VERSION 5.8 ;
BUSBITCHARS "[]" ;
DIVIDERCHAR "/" ;
UNITS
    DATABASE MICRONS 1000 ;
END UNITS

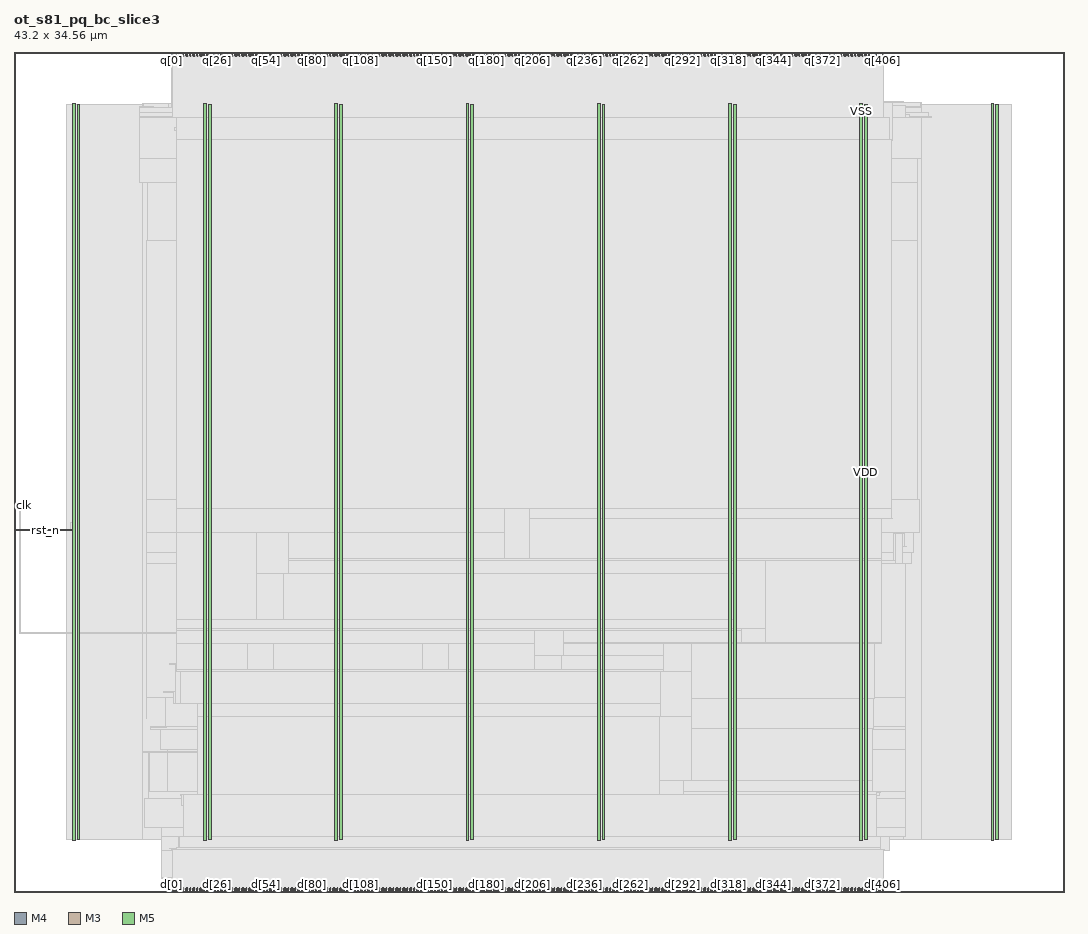
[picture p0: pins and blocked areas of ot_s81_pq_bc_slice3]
MACRO ot_s81_pq_bc_slice3
  FOREIGN ot_s81_pq_bc_slice3 0 0 ;
  CLASS BLOCK ;
  SIZE 43.2 BY 34.56 ;
  PIN clk
    DIRECTION INPUT ;
    USE SIGNAL ;
    PORT
      LAYER M4 ;
        RECT  0 15.888 0.192 15.912 ;
    END
    PORT
      LAYER M4 ;
        RECT  0.156 15.888 0.275 15.912 ;
    END
  END clk
  PIN d[0]
    DIRECTION INPUT ;
    USE SIGNAL ;
    PORT
      LAYER M3 ;
        RECT  6.48 0 6.498 0.144 ;
    END
  END d[0]
  PIN d[100]
    DIRECTION INPUT ;
    USE SIGNAL ;
    PORT
      LAYER M3 ;
        RECT  13.68 0 13.698 0.144 ;
    END
  END d[100]
  PIN d[101]
    DIRECTION INPUT ;
    USE SIGNAL ;
    PORT
      LAYER M5 ;
        RECT  13.728 0 13.752 0.192 ;
    END
  END d[101]
  PIN d[102]
    DIRECTION INPUT ;
    USE SIGNAL ;
    PORT
      LAYER M3 ;
        RECT  13.824 0 13.842 0.144 ;
    END
  END d[102]
  PIN d[103]
    DIRECTION INPUT ;
    USE SIGNAL ;
    PORT
      LAYER M5 ;
        RECT  13.872 0 13.896 0.192 ;
    END
  END d[103]
  PIN d[104]
    DIRECTION INPUT ;
    USE SIGNAL ;
    PORT
      LAYER M3 ;
        RECT  13.968 0 13.986 0.144 ;
    END
  END d[104]
  PIN d[105]
    DIRECTION INPUT ;
    USE SIGNAL ;
    PORT
      LAYER M5 ;
        RECT  14.016 0 14.04 0.192 ;
    END
  END d[105]
  PIN d[106]
    DIRECTION INPUT ;
    USE SIGNAL ;
    PORT
      LAYER M3 ;
        RECT  14.112 0 14.13 0.144 ;
    END
  END d[106]
  PIN d[107]
    DIRECTION INPUT ;
    USE SIGNAL ;
    PORT
      LAYER M5 ;
        RECT  14.16 0 14.184 0.192 ;
    END
  END d[107]
  PIN d[108]
    DIRECTION INPUT ;
    USE SIGNAL ;
    PORT
      LAYER M3 ;
        RECT  14.256 0 14.274 0.144 ;
    END
  END d[108]
  PIN d[109]
    DIRECTION INPUT ;
    USE SIGNAL ;
    PORT
      LAYER M5 ;
        RECT  14.304 0 14.328 0.192 ;
    END
  END d[109]
  PIN d[10]
    DIRECTION INPUT ;
    USE SIGNAL ;
    PORT
      LAYER M3 ;
        RECT  7.2 0 7.218 0.144 ;
    END
  END d[10]
  PIN d[110]
    DIRECTION INPUT ;
    USE SIGNAL ;
    PORT
      LAYER M3 ;
        RECT  14.4 0 14.418 0.144 ;
    END
  END d[110]
  PIN d[111]
    DIRECTION INPUT ;
    USE SIGNAL ;
    PORT
      LAYER M5 ;
        RECT  14.448 0 14.472 0.192 ;
    END
  END d[111]
  PIN d[112]
    DIRECTION INPUT ;
    USE SIGNAL ;
    PORT
      LAYER M3 ;
        RECT  14.544 0 14.562 0.144 ;
    END
  END d[112]
  PIN d[113]
    DIRECTION INPUT ;
    USE SIGNAL ;
    PORT
      LAYER M5 ;
        RECT  14.592 0 14.616 0.192 ;
    END
  END d[113]
  PIN d[114]
    DIRECTION INPUT ;
    USE SIGNAL ;
    PORT
      LAYER M3 ;
        RECT  14.688 0 14.706 0.144 ;
    END
  END d[114]
  PIN d[115]
    DIRECTION INPUT ;
    USE SIGNAL ;
    PORT
      LAYER M5 ;
        RECT  14.736 0 14.76 0.192 ;
    END
  END d[115]
  PIN d[116]
    DIRECTION INPUT ;
    USE SIGNAL ;
    PORT
      LAYER M3 ;
        RECT  14.832 0 14.85 0.144 ;
    END
  END d[116]
  PIN d[117]
    DIRECTION INPUT ;
    USE SIGNAL ;
    PORT
      LAYER M5 ;
        RECT  14.88 0 14.904 0.192 ;
    END
  END d[117]
  PIN d[118]
    DIRECTION INPUT ;
    USE SIGNAL ;
    PORT
      LAYER M3 ;
        RECT  14.976 0 14.994 0.144 ;
    END
  END d[118]
  PIN d[119]
    DIRECTION INPUT ;
    USE SIGNAL ;
    PORT
      LAYER M5 ;
        RECT  15.024 0 15.048 0.192 ;
    END
  END d[119]
  PIN d[11]
    DIRECTION INPUT ;
    USE SIGNAL ;
    PORT
      LAYER M5 ;
        RECT  7.248 0 7.272 0.192 ;
    END
  END d[11]
  PIN d[120]
    DIRECTION INPUT ;
    USE SIGNAL ;
    PORT
      LAYER M3 ;
        RECT  15.12 0 15.138 0.144 ;
    END
  END d[120]
  PIN d[121]
    DIRECTION INPUT ;
    USE SIGNAL ;
    PORT
      LAYER M5 ;
        RECT  15.168 0 15.192 0.192 ;
    END
  END d[121]
  PIN d[122]
    DIRECTION INPUT ;
    USE SIGNAL ;
    PORT
      LAYER M3 ;
        RECT  15.264 0 15.282 0.144 ;
    END
  END d[122]
  PIN d[123]
    DIRECTION INPUT ;
    USE SIGNAL ;
    PORT
      LAYER M5 ;
        RECT  15.312 0 15.336 0.192 ;
    END
  END d[123]
  PIN d[124]
    DIRECTION INPUT ;
    USE SIGNAL ;
    PORT
      LAYER M3 ;
        RECT  15.408 0 15.426 0.144 ;
    END
  END d[124]
  PIN d[125]
    DIRECTION INPUT ;
    USE SIGNAL ;
    PORT
      LAYER M5 ;
        RECT  15.456 0 15.48 0.192 ;
    END
  END d[125]
  PIN d[126]
    DIRECTION INPUT ;
    USE SIGNAL ;
    PORT
      LAYER M3 ;
        RECT  15.552 0 15.57 0.144 ;
    END
  END d[126]
  PIN d[127]
    DIRECTION INPUT ;
    USE SIGNAL ;
    PORT
      LAYER M5 ;
        RECT  15.6 0 15.624 0.192 ;
    END
  END d[127]
  PIN d[128]
    DIRECTION INPUT ;
    USE SIGNAL ;
    PORT
      LAYER M3 ;
        RECT  15.696 0 15.714 0.144 ;
    END
  END d[128]
  PIN d[129]
    DIRECTION INPUT ;
    USE SIGNAL ;
    PORT
      LAYER M5 ;
        RECT  15.744 0 15.768 0.192 ;
    END
  END d[129]
  PIN d[12]
    DIRECTION INPUT ;
    USE SIGNAL ;
    PORT
      LAYER M3 ;
        RECT  7.344 0 7.362 0.144 ;
    END
  END d[12]
  PIN d[130]
    DIRECTION INPUT ;
    USE SIGNAL ;
    PORT
      LAYER M3 ;
        RECT  15.84 0 15.858 0.144 ;
    END
  END d[130]
  PIN d[131]
    DIRECTION INPUT ;
    USE SIGNAL ;
    PORT
      LAYER M5 ;
        RECT  15.888 0 15.912 0.192 ;
    END
  END d[131]
  PIN d[132]
    DIRECTION INPUT ;
    USE SIGNAL ;
    PORT
      LAYER M3 ;
        RECT  15.984 0 16.002 0.144 ;
    END
  END d[132]
  PIN d[133]
    DIRECTION INPUT ;
    USE SIGNAL ;
    PORT
      LAYER M5 ;
        RECT  16.032 0 16.056 0.192 ;
    END
  END d[133]
  PIN d[134]
    DIRECTION INPUT ;
    USE SIGNAL ;
    PORT
      LAYER M3 ;
        RECT  16.128 0 16.146 0.144 ;
    END
  END d[134]
  PIN d[135]
    DIRECTION INPUT ;
    USE SIGNAL ;
    PORT
      LAYER M5 ;
        RECT  16.176 0 16.2 0.192 ;
    END
  END d[135]
  PIN d[136]
    DIRECTION INPUT ;
    USE SIGNAL ;
    PORT
      LAYER M3 ;
        RECT  16.272 0 16.29 0.144 ;
    END
  END d[136]
  PIN d[137]
    DIRECTION INPUT ;
    USE SIGNAL ;
    PORT
      LAYER M5 ;
        RECT  16.32 0 16.344 0.192 ;
    END
  END d[137]
  PIN d[138]
    DIRECTION INPUT ;
    USE SIGNAL ;
    PORT
      LAYER M3 ;
        RECT  16.416 0 16.434 0.144 ;
    END
  END d[138]
  PIN d[139]
    DIRECTION INPUT ;
    USE SIGNAL ;
    PORT
      LAYER M5 ;
        RECT  16.464 0 16.488 0.192 ;
    END
  END d[139]
  PIN d[13]
    DIRECTION INPUT ;
    USE SIGNAL ;
    PORT
      LAYER M5 ;
        RECT  7.392 0 7.416 0.192 ;
    END
  END d[13]
  PIN d[140]
    DIRECTION INPUT ;
    USE SIGNAL ;
    PORT
      LAYER M3 ;
        RECT  16.56 0 16.578 0.144 ;
    END
  END d[140]
  PIN d[141]
    DIRECTION INPUT ;
    USE SIGNAL ;
    PORT
      LAYER M5 ;
        RECT  16.608 0 16.632 0.192 ;
    END
  END d[141]
  PIN d[142]
    DIRECTION INPUT ;
    USE SIGNAL ;
    PORT
      LAYER M3 ;
        RECT  16.704 0 16.722 0.144 ;
    END
  END d[142]
  PIN d[143]
    DIRECTION INPUT ;
    USE SIGNAL ;
    PORT
      LAYER M5 ;
        RECT  16.752 0 16.776 0.192 ;
    END
  END d[143]
  PIN d[144]
    DIRECTION INPUT ;
    USE SIGNAL ;
    PORT
      LAYER M3 ;
        RECT  16.848 0 16.866 0.144 ;
    END
  END d[144]
  PIN d[145]
    DIRECTION INPUT ;
    USE SIGNAL ;
    PORT
      LAYER M5 ;
        RECT  16.896 0 16.92 0.192 ;
    END
  END d[145]
  PIN d[146]
    DIRECTION INPUT ;
    USE SIGNAL ;
    PORT
      LAYER M3 ;
        RECT  16.992 0 17.01 0.144 ;
    END
  END d[146]
  PIN d[147]
    DIRECTION INPUT ;
    USE SIGNAL ;
    PORT
      LAYER M5 ;
        RECT  17.04 0 17.064 0.192 ;
    END
  END d[147]
  PIN d[148]
    DIRECTION INPUT ;
    USE SIGNAL ;
    PORT
      LAYER M3 ;
        RECT  17.136 0 17.154 0.144 ;
    END
  END d[148]
  PIN d[149]
    DIRECTION INPUT ;
    USE SIGNAL ;
    PORT
      LAYER M5 ;
        RECT  17.184 0 17.208 0.192 ;
    END
  END d[149]
  PIN d[14]
    DIRECTION INPUT ;
    USE SIGNAL ;
    PORT
      LAYER M3 ;
        RECT  7.488 0 7.506 0.144 ;
    END
  END d[14]
  PIN d[150]
    DIRECTION INPUT ;
    USE SIGNAL ;
    PORT
      LAYER M3 ;
        RECT  17.28 0 17.298 0.144 ;
    END
  END d[150]
  PIN d[151]
    DIRECTION INPUT ;
    USE SIGNAL ;
    PORT
      LAYER M5 ;
        RECT  17.328 0 17.352 0.192 ;
    END
  END d[151]
  PIN d[152]
    DIRECTION INPUT ;
    USE SIGNAL ;
    PORT
      LAYER M3 ;
        RECT  17.424 0 17.442 0.144 ;
    END
  END d[152]
  PIN d[153]
    DIRECTION INPUT ;
    USE SIGNAL ;
    PORT
      LAYER M5 ;
        RECT  17.472 0 17.496 0.192 ;
    END
  END d[153]
  PIN d[154]
    DIRECTION INPUT ;
    USE SIGNAL ;
    PORT
      LAYER M3 ;
        RECT  17.568 0 17.586 0.144 ;
    END
  END d[154]
  PIN d[155]
    DIRECTION INPUT ;
    USE SIGNAL ;
    PORT
      LAYER M5 ;
        RECT  17.616 0 17.64 0.192 ;
    END
  END d[155]
  PIN d[156]
    DIRECTION INPUT ;
    USE SIGNAL ;
    PORT
      LAYER M3 ;
        RECT  17.712 0 17.73 0.144 ;
    END
  END d[156]
  PIN d[157]
    DIRECTION INPUT ;
    USE SIGNAL ;
    PORT
      LAYER M5 ;
        RECT  17.76 0 17.784 0.192 ;
    END
  END d[157]
  PIN d[158]
    DIRECTION INPUT ;
    USE SIGNAL ;
    PORT
      LAYER M3 ;
        RECT  17.856 0 17.874 0.144 ;
    END
  END d[158]
  PIN d[159]
    DIRECTION INPUT ;
    USE SIGNAL ;
    PORT
      LAYER M5 ;
        RECT  17.904 0 17.928 0.192 ;
    END
  END d[159]
  PIN d[15]
    DIRECTION INPUT ;
    USE SIGNAL ;
    PORT
      LAYER M5 ;
        RECT  7.536 0 7.56 0.192 ;
    END
  END d[15]
  PIN d[160]
    DIRECTION INPUT ;
    USE SIGNAL ;
    PORT
      LAYER M3 ;
        RECT  18 0 18.018 0.144 ;
    END
  END d[160]
  PIN d[161]
    DIRECTION INPUT ;
    USE SIGNAL ;
    PORT
      LAYER M5 ;
        RECT  18.048 0 18.072 0.192 ;
    END
  END d[161]
  PIN d[162]
    DIRECTION INPUT ;
    USE SIGNAL ;
    PORT
      LAYER M3 ;
        RECT  18.144 0 18.162 0.144 ;
    END
  END d[162]
  PIN d[163]
    DIRECTION INPUT ;
    USE SIGNAL ;
    PORT
      LAYER M5 ;
        RECT  18.192 0 18.216 0.192 ;
    END
  END d[163]
  PIN d[164]
    DIRECTION INPUT ;
    USE SIGNAL ;
    PORT
      LAYER M3 ;
        RECT  18.288 0 18.306 0.144 ;
    END
  END d[164]
  PIN d[165]
    DIRECTION INPUT ;
    USE SIGNAL ;
    PORT
      LAYER M5 ;
        RECT  18.336 0 18.36 0.192 ;
    END
  END d[165]
  PIN d[166]
    DIRECTION INPUT ;
    USE SIGNAL ;
    PORT
      LAYER M3 ;
        RECT  18.432 0 18.45 0.144 ;
    END
  END d[166]
  PIN d[167]
    DIRECTION INPUT ;
    USE SIGNAL ;
    PORT
      LAYER M5 ;
        RECT  18.48 0 18.504 0.192 ;
    END
  END d[167]
  PIN d[168]
    DIRECTION INPUT ;
    USE SIGNAL ;
    PORT
      LAYER M3 ;
        RECT  18.576 0 18.594 0.144 ;
    END
  END d[168]
  PIN d[169]
    DIRECTION INPUT ;
    USE SIGNAL ;
    PORT
      LAYER M5 ;
        RECT  18.624 0 18.648 0.192 ;
    END
  END d[169]
  PIN d[16]
    DIRECTION INPUT ;
    USE SIGNAL ;
    PORT
      LAYER M3 ;
        RECT  7.632 0 7.65 0.144 ;
    END
  END d[16]
  PIN d[170]
    DIRECTION INPUT ;
    USE SIGNAL ;
    PORT
      LAYER M3 ;
        RECT  18.72 0 18.738 0.144 ;
    END
  END d[170]
  PIN d[171]
    DIRECTION INPUT ;
    USE SIGNAL ;
    PORT
      LAYER M5 ;
        RECT  18.768 0 18.792 0.192 ;
    END
  END d[171]
  PIN d[172]
    DIRECTION INPUT ;
    USE SIGNAL ;
    PORT
      LAYER M3 ;
        RECT  18.864 0 18.882 0.144 ;
    END
  END d[172]
  PIN d[173]
    DIRECTION INPUT ;
    USE SIGNAL ;
    PORT
      LAYER M5 ;
        RECT  18.912 0 18.936 0.192 ;
    END
  END d[173]
  PIN d[174]
    DIRECTION INPUT ;
    USE SIGNAL ;
    PORT
      LAYER M3 ;
        RECT  19.008 0 19.026 0.144 ;
    END
  END d[174]
  PIN d[175]
    DIRECTION INPUT ;
    USE SIGNAL ;
    PORT
      LAYER M5 ;
        RECT  19.056 0 19.08 0.192 ;
    END
  END d[175]
  PIN d[176]
    DIRECTION INPUT ;
    USE SIGNAL ;
    PORT
      LAYER M3 ;
        RECT  19.152 0 19.17 0.144 ;
    END
  END d[176]
  PIN d[177]
    DIRECTION INPUT ;
    USE SIGNAL ;
    PORT
      LAYER M5 ;
        RECT  19.2 0 19.224 0.192 ;
    END
  END d[177]
  PIN d[178]
    DIRECTION INPUT ;
    USE SIGNAL ;
    PORT
      LAYER M3 ;
        RECT  19.296 0 19.314 0.144 ;
    END
  END d[178]
  PIN d[179]
    DIRECTION INPUT ;
    USE SIGNAL ;
    PORT
      LAYER M5 ;
        RECT  19.344 0 19.368 0.192 ;
    END
  END d[179]
  PIN d[17]
    DIRECTION INPUT ;
    USE SIGNAL ;
    PORT
      LAYER M5 ;
        RECT  7.68 0 7.704 0.192 ;
    END
  END d[17]
  PIN d[180]
    DIRECTION INPUT ;
    USE SIGNAL ;
    PORT
      LAYER M3 ;
        RECT  19.44 0 19.458 0.144 ;
    END
  END d[180]
  PIN d[181]
    DIRECTION INPUT ;
    USE SIGNAL ;
    PORT
      LAYER M5 ;
        RECT  19.488 0 19.512 0.192 ;
    END
  END d[181]
  PIN d[182]
    DIRECTION INPUT ;
    USE SIGNAL ;
    PORT
      LAYER M3 ;
        RECT  19.584 0 19.602 0.144 ;
    END
  END d[182]
  PIN d[183]
    DIRECTION INPUT ;
    USE SIGNAL ;
    PORT
      LAYER M5 ;
        RECT  19.632 0 19.656 0.192 ;
    END
  END d[183]
  PIN d[184]
    DIRECTION INPUT ;
    USE SIGNAL ;
    PORT
      LAYER M3 ;
        RECT  19.728 0 19.746 0.144 ;
    END
  END d[184]
  PIN d[185]
    DIRECTION INPUT ;
    USE SIGNAL ;
    PORT
      LAYER M5 ;
        RECT  19.776 0 19.8 0.192 ;
    END
  END d[185]
  PIN d[186]
    DIRECTION INPUT ;
    USE SIGNAL ;
    PORT
      LAYER M3 ;
        RECT  19.872 0 19.89 0.144 ;
    END
  END d[186]
  PIN d[187]
    DIRECTION INPUT ;
    USE SIGNAL ;
    PORT
      LAYER M5 ;
        RECT  19.92 0 19.944 0.192 ;
    END
  END d[187]
  PIN d[188]
    DIRECTION INPUT ;
    USE SIGNAL ;
    PORT
      LAYER M3 ;
        RECT  20.016 0 20.034 0.144 ;
    END
  END d[188]
  PIN d[189]
    DIRECTION INPUT ;
    USE SIGNAL ;
    PORT
      LAYER M5 ;
        RECT  20.064 0 20.088 0.192 ;
    END
  END d[189]
  PIN d[18]
    DIRECTION INPUT ;
    USE SIGNAL ;
    PORT
      LAYER M3 ;
        RECT  7.776 0 7.794 0.144 ;
    END
  END d[18]
  PIN d[190]
    DIRECTION INPUT ;
    USE SIGNAL ;
    PORT
      LAYER M3 ;
        RECT  20.16 0 20.178 0.144 ;
    END
  END d[190]
  PIN d[191]
    DIRECTION INPUT ;
    USE SIGNAL ;
    PORT
      LAYER M5 ;
        RECT  20.208 0 20.232 0.192 ;
    END
  END d[191]
  PIN d[192]
    DIRECTION INPUT ;
    USE SIGNAL ;
    PORT
      LAYER M3 ;
        RECT  20.304 0 20.322 0.144 ;
    END
  END d[192]
  PIN d[193]
    DIRECTION INPUT ;
    USE SIGNAL ;
    PORT
      LAYER M5 ;
        RECT  20.352 0 20.376 0.192 ;
    END
  END d[193]
  PIN d[194]
    DIRECTION INPUT ;
    USE SIGNAL ;
    PORT
      LAYER M3 ;
        RECT  20.448 0 20.466 0.144 ;
    END
  END d[194]
  PIN d[195]
    DIRECTION INPUT ;
    USE SIGNAL ;
    PORT
      LAYER M5 ;
        RECT  20.496 0 20.52 0.192 ;
    END
  END d[195]
  PIN d[196]
    DIRECTION INPUT ;
    USE SIGNAL ;
    PORT
      LAYER M3 ;
        RECT  20.592 0 20.61 0.144 ;
    END
  END d[196]
  PIN d[197]
    DIRECTION INPUT ;
    USE SIGNAL ;
    PORT
      LAYER M5 ;
        RECT  20.64 0 20.664 0.192 ;
    END
  END d[197]
  PIN d[198]
    DIRECTION INPUT ;
    USE SIGNAL ;
    PORT
      LAYER M3 ;
        RECT  20.736 0 20.754 0.144 ;
    END
  END d[198]
  PIN d[199]
    DIRECTION INPUT ;
    USE SIGNAL ;
    PORT
      LAYER M5 ;
        RECT  20.784 0 20.808 0.192 ;
    END
  END d[199]
  PIN d[19]
    DIRECTION INPUT ;
    USE SIGNAL ;
    PORT
      LAYER M5 ;
        RECT  7.824 0 7.848 0.192 ;
    END
  END d[19]
  PIN d[1]
    DIRECTION INPUT ;
    USE SIGNAL ;
    PORT
      LAYER M5 ;
        RECT  6.528 0 6.552 0.192 ;
    END
  END d[1]
  PIN d[200]
    DIRECTION INPUT ;
    USE SIGNAL ;
    PORT
      LAYER M3 ;
        RECT  20.88 0 20.898 0.144 ;
    END
  END d[200]
  PIN d[201]
    DIRECTION INPUT ;
    USE SIGNAL ;
    PORT
      LAYER M5 ;
        RECT  20.928 0 20.952 0.192 ;
    END
  END d[201]
  PIN d[202]
    DIRECTION INPUT ;
    USE SIGNAL ;
    PORT
      LAYER M3 ;
        RECT  21.024 0 21.042 0.144 ;
    END
  END d[202]
  PIN d[203]
    DIRECTION INPUT ;
    USE SIGNAL ;
    PORT
      LAYER M5 ;
        RECT  21.072 0 21.096 0.192 ;
    END
  END d[203]
  PIN d[204]
    DIRECTION INPUT ;
    USE SIGNAL ;
    PORT
      LAYER M3 ;
        RECT  21.168 0 21.186 0.144 ;
    END
  END d[204]
  PIN d[205]
    DIRECTION INPUT ;
    USE SIGNAL ;
    PORT
      LAYER M5 ;
        RECT  21.216 0 21.24 0.192 ;
    END
  END d[205]
  PIN d[206]
    DIRECTION INPUT ;
    USE SIGNAL ;
    PORT
      LAYER M3 ;
        RECT  21.312 0 21.33 0.144 ;
    END
  END d[206]
  PIN d[207]
    DIRECTION INPUT ;
    USE SIGNAL ;
    PORT
      LAYER M5 ;
        RECT  21.36 0 21.384 0.192 ;
    END
  END d[207]
  PIN d[208]
    DIRECTION INPUT ;
    USE SIGNAL ;
    PORT
      LAYER M3 ;
        RECT  21.456 0 21.474 0.144 ;
    END
  END d[208]
  PIN d[209]
    DIRECTION INPUT ;
    USE SIGNAL ;
    PORT
      LAYER M5 ;
        RECT  21.504 0 21.528 0.192 ;
    END
  END d[209]
  PIN d[20]
    DIRECTION INPUT ;
    USE SIGNAL ;
    PORT
      LAYER M3 ;
        RECT  7.92 0 7.938 0.144 ;
    END
  END d[20]
  PIN d[210]
    DIRECTION INPUT ;
    USE SIGNAL ;
    PORT
      LAYER M3 ;
        RECT  21.6 0 21.618 0.144 ;
    END
  END d[210]
  PIN d[211]
    DIRECTION INPUT ;
    USE SIGNAL ;
    PORT
      LAYER M5 ;
        RECT  21.648 0 21.672 0.192 ;
    END
  END d[211]
  PIN d[212]
    DIRECTION INPUT ;
    USE SIGNAL ;
    PORT
      LAYER M3 ;
        RECT  21.744 0 21.762 0.144 ;
    END
  END d[212]
  PIN d[213]
    DIRECTION INPUT ;
    USE SIGNAL ;
    PORT
      LAYER M5 ;
        RECT  21.792 0 21.816 0.192 ;
    END
  END d[213]
  PIN d[214]
    DIRECTION INPUT ;
    USE SIGNAL ;
    PORT
      LAYER M3 ;
        RECT  21.888 0 21.906 0.144 ;
    END
  END d[214]
  PIN d[215]
    DIRECTION INPUT ;
    USE SIGNAL ;
    PORT
      LAYER M5 ;
        RECT  21.936 0 21.96 0.192 ;
    END
  END d[215]
  PIN d[216]
    DIRECTION INPUT ;
    USE SIGNAL ;
    PORT
      LAYER M3 ;
        RECT  22.032 0 22.05 0.144 ;
    END
  END d[216]
  PIN d[217]
    DIRECTION INPUT ;
    USE SIGNAL ;
    PORT
      LAYER M5 ;
        RECT  22.08 0 22.104 0.192 ;
    END
  END d[217]
  PIN d[218]
    DIRECTION INPUT ;
    USE SIGNAL ;
    PORT
      LAYER M3 ;
        RECT  22.176 0 22.194 0.144 ;
    END
  END d[218]
  PIN d[219]
    DIRECTION INPUT ;
    USE SIGNAL ;
    PORT
      LAYER M5 ;
        RECT  22.224 0 22.248 0.192 ;
    END
  END d[219]
  PIN d[21]
    DIRECTION INPUT ;
    USE SIGNAL ;
    PORT
      LAYER M5 ;
        RECT  7.968 0 7.992 0.192 ;
    END
  END d[21]
  PIN d[220]
    DIRECTION INPUT ;
    USE SIGNAL ;
    PORT
      LAYER M3 ;
        RECT  22.32 0 22.338 0.144 ;
    END
  END d[220]
  PIN d[221]
    DIRECTION INPUT ;
    USE SIGNAL ;
    PORT
      LAYER M5 ;
        RECT  22.368 0 22.392 0.192 ;
    END
  END d[221]
  PIN d[222]
    DIRECTION INPUT ;
    USE SIGNAL ;
    PORT
      LAYER M3 ;
        RECT  22.464 0 22.482 0.144 ;
    END
  END d[222]
  PIN d[223]
    DIRECTION INPUT ;
    USE SIGNAL ;
    PORT
      LAYER M5 ;
        RECT  22.512 0 22.536 0.192 ;
    END
  END d[223]
  PIN d[224]
    DIRECTION INPUT ;
    USE SIGNAL ;
    PORT
      LAYER M3 ;
        RECT  22.608 0 22.626 0.144 ;
    END
  END d[224]
  PIN d[225]
    DIRECTION INPUT ;
    USE SIGNAL ;
    PORT
      LAYER M5 ;
        RECT  22.656 0 22.68 0.192 ;
    END
  END d[225]
  PIN d[226]
    DIRECTION INPUT ;
    USE SIGNAL ;
    PORT
      LAYER M3 ;
        RECT  22.752 0 22.77 0.144 ;
    END
  END d[226]
  PIN d[227]
    DIRECTION INPUT ;
    USE SIGNAL ;
    PORT
      LAYER M5 ;
        RECT  22.8 0 22.824 0.192 ;
    END
  END d[227]
  PIN d[228]
    DIRECTION INPUT ;
    USE SIGNAL ;
    PORT
      LAYER M3 ;
        RECT  22.896 0 22.914 0.144 ;
    END
  END d[228]
  PIN d[229]
    DIRECTION INPUT ;
    USE SIGNAL ;
    PORT
      LAYER M5 ;
        RECT  22.944 0 22.968 0.192 ;
    END
  END d[229]
  PIN d[22]
    DIRECTION INPUT ;
    USE SIGNAL ;
    PORT
      LAYER M3 ;
        RECT  8.064 0 8.082 0.144 ;
    END
  END d[22]
  PIN d[230]
    DIRECTION INPUT ;
    USE SIGNAL ;
    PORT
      LAYER M3 ;
        RECT  23.04 0 23.058 0.144 ;
    END
  END d[230]
  PIN d[231]
    DIRECTION INPUT ;
    USE SIGNAL ;
    PORT
      LAYER M5 ;
        RECT  23.088 0 23.112 0.192 ;
    END
  END d[231]
  PIN d[232]
    DIRECTION INPUT ;
    USE SIGNAL ;
    PORT
      LAYER M3 ;
        RECT  23.184 0 23.202 0.144 ;
    END
  END d[232]
  PIN d[233]
    DIRECTION INPUT ;
    USE SIGNAL ;
    PORT
      LAYER M5 ;
        RECT  23.232 0 23.256 0.192 ;
    END
  END d[233]
  PIN d[234]
    DIRECTION INPUT ;
    USE SIGNAL ;
    PORT
      LAYER M3 ;
        RECT  23.328 0 23.346 0.144 ;
    END
  END d[234]
  PIN d[235]
    DIRECTION INPUT ;
    USE SIGNAL ;
    PORT
      LAYER M5 ;
        RECT  23.376 0 23.4 0.192 ;
    END
  END d[235]
  PIN d[236]
    DIRECTION INPUT ;
    USE SIGNAL ;
    PORT
      LAYER M3 ;
        RECT  23.472 0 23.49 0.144 ;
    END
  END d[236]
  PIN d[237]
    DIRECTION INPUT ;
    USE SIGNAL ;
    PORT
      LAYER M5 ;
        RECT  23.52 0 23.544 0.192 ;
    END
  END d[237]
  PIN d[238]
    DIRECTION INPUT ;
    USE SIGNAL ;
    PORT
      LAYER M3 ;
        RECT  23.616 0 23.634 0.144 ;
    END
  END d[238]
  PIN d[239]
    DIRECTION INPUT ;
    USE SIGNAL ;
    PORT
      LAYER M5 ;
        RECT  23.664 0 23.688 0.192 ;
    END
  END d[239]
  PIN d[23]
    DIRECTION INPUT ;
    USE SIGNAL ;
    PORT
      LAYER M5 ;
        RECT  8.112 0 8.136 0.192 ;
    END
  END d[23]
  PIN d[240]
    DIRECTION INPUT ;
    USE SIGNAL ;
    PORT
      LAYER M3 ;
        RECT  23.76 0 23.778 0.144 ;
    END
  END d[240]
  PIN d[241]
    DIRECTION INPUT ;
    USE SIGNAL ;
    PORT
      LAYER M5 ;
        RECT  23.808 0 23.832 0.192 ;
    END
  END d[241]
  PIN d[242]
    DIRECTION INPUT ;
    USE SIGNAL ;
    PORT
      LAYER M3 ;
        RECT  23.904 0 23.922 0.144 ;
    END
  END d[242]
  PIN d[243]
    DIRECTION INPUT ;
    USE SIGNAL ;
    PORT
      LAYER M5 ;
        RECT  23.952 0 23.976 0.192 ;
    END
  END d[243]
  PIN d[244]
    DIRECTION INPUT ;
    USE SIGNAL ;
    PORT
      LAYER M3 ;
        RECT  24.048 0 24.066 0.144 ;
    END
  END d[244]
  PIN d[245]
    DIRECTION INPUT ;
    USE SIGNAL ;
    PORT
      LAYER M5 ;
        RECT  24.096 0 24.12 0.192 ;
    END
  END d[245]
  PIN d[246]
    DIRECTION INPUT ;
    USE SIGNAL ;
    PORT
      LAYER M3 ;
        RECT  24.192 0 24.21 0.144 ;
    END
  END d[246]
  PIN d[247]
    DIRECTION INPUT ;
    USE SIGNAL ;
    PORT
      LAYER M5 ;
        RECT  24.24 0 24.264 0.192 ;
    END
  END d[247]
  PIN d[248]
    DIRECTION INPUT ;
    USE SIGNAL ;
    PORT
      LAYER M3 ;
        RECT  24.336 0 24.354 0.144 ;
    END
  END d[248]
  PIN d[249]
    DIRECTION INPUT ;
    USE SIGNAL ;
    PORT
      LAYER M5 ;
        RECT  24.384 0 24.408 0.192 ;
    END
  END d[249]
  PIN d[24]
    DIRECTION INPUT ;
    USE SIGNAL ;
    PORT
      LAYER M3 ;
        RECT  8.208 0 8.226 0.144 ;
    END
  END d[24]
  PIN d[250]
    DIRECTION INPUT ;
    USE SIGNAL ;
    PORT
      LAYER M3 ;
        RECT  24.48 0 24.498 0.144 ;
    END
  END d[250]
  PIN d[251]
    DIRECTION INPUT ;
    USE SIGNAL ;
    PORT
      LAYER M5 ;
        RECT  24.528 0 24.552 0.192 ;
    END
  END d[251]
  PIN d[252]
    DIRECTION INPUT ;
    USE SIGNAL ;
    PORT
      LAYER M3 ;
        RECT  24.624 0 24.642 0.144 ;
    END
  END d[252]
  PIN d[253]
    DIRECTION INPUT ;
    USE SIGNAL ;
    PORT
      LAYER M5 ;
        RECT  24.672 0 24.696 0.192 ;
    END
  END d[253]
  PIN d[254]
    DIRECTION INPUT ;
    USE SIGNAL ;
    PORT
      LAYER M3 ;
        RECT  24.768 0 24.786 0.144 ;
    END
  END d[254]
  PIN d[255]
    DIRECTION INPUT ;
    USE SIGNAL ;
    PORT
      LAYER M5 ;
        RECT  24.816 0 24.84 0.192 ;
    END
  END d[255]
  PIN d[256]
    DIRECTION INPUT ;
    USE SIGNAL ;
    PORT
      LAYER M3 ;
        RECT  24.912 0 24.93 0.144 ;
    END
  END d[256]
  PIN d[257]
    DIRECTION INPUT ;
    USE SIGNAL ;
    PORT
      LAYER M5 ;
        RECT  24.96 0 24.984 0.192 ;
    END
  END d[257]
  PIN d[258]
    DIRECTION INPUT ;
    USE SIGNAL ;
    PORT
      LAYER M3 ;
        RECT  25.056 0 25.074 0.144 ;
    END
  END d[258]
  PIN d[259]
    DIRECTION INPUT ;
    USE SIGNAL ;
    PORT
      LAYER M5 ;
        RECT  25.104 0 25.128 0.192 ;
    END
  END d[259]
  PIN d[25]
    DIRECTION INPUT ;
    USE SIGNAL ;
    PORT
      LAYER M5 ;
        RECT  8.256 0 8.28 0.192 ;
    END
  END d[25]
  PIN d[260]
    DIRECTION INPUT ;
    USE SIGNAL ;
    PORT
      LAYER M3 ;
        RECT  25.2 0 25.218 0.144 ;
    END
  END d[260]
  PIN d[261]
    DIRECTION INPUT ;
    USE SIGNAL ;
    PORT
      LAYER M5 ;
        RECT  25.248 0 25.272 0.192 ;
    END
  END d[261]
  PIN d[262]
    DIRECTION INPUT ;
    USE SIGNAL ;
    PORT
      LAYER M3 ;
        RECT  25.344 0 25.362 0.144 ;
    END
  END d[262]
  PIN d[263]
    DIRECTION INPUT ;
    USE SIGNAL ;
    PORT
      LAYER M5 ;
        RECT  25.392 0 25.416 0.192 ;
    END
  END d[263]
  PIN d[264]
    DIRECTION INPUT ;
    USE SIGNAL ;
    PORT
      LAYER M3 ;
        RECT  25.488 0 25.506 0.144 ;
    END
  END d[264]
  PIN d[265]
    DIRECTION INPUT ;
    USE SIGNAL ;
    PORT
      LAYER M5 ;
        RECT  25.536 0 25.56 0.192 ;
    END
  END d[265]
  PIN d[266]
    DIRECTION INPUT ;
    USE SIGNAL ;
    PORT
      LAYER M3 ;
        RECT  25.632 0 25.65 0.144 ;
    END
  END d[266]
  PIN d[267]
    DIRECTION INPUT ;
    USE SIGNAL ;
    PORT
      LAYER M5 ;
        RECT  25.68 0 25.704 0.192 ;
    END
  END d[267]
  PIN d[268]
    DIRECTION INPUT ;
    USE SIGNAL ;
    PORT
      LAYER M3 ;
        RECT  25.776 0 25.794 0.144 ;
    END
  END d[268]
  PIN d[269]
    DIRECTION INPUT ;
    USE SIGNAL ;
    PORT
      LAYER M5 ;
        RECT  25.824 0 25.848 0.192 ;
    END
  END d[269]
  PIN d[26]
    DIRECTION INPUT ;
    USE SIGNAL ;
    PORT
      LAYER M3 ;
        RECT  8.352 0 8.37 0.144 ;
    END
  END d[26]
  PIN d[270]
    DIRECTION INPUT ;
    USE SIGNAL ;
    PORT
      LAYER M3 ;
        RECT  25.92 0 25.938 0.144 ;
    END
  END d[270]
  PIN d[271]
    DIRECTION INPUT ;
    USE SIGNAL ;
    PORT
      LAYER M5 ;
        RECT  25.968 0 25.992 0.192 ;
    END
  END d[271]
  PIN d[272]
    DIRECTION INPUT ;
    USE SIGNAL ;
    PORT
      LAYER M3 ;
        RECT  26.064 0 26.082 0.144 ;
    END
  END d[272]
  PIN d[273]
    DIRECTION INPUT ;
    USE SIGNAL ;
    PORT
      LAYER M5 ;
        RECT  26.112 0 26.136 0.192 ;
    END
  END d[273]
  PIN d[274]
    DIRECTION INPUT ;
    USE SIGNAL ;
    PORT
      LAYER M3 ;
        RECT  26.208 0 26.226 0.144 ;
    END
  END d[274]
  PIN d[275]
    DIRECTION INPUT ;
    USE SIGNAL ;
    PORT
      LAYER M5 ;
        RECT  26.256 0 26.28 0.192 ;
    END
  END d[275]
  PIN d[276]
    DIRECTION INPUT ;
    USE SIGNAL ;
    PORT
      LAYER M3 ;
        RECT  26.352 0 26.37 0.144 ;
    END
  END d[276]
  PIN d[277]
    DIRECTION INPUT ;
    USE SIGNAL ;
    PORT
      LAYER M5 ;
        RECT  26.4 0 26.424 0.192 ;
    END
  END d[277]
  PIN d[278]
    DIRECTION INPUT ;
    USE SIGNAL ;
    PORT
      LAYER M3 ;
        RECT  26.496 0 26.514 0.144 ;
    END
  END d[278]
  PIN d[279]
    DIRECTION INPUT ;
    USE SIGNAL ;
    PORT
      LAYER M5 ;
        RECT  26.544 0 26.568 0.192 ;
    END
  END d[279]
  PIN d[27]
    DIRECTION INPUT ;
    USE SIGNAL ;
    PORT
      LAYER M5 ;
        RECT  8.4 0 8.424 0.192 ;
    END
  END d[27]
  PIN d[280]
    DIRECTION INPUT ;
    USE SIGNAL ;
    PORT
      LAYER M3 ;
        RECT  26.64 0 26.658 0.144 ;
    END
  END d[280]
  PIN d[281]
    DIRECTION INPUT ;
    USE SIGNAL ;
    PORT
      LAYER M5 ;
        RECT  26.688 0 26.712 0.192 ;
    END
  END d[281]
  PIN d[282]
    DIRECTION INPUT ;
    USE SIGNAL ;
    PORT
      LAYER M3 ;
        RECT  26.784 0 26.802 0.144 ;
    END
  END d[282]
  PIN d[283]
    DIRECTION INPUT ;
    USE SIGNAL ;
    PORT
      LAYER M5 ;
        RECT  26.832 0 26.856 0.192 ;
    END
  END d[283]
  PIN d[284]
    DIRECTION INPUT ;
    USE SIGNAL ;
    PORT
      LAYER M3 ;
        RECT  26.928 0 26.946 0.144 ;
    END
  END d[284]
  PIN d[285]
    DIRECTION INPUT ;
    USE SIGNAL ;
    PORT
      LAYER M5 ;
        RECT  26.976 0 27 0.192 ;
    END
  END d[285]
  PIN d[286]
    DIRECTION INPUT ;
    USE SIGNAL ;
    PORT
      LAYER M3 ;
        RECT  27.072 0 27.09 0.144 ;
    END
  END d[286]
  PIN d[287]
    DIRECTION INPUT ;
    USE SIGNAL ;
    PORT
      LAYER M5 ;
        RECT  27.12 0 27.144 0.192 ;
    END
  END d[287]
  PIN d[288]
    DIRECTION INPUT ;
    USE SIGNAL ;
    PORT
      LAYER M3 ;
        RECT  27.216 0 27.234 0.144 ;
    END
  END d[288]
  PIN d[289]
    DIRECTION INPUT ;
    USE SIGNAL ;
    PORT
      LAYER M5 ;
        RECT  27.264 0 27.288 0.192 ;
    END
  END d[289]
  PIN d[28]
    DIRECTION INPUT ;
    USE SIGNAL ;
    PORT
      LAYER M3 ;
        RECT  8.496 0 8.514 0.144 ;
    END
  END d[28]
  PIN d[290]
    DIRECTION INPUT ;
    USE SIGNAL ;
    PORT
      LAYER M3 ;
        RECT  27.36 0 27.378 0.144 ;
    END
  END d[290]
  PIN d[291]
    DIRECTION INPUT ;
    USE SIGNAL ;
    PORT
      LAYER M5 ;
        RECT  27.408 0 27.432 0.192 ;
    END
  END d[291]
  PIN d[292]
    DIRECTION INPUT ;
    USE SIGNAL ;
    PORT
      LAYER M3 ;
        RECT  27.504 0 27.522 0.144 ;
    END
  END d[292]
  PIN d[293]
    DIRECTION INPUT ;
    USE SIGNAL ;
    PORT
      LAYER M5 ;
        RECT  27.552 0 27.576 0.192 ;
    END
  END d[293]
  PIN d[294]
    DIRECTION INPUT ;
    USE SIGNAL ;
    PORT
      LAYER M3 ;
        RECT  27.648 0 27.666 0.144 ;
    END
  END d[294]
  PIN d[295]
    DIRECTION INPUT ;
    USE SIGNAL ;
    PORT
      LAYER M5 ;
        RECT  27.696 0 27.72 0.192 ;
    END
  END d[295]
  PIN d[296]
    DIRECTION INPUT ;
    USE SIGNAL ;
    PORT
      LAYER M3 ;
        RECT  27.792 0 27.81 0.144 ;
    END
  END d[296]
  PIN d[297]
    DIRECTION INPUT ;
    USE SIGNAL ;
    PORT
      LAYER M5 ;
        RECT  27.84 0 27.864 0.192 ;
    END
  END d[297]
  PIN d[298]
    DIRECTION INPUT ;
    USE SIGNAL ;
    PORT
      LAYER M3 ;
        RECT  27.936 0 27.954 0.144 ;
    END
  END d[298]
  PIN d[299]
    DIRECTION INPUT ;
    USE SIGNAL ;
    PORT
      LAYER M5 ;
        RECT  27.984 0 28.008 0.192 ;
    END
  END d[299]
  PIN d[29]
    DIRECTION INPUT ;
    USE SIGNAL ;
    PORT
      LAYER M5 ;
        RECT  8.544 0 8.568 0.192 ;
    END
  END d[29]
  PIN d[2]
    DIRECTION INPUT ;
    USE SIGNAL ;
    PORT
      LAYER M3 ;
        RECT  6.624 0 6.642 0.144 ;
    END
  END d[2]
  PIN d[300]
    DIRECTION INPUT ;
    USE SIGNAL ;
    PORT
      LAYER M3 ;
        RECT  28.08 0 28.098 0.144 ;
    END
  END d[300]
  PIN d[301]
    DIRECTION INPUT ;
    USE SIGNAL ;
    PORT
      LAYER M5 ;
        RECT  28.128 0 28.152 0.192 ;
    END
  END d[301]
  PIN d[302]
    DIRECTION INPUT ;
    USE SIGNAL ;
    PORT
      LAYER M3 ;
        RECT  28.224 0 28.242 0.144 ;
    END
  END d[302]
  PIN d[303]
    DIRECTION INPUT ;
    USE SIGNAL ;
    PORT
      LAYER M5 ;
        RECT  28.272 0 28.296 0.192 ;
    END
  END d[303]
  PIN d[304]
    DIRECTION INPUT ;
    USE SIGNAL ;
    PORT
      LAYER M3 ;
        RECT  28.368 0 28.386 0.144 ;
    END
  END d[304]
  PIN d[305]
    DIRECTION INPUT ;
    USE SIGNAL ;
    PORT
      LAYER M5 ;
        RECT  28.416 0 28.44 0.192 ;
    END
  END d[305]
  PIN d[306]
    DIRECTION INPUT ;
    USE SIGNAL ;
    PORT
      LAYER M3 ;
        RECT  28.512 0 28.53 0.144 ;
    END
  END d[306]
  PIN d[307]
    DIRECTION INPUT ;
    USE SIGNAL ;
    PORT
      LAYER M5 ;
        RECT  28.56 0 28.584 0.192 ;
    END
  END d[307]
  PIN d[308]
    DIRECTION INPUT ;
    USE SIGNAL ;
    PORT
      LAYER M3 ;
        RECT  28.656 0 28.674 0.144 ;
    END
  END d[308]
  PIN d[309]
    DIRECTION INPUT ;
    USE SIGNAL ;
    PORT
      LAYER M5 ;
        RECT  28.704 0 28.728 0.192 ;
    END
  END d[309]
  PIN d[30]
    DIRECTION INPUT ;
    USE SIGNAL ;
    PORT
      LAYER M3 ;
        RECT  8.64 0 8.658 0.144 ;
    END
  END d[30]
  PIN d[310]
    DIRECTION INPUT ;
    USE SIGNAL ;
    PORT
      LAYER M3 ;
        RECT  28.8 0 28.818 0.144 ;
    END
  END d[310]
  PIN d[311]
    DIRECTION INPUT ;
    USE SIGNAL ;
    PORT
      LAYER M5 ;
        RECT  28.848 0 28.872 0.192 ;
    END
  END d[311]
  PIN d[312]
    DIRECTION INPUT ;
    USE SIGNAL ;
    PORT
      LAYER M3 ;
        RECT  28.944 0 28.962 0.144 ;
    END
  END d[312]
  PIN d[313]
    DIRECTION INPUT ;
    USE SIGNAL ;
    PORT
      LAYER M5 ;
        RECT  28.992 0 29.016 0.192 ;
    END
  END d[313]
  PIN d[314]
    DIRECTION INPUT ;
    USE SIGNAL ;
    PORT
      LAYER M3 ;
        RECT  29.088 0 29.106 0.144 ;
    END
  END d[314]
  PIN d[315]
    DIRECTION INPUT ;
    USE SIGNAL ;
    PORT
      LAYER M5 ;
        RECT  29.136 0 29.16 0.192 ;
    END
  END d[315]
  PIN d[316]
    DIRECTION INPUT ;
    USE SIGNAL ;
    PORT
      LAYER M3 ;
        RECT  29.232 0 29.25 0.144 ;
    END
  END d[316]
  PIN d[317]
    DIRECTION INPUT ;
    USE SIGNAL ;
    PORT
      LAYER M5 ;
        RECT  29.28 0 29.304 0.192 ;
    END
  END d[317]
  PIN d[318]
    DIRECTION INPUT ;
    USE SIGNAL ;
    PORT
      LAYER M3 ;
        RECT  29.376 0 29.394 0.144 ;
    END
  END d[318]
  PIN d[319]
    DIRECTION INPUT ;
    USE SIGNAL ;
    PORT
      LAYER M5 ;
        RECT  29.424 0 29.448 0.192 ;
    END
  END d[319]
  PIN d[31]
    DIRECTION INPUT ;
    USE SIGNAL ;
    PORT
      LAYER M5 ;
        RECT  8.688 0 8.712 0.192 ;
    END
  END d[31]
  PIN d[320]
    DIRECTION INPUT ;
    USE SIGNAL ;
    PORT
      LAYER M3 ;
        RECT  29.52 0 29.538 0.144 ;
    END
  END d[320]
  PIN d[321]
    DIRECTION INPUT ;
    USE SIGNAL ;
    PORT
      LAYER M5 ;
        RECT  29.568 0 29.592 0.192 ;
    END
  END d[321]
  PIN d[322]
    DIRECTION INPUT ;
    USE SIGNAL ;
    PORT
      LAYER M3 ;
        RECT  29.664 0 29.682 0.144 ;
    END
  END d[322]
  PIN d[323]
    DIRECTION INPUT ;
    USE SIGNAL ;
    PORT
      LAYER M5 ;
        RECT  29.712 0 29.736 0.192 ;
    END
  END d[323]
  PIN d[324]
    DIRECTION INPUT ;
    USE SIGNAL ;
    PORT
      LAYER M3 ;
        RECT  29.808 0 29.826 0.144 ;
    END
  END d[324]
  PIN d[325]
    DIRECTION INPUT ;
    USE SIGNAL ;
    PORT
      LAYER M5 ;
        RECT  29.856 0 29.88 0.192 ;
    END
  END d[325]
  PIN d[326]
    DIRECTION INPUT ;
    USE SIGNAL ;
    PORT
      LAYER M3 ;
        RECT  29.952 0 29.97 0.144 ;
    END
  END d[326]
  PIN d[327]
    DIRECTION INPUT ;
    USE SIGNAL ;
    PORT
      LAYER M5 ;
        RECT  30 0 30.024 0.192 ;
    END
  END d[327]
  PIN d[328]
    DIRECTION INPUT ;
    USE SIGNAL ;
    PORT
      LAYER M3 ;
        RECT  30.096 0 30.114 0.144 ;
    END
  END d[328]
  PIN d[329]
    DIRECTION INPUT ;
    USE SIGNAL ;
    PORT
      LAYER M5 ;
        RECT  30.144 0 30.168 0.192 ;
    END
  END d[329]
  PIN d[32]
    DIRECTION INPUT ;
    USE SIGNAL ;
    PORT
      LAYER M3 ;
        RECT  8.784 0 8.802 0.144 ;
    END
  END d[32]
  PIN d[330]
    DIRECTION INPUT ;
    USE SIGNAL ;
    PORT
      LAYER M3 ;
        RECT  30.24 0 30.258 0.144 ;
    END
  END d[330]
  PIN d[331]
    DIRECTION INPUT ;
    USE SIGNAL ;
    PORT
      LAYER M5 ;
        RECT  30.288 0 30.312 0.192 ;
    END
  END d[331]
  PIN d[332]
    DIRECTION INPUT ;
    USE SIGNAL ;
    PORT
      LAYER M3 ;
        RECT  30.384 0 30.402 0.144 ;
    END
  END d[332]
  PIN d[333]
    DIRECTION INPUT ;
    USE SIGNAL ;
    PORT
      LAYER M5 ;
        RECT  30.432 0 30.456 0.192 ;
    END
  END d[333]
  PIN d[334]
    DIRECTION INPUT ;
    USE SIGNAL ;
    PORT
      LAYER M3 ;
        RECT  30.528 0 30.546 0.144 ;
    END
  END d[334]
  PIN d[335]
    DIRECTION INPUT ;
    USE SIGNAL ;
    PORT
      LAYER M5 ;
        RECT  30.576 0 30.6 0.192 ;
    END
  END d[335]
  PIN d[336]
    DIRECTION INPUT ;
    USE SIGNAL ;
    PORT
      LAYER M3 ;
        RECT  30.672 0 30.69 0.144 ;
    END
  END d[336]
  PIN d[337]
    DIRECTION INPUT ;
    USE SIGNAL ;
    PORT
      LAYER M5 ;
        RECT  30.72 0 30.744 0.192 ;
    END
  END d[337]
  PIN d[338]
    DIRECTION INPUT ;
    USE SIGNAL ;
    PORT
      LAYER M3 ;
        RECT  30.816 0 30.834 0.144 ;
    END
  END d[338]
  PIN d[339]
    DIRECTION INPUT ;
    USE SIGNAL ;
    PORT
      LAYER M5 ;
        RECT  30.864 0 30.888 0.192 ;
    END
  END d[339]
  PIN d[33]
    DIRECTION INPUT ;
    USE SIGNAL ;
    PORT
      LAYER M5 ;
        RECT  8.832 0 8.856 0.192 ;
    END
  END d[33]
  PIN d[340]
    DIRECTION INPUT ;
    USE SIGNAL ;
    PORT
      LAYER M3 ;
        RECT  30.96 0 30.978 0.144 ;
    END
  END d[340]
  PIN d[341]
    DIRECTION INPUT ;
    USE SIGNAL ;
    PORT
      LAYER M5 ;
        RECT  31.008 0 31.032 0.192 ;
    END
  END d[341]
  PIN d[342]
    DIRECTION INPUT ;
    USE SIGNAL ;
    PORT
      LAYER M3 ;
        RECT  31.104 0 31.122 0.144 ;
    END
  END d[342]
  PIN d[343]
    DIRECTION INPUT ;
    USE SIGNAL ;
    PORT
      LAYER M5 ;
        RECT  31.152 0 31.176 0.192 ;
    END
  END d[343]
  PIN d[344]
    DIRECTION INPUT ;
    USE SIGNAL ;
    PORT
      LAYER M3 ;
        RECT  31.248 0 31.266 0.144 ;
    END
  END d[344]
  PIN d[345]
    DIRECTION INPUT ;
    USE SIGNAL ;
    PORT
      LAYER M5 ;
        RECT  31.296 0 31.32 0.192 ;
    END
  END d[345]
  PIN d[346]
    DIRECTION INPUT ;
    USE SIGNAL ;
    PORT
      LAYER M3 ;
        RECT  31.392 0 31.41 0.144 ;
    END
  END d[346]
  PIN d[347]
    DIRECTION INPUT ;
    USE SIGNAL ;
    PORT
      LAYER M5 ;
        RECT  31.44 0 31.464 0.192 ;
    END
  END d[347]
  PIN d[348]
    DIRECTION INPUT ;
    USE SIGNAL ;
    PORT
      LAYER M3 ;
        RECT  31.536 0 31.554 0.144 ;
    END
  END d[348]
  PIN d[349]
    DIRECTION INPUT ;
    USE SIGNAL ;
    PORT
      LAYER M5 ;
        RECT  31.584 0 31.608 0.192 ;
    END
  END d[349]
  PIN d[34]
    DIRECTION INPUT ;
    USE SIGNAL ;
    PORT
      LAYER M3 ;
        RECT  8.928 0 8.946 0.144 ;
    END
  END d[34]
  PIN d[350]
    DIRECTION INPUT ;
    USE SIGNAL ;
    PORT
      LAYER M3 ;
        RECT  31.68 0 31.698 0.144 ;
    END
  END d[350]
  PIN d[351]
    DIRECTION INPUT ;
    USE SIGNAL ;
    PORT
      LAYER M5 ;
        RECT  31.728 0 31.752 0.192 ;
    END
  END d[351]
  PIN d[352]
    DIRECTION INPUT ;
    USE SIGNAL ;
    PORT
      LAYER M3 ;
        RECT  31.824 0 31.842 0.144 ;
    END
  END d[352]
  PIN d[353]
    DIRECTION INPUT ;
    USE SIGNAL ;
    PORT
      LAYER M5 ;
        RECT  31.872 0 31.896 0.192 ;
    END
  END d[353]
  PIN d[354]
    DIRECTION INPUT ;
    USE SIGNAL ;
    PORT
      LAYER M3 ;
        RECT  31.968 0 31.986 0.144 ;
    END
  END d[354]
  PIN d[355]
    DIRECTION INPUT ;
    USE SIGNAL ;
    PORT
      LAYER M5 ;
        RECT  32.016 0 32.04 0.192 ;
    END
  END d[355]
  PIN d[356]
    DIRECTION INPUT ;
    USE SIGNAL ;
    PORT
      LAYER M3 ;
        RECT  32.112 0 32.13 0.144 ;
    END
  END d[356]
  PIN d[357]
    DIRECTION INPUT ;
    USE SIGNAL ;
    PORT
      LAYER M5 ;
        RECT  32.16 0 32.184 0.192 ;
    END
  END d[357]
  PIN d[358]
    DIRECTION INPUT ;
    USE SIGNAL ;
    PORT
      LAYER M3 ;
        RECT  32.256 0 32.274 0.144 ;
    END
  END d[358]
  PIN d[359]
    DIRECTION INPUT ;
    USE SIGNAL ;
    PORT
      LAYER M5 ;
        RECT  32.304 0 32.328 0.192 ;
    END
  END d[359]
  PIN d[35]
    DIRECTION INPUT ;
    USE SIGNAL ;
    PORT
      LAYER M5 ;
        RECT  8.976 0 9 0.192 ;
    END
  END d[35]
  PIN d[360]
    DIRECTION INPUT ;
    USE SIGNAL ;
    PORT
      LAYER M3 ;
        RECT  32.4 0 32.418 0.144 ;
    END
  END d[360]
  PIN d[361]
    DIRECTION INPUT ;
    USE SIGNAL ;
    PORT
      LAYER M5 ;
        RECT  32.448 0 32.472 0.192 ;
    END
  END d[361]
  PIN d[362]
    DIRECTION INPUT ;
    USE SIGNAL ;
    PORT
      LAYER M3 ;
        RECT  32.544 0 32.562 0.144 ;
    END
  END d[362]
  PIN d[363]
    DIRECTION INPUT ;
    USE SIGNAL ;
    PORT
      LAYER M5 ;
        RECT  32.592 0 32.616 0.192 ;
    END
  END d[363]
  PIN d[364]
    DIRECTION INPUT ;
    USE SIGNAL ;
    PORT
      LAYER M3 ;
        RECT  32.688 0 32.706 0.144 ;
    END
  END d[364]
  PIN d[365]
    DIRECTION INPUT ;
    USE SIGNAL ;
    PORT
      LAYER M5 ;
        RECT  32.736 0 32.76 0.192 ;
    END
  END d[365]
  PIN d[366]
    DIRECTION INPUT ;
    USE SIGNAL ;
    PORT
      LAYER M3 ;
        RECT  32.832 0 32.85 0.144 ;
    END
  END d[366]
  PIN d[367]
    DIRECTION INPUT ;
    USE SIGNAL ;
    PORT
      LAYER M5 ;
        RECT  32.88 0 32.904 0.192 ;
    END
  END d[367]
  PIN d[368]
    DIRECTION INPUT ;
    USE SIGNAL ;
    PORT
      LAYER M3 ;
        RECT  32.976 0 32.994 0.144 ;
    END
  END d[368]
  PIN d[369]
    DIRECTION INPUT ;
    USE SIGNAL ;
    PORT
      LAYER M5 ;
        RECT  33.024 0 33.048 0.192 ;
    END
  END d[369]
  PIN d[36]
    DIRECTION INPUT ;
    USE SIGNAL ;
    PORT
      LAYER M3 ;
        RECT  9.072 0 9.09 0.144 ;
    END
  END d[36]
  PIN d[370]
    DIRECTION INPUT ;
    USE SIGNAL ;
    PORT
      LAYER M3 ;
        RECT  33.12 0 33.138 0.144 ;
    END
  END d[370]
  PIN d[371]
    DIRECTION INPUT ;
    USE SIGNAL ;
    PORT
      LAYER M5 ;
        RECT  33.168 0 33.192 0.192 ;
    END
  END d[371]
  PIN d[372]
    DIRECTION INPUT ;
    USE SIGNAL ;
    PORT
      LAYER M3 ;
        RECT  33.264 0 33.282 0.144 ;
    END
  END d[372]
  PIN d[373]
    DIRECTION INPUT ;
    USE SIGNAL ;
    PORT
      LAYER M5 ;
        RECT  33.312 0 33.336 0.192 ;
    END
  END d[373]
  PIN d[374]
    DIRECTION INPUT ;
    USE SIGNAL ;
    PORT
      LAYER M3 ;
        RECT  33.408 0 33.426 0.144 ;
    END
  END d[374]
  PIN d[375]
    DIRECTION INPUT ;
    USE SIGNAL ;
    PORT
      LAYER M5 ;
        RECT  33.456 0 33.48 0.192 ;
    END
  END d[375]
  PIN d[376]
    DIRECTION INPUT ;
    USE SIGNAL ;
    PORT
      LAYER M3 ;
        RECT  33.552 0 33.57 0.144 ;
    END
  END d[376]
  PIN d[377]
    DIRECTION INPUT ;
    USE SIGNAL ;
    PORT
      LAYER M5 ;
        RECT  33.6 0 33.624 0.192 ;
    END
  END d[377]
  PIN d[378]
    DIRECTION INPUT ;
    USE SIGNAL ;
    PORT
      LAYER M3 ;
        RECT  33.696 0 33.714 0.144 ;
    END
  END d[378]
  PIN d[379]
    DIRECTION INPUT ;
    USE SIGNAL ;
    PORT
      LAYER M5 ;
        RECT  33.744 0 33.768 0.192 ;
    END
  END d[379]
  PIN d[37]
    DIRECTION INPUT ;
    USE SIGNAL ;
    PORT
      LAYER M5 ;
        RECT  9.12 0 9.144 0.192 ;
    END
  END d[37]
  PIN d[380]
    DIRECTION INPUT ;
    USE SIGNAL ;
    PORT
      LAYER M3 ;
        RECT  33.84 0 33.858 0.144 ;
    END
  END d[380]
  PIN d[381]
    DIRECTION INPUT ;
    USE SIGNAL ;
    PORT
      LAYER M5 ;
        RECT  33.888 0 33.912 0.192 ;
    END
  END d[381]
  PIN d[382]
    DIRECTION INPUT ;
    USE SIGNAL ;
    PORT
      LAYER M3 ;
        RECT  33.984 0 34.002 0.144 ;
    END
  END d[382]
  PIN d[383]
    DIRECTION INPUT ;
    USE SIGNAL ;
    PORT
      LAYER M5 ;
        RECT  34.032 0 34.056 0.192 ;
    END
  END d[383]
  PIN d[384]
    DIRECTION INPUT ;
    USE SIGNAL ;
    PORT
      LAYER M3 ;
        RECT  34.128 0 34.146 0.144 ;
    END
  END d[384]
  PIN d[385]
    DIRECTION INPUT ;
    USE SIGNAL ;
    PORT
      LAYER M5 ;
        RECT  34.176 0 34.2 0.192 ;
    END
  END d[385]
  PIN d[386]
    DIRECTION INPUT ;
    USE SIGNAL ;
    PORT
      LAYER M3 ;
        RECT  34.272 0 34.29 0.144 ;
    END
  END d[386]
  PIN d[387]
    DIRECTION INPUT ;
    USE SIGNAL ;
    PORT
      LAYER M5 ;
        RECT  34.32 0 34.344 0.192 ;
    END
  END d[387]
  PIN d[388]
    DIRECTION INPUT ;
    USE SIGNAL ;
    PORT
      LAYER M3 ;
        RECT  34.416 0 34.434 0.144 ;
    END
  END d[388]
  PIN d[389]
    DIRECTION INPUT ;
    USE SIGNAL ;
    PORT
      LAYER M5 ;
        RECT  34.464 0 34.488 0.192 ;
    END
  END d[389]
  PIN d[38]
    DIRECTION INPUT ;
    USE SIGNAL ;
    PORT
      LAYER M3 ;
        RECT  9.216 0 9.234 0.144 ;
    END
  END d[38]
  PIN d[390]
    DIRECTION INPUT ;
    USE SIGNAL ;
    PORT
      LAYER M3 ;
        RECT  34.56 0 34.578 0.144 ;
    END
  END d[390]
  PIN d[391]
    DIRECTION INPUT ;
    USE SIGNAL ;
    PORT
      LAYER M5 ;
        RECT  34.608 0 34.632 0.192 ;
    END
  END d[391]
  PIN d[392]
    DIRECTION INPUT ;
    USE SIGNAL ;
    PORT
      LAYER M3 ;
        RECT  34.704 0 34.722 0.144 ;
    END
  END d[392]
  PIN d[393]
    DIRECTION INPUT ;
    USE SIGNAL ;
    PORT
      LAYER M5 ;
        RECT  34.752 0 34.776 0.192 ;
    END
  END d[393]
  PIN d[394]
    DIRECTION INPUT ;
    USE SIGNAL ;
    PORT
      LAYER M3 ;
        RECT  34.848 0 34.866 0.144 ;
    END
  END d[394]
  PIN d[395]
    DIRECTION INPUT ;
    USE SIGNAL ;
    PORT
      LAYER M5 ;
        RECT  34.896 0 34.92 0.192 ;
    END
  END d[395]
  PIN d[396]
    DIRECTION INPUT ;
    USE SIGNAL ;
    PORT
      LAYER M3 ;
        RECT  34.992 0 35.01 0.144 ;
    END
  END d[396]
  PIN d[397]
    DIRECTION INPUT ;
    USE SIGNAL ;
    PORT
      LAYER M5 ;
        RECT  35.04 0 35.064 0.192 ;
    END
  END d[397]
  PIN d[398]
    DIRECTION INPUT ;
    USE SIGNAL ;
    PORT
      LAYER M3 ;
        RECT  35.136 0 35.154 0.144 ;
    END
  END d[398]
  PIN d[399]
    DIRECTION INPUT ;
    USE SIGNAL ;
    PORT
      LAYER M5 ;
        RECT  35.184 0 35.208 0.192 ;
    END
  END d[399]
  PIN d[39]
    DIRECTION INPUT ;
    USE SIGNAL ;
    PORT
      LAYER M5 ;
        RECT  9.264 0 9.288 0.192 ;
    END
  END d[39]
  PIN d[3]
    DIRECTION INPUT ;
    USE SIGNAL ;
    PORT
      LAYER M5 ;
        RECT  6.672 0 6.696 0.192 ;
    END
  END d[3]
  PIN d[400]
    DIRECTION INPUT ;
    USE SIGNAL ;
    PORT
      LAYER M3 ;
        RECT  35.28 0 35.298 0.144 ;
    END
  END d[400]
  PIN d[401]
    DIRECTION INPUT ;
    USE SIGNAL ;
    PORT
      LAYER M5 ;
        RECT  35.328 0 35.352 0.192 ;
    END
  END d[401]
  PIN d[402]
    DIRECTION INPUT ;
    USE SIGNAL ;
    PORT
      LAYER M3 ;
        RECT  35.424 0 35.442 0.144 ;
    END
  END d[402]
  PIN d[403]
    DIRECTION INPUT ;
    USE SIGNAL ;
    PORT
      LAYER M5 ;
        RECT  35.472 0 35.496 0.192 ;
    END
  END d[403]
  PIN d[404]
    DIRECTION INPUT ;
    USE SIGNAL ;
    PORT
      LAYER M3 ;
        RECT  35.568 0 35.586 0.144 ;
    END
  END d[404]
  PIN d[405]
    DIRECTION INPUT ;
    USE SIGNAL ;
    PORT
      LAYER M5 ;
        RECT  35.616 0 35.64 0.192 ;
    END
  END d[405]
  PIN d[406]
    DIRECTION INPUT ;
    USE SIGNAL ;
    PORT
      LAYER M3 ;
        RECT  35.712 0 35.73 0.144 ;
    END
  END d[406]
  PIN d[407]
    DIRECTION INPUT ;
    USE SIGNAL ;
    PORT
      LAYER M5 ;
        RECT  35.76 0 35.784 0.192 ;
    END
  END d[407]
  PIN d[40]
    DIRECTION INPUT ;
    USE SIGNAL ;
    PORT
      LAYER M3 ;
        RECT  9.36 0 9.378 0.144 ;
    END
  END d[40]
  PIN d[41]
    DIRECTION INPUT ;
    USE SIGNAL ;
    PORT
      LAYER M5 ;
        RECT  9.408 0 9.432 0.192 ;
    END
  END d[41]
  PIN d[42]
    DIRECTION INPUT ;
    USE SIGNAL ;
    PORT
      LAYER M3 ;
        RECT  9.504 0 9.522 0.144 ;
    END
  END d[42]
  PIN d[43]
    DIRECTION INPUT ;
    USE SIGNAL ;
    PORT
      LAYER M5 ;
        RECT  9.552 0 9.576 0.192 ;
    END
  END d[43]
  PIN d[44]
    DIRECTION INPUT ;
    USE SIGNAL ;
    PORT
      LAYER M3 ;
        RECT  9.648 0 9.666 0.144 ;
    END
  END d[44]
  PIN d[45]
    DIRECTION INPUT ;
    USE SIGNAL ;
    PORT
      LAYER M5 ;
        RECT  9.696 0 9.72 0.192 ;
    END
  END d[45]
  PIN d[46]
    DIRECTION INPUT ;
    USE SIGNAL ;
    PORT
      LAYER M3 ;
        RECT  9.792 0 9.81 0.144 ;
    END
  END d[46]
  PIN d[47]
    DIRECTION INPUT ;
    USE SIGNAL ;
    PORT
      LAYER M5 ;
        RECT  9.84 0 9.864 0.192 ;
    END
  END d[47]
  PIN d[48]
    DIRECTION INPUT ;
    USE SIGNAL ;
    PORT
      LAYER M3 ;
        RECT  9.936 0 9.954 0.144 ;
    END
  END d[48]
  PIN d[49]
    DIRECTION INPUT ;
    USE SIGNAL ;
    PORT
      LAYER M5 ;
        RECT  9.984 0 10.008 0.192 ;
    END
  END d[49]
  PIN d[4]
    DIRECTION INPUT ;
    USE SIGNAL ;
    PORT
      LAYER M3 ;
        RECT  6.768 0 6.786 0.144 ;
    END
  END d[4]
  PIN d[50]
    DIRECTION INPUT ;
    USE SIGNAL ;
    PORT
      LAYER M3 ;
        RECT  10.08 0 10.098 0.144 ;
    END
  END d[50]
  PIN d[51]
    DIRECTION INPUT ;
    USE SIGNAL ;
    PORT
      LAYER M5 ;
        RECT  10.128 0 10.152 0.192 ;
    END
  END d[51]
  PIN d[52]
    DIRECTION INPUT ;
    USE SIGNAL ;
    PORT
      LAYER M3 ;
        RECT  10.224 0 10.242 0.144 ;
    END
  END d[52]
  PIN d[53]
    DIRECTION INPUT ;
    USE SIGNAL ;
    PORT
      LAYER M5 ;
        RECT  10.272 0 10.296 0.192 ;
    END
  END d[53]
  PIN d[54]
    DIRECTION INPUT ;
    USE SIGNAL ;
    PORT
      LAYER M3 ;
        RECT  10.368 0 10.386 0.144 ;
    END
  END d[54]
  PIN d[55]
    DIRECTION INPUT ;
    USE SIGNAL ;
    PORT
      LAYER M5 ;
        RECT  10.416 0 10.44 0.192 ;
    END
  END d[55]
  PIN d[56]
    DIRECTION INPUT ;
    USE SIGNAL ;
    PORT
      LAYER M3 ;
        RECT  10.512 0 10.53 0.144 ;
    END
  END d[56]
  PIN d[57]
    DIRECTION INPUT ;
    USE SIGNAL ;
    PORT
      LAYER M5 ;
        RECT  10.56 0 10.584 0.192 ;
    END
  END d[57]
  PIN d[58]
    DIRECTION INPUT ;
    USE SIGNAL ;
    PORT
      LAYER M3 ;
        RECT  10.656 0 10.674 0.144 ;
    END
  END d[58]
  PIN d[59]
    DIRECTION INPUT ;
    USE SIGNAL ;
    PORT
      LAYER M5 ;
        RECT  10.704 0 10.728 0.192 ;
    END
  END d[59]
  PIN d[5]
    DIRECTION INPUT ;
    USE SIGNAL ;
    PORT
      LAYER M5 ;
        RECT  6.816 0 6.84 0.192 ;
    END
  END d[5]
  PIN d[60]
    DIRECTION INPUT ;
    USE SIGNAL ;
    PORT
      LAYER M3 ;
        RECT  10.8 0 10.818 0.144 ;
    END
  END d[60]
  PIN d[61]
    DIRECTION INPUT ;
    USE SIGNAL ;
    PORT
      LAYER M5 ;
        RECT  10.848 0 10.872 0.192 ;
    END
  END d[61]
  PIN d[62]
    DIRECTION INPUT ;
    USE SIGNAL ;
    PORT
      LAYER M3 ;
        RECT  10.944 0 10.962 0.144 ;
    END
  END d[62]
  PIN d[63]
    DIRECTION INPUT ;
    USE SIGNAL ;
    PORT
      LAYER M5 ;
        RECT  10.992 0 11.016 0.192 ;
    END
  END d[63]
  PIN d[64]
    DIRECTION INPUT ;
    USE SIGNAL ;
    PORT
      LAYER M3 ;
        RECT  11.088 0 11.106 0.144 ;
    END
  END d[64]
  PIN d[65]
    DIRECTION INPUT ;
    USE SIGNAL ;
    PORT
      LAYER M5 ;
        RECT  11.136 0 11.16 0.192 ;
    END
  END d[65]
  PIN d[66]
    DIRECTION INPUT ;
    USE SIGNAL ;
    PORT
      LAYER M3 ;
        RECT  11.232 0 11.25 0.144 ;
    END
  END d[66]
  PIN d[67]
    DIRECTION INPUT ;
    USE SIGNAL ;
    PORT
      LAYER M5 ;
        RECT  11.28 0 11.304 0.192 ;
    END
  END d[67]
  PIN d[68]
    DIRECTION INPUT ;
    USE SIGNAL ;
    PORT
      LAYER M3 ;
        RECT  11.376 0 11.394 0.144 ;
    END
  END d[68]
  PIN d[69]
    DIRECTION INPUT ;
    USE SIGNAL ;
    PORT
      LAYER M5 ;
        RECT  11.424 0 11.448 0.192 ;
    END
  END d[69]
  PIN d[6]
    DIRECTION INPUT ;
    USE SIGNAL ;
    PORT
      LAYER M3 ;
        RECT  6.912 0 6.93 0.144 ;
    END
  END d[6]
  PIN d[70]
    DIRECTION INPUT ;
    USE SIGNAL ;
    PORT
      LAYER M3 ;
        RECT  11.52 0 11.538 0.144 ;
    END
  END d[70]
  PIN d[71]
    DIRECTION INPUT ;
    USE SIGNAL ;
    PORT
      LAYER M5 ;
        RECT  11.568 0 11.592 0.192 ;
    END
  END d[71]
  PIN d[72]
    DIRECTION INPUT ;
    USE SIGNAL ;
    PORT
      LAYER M3 ;
        RECT  11.664 0 11.682 0.144 ;
    END
  END d[72]
  PIN d[73]
    DIRECTION INPUT ;
    USE SIGNAL ;
    PORT
      LAYER M5 ;
        RECT  11.712 0 11.736 0.192 ;
    END
  END d[73]
  PIN d[74]
    DIRECTION INPUT ;
    USE SIGNAL ;
    PORT
      LAYER M3 ;
        RECT  11.808 0 11.826 0.144 ;
    END
  END d[74]
  PIN d[75]
    DIRECTION INPUT ;
    USE SIGNAL ;
    PORT
      LAYER M5 ;
        RECT  11.856 0 11.88 0.192 ;
    END
  END d[75]
  PIN d[76]
    DIRECTION INPUT ;
    USE SIGNAL ;
    PORT
      LAYER M3 ;
        RECT  11.952 0 11.97 0.144 ;
    END
  END d[76]
  PIN d[77]
    DIRECTION INPUT ;
    USE SIGNAL ;
    PORT
      LAYER M5 ;
        RECT  12 0 12.024 0.192 ;
    END
  END d[77]
  PIN d[78]
    DIRECTION INPUT ;
    USE SIGNAL ;
    PORT
      LAYER M3 ;
        RECT  12.096 0 12.114 0.144 ;
    END
  END d[78]
  PIN d[79]
    DIRECTION INPUT ;
    USE SIGNAL ;
    PORT
      LAYER M5 ;
        RECT  12.144 0 12.168 0.192 ;
    END
  END d[79]
  PIN d[7]
    DIRECTION INPUT ;
    USE SIGNAL ;
    PORT
      LAYER M5 ;
        RECT  6.96 0 6.984 0.192 ;
    END
  END d[7]
  PIN d[80]
    DIRECTION INPUT ;
    USE SIGNAL ;
    PORT
      LAYER M3 ;
        RECT  12.24 0 12.258 0.144 ;
    END
  END d[80]
  PIN d[81]
    DIRECTION INPUT ;
    USE SIGNAL ;
    PORT
      LAYER M5 ;
        RECT  12.288 0 12.312 0.192 ;
    END
  END d[81]
  PIN d[82]
    DIRECTION INPUT ;
    USE SIGNAL ;
    PORT
      LAYER M3 ;
        RECT  12.384 0 12.402 0.144 ;
    END
  END d[82]
  PIN d[83]
    DIRECTION INPUT ;
    USE SIGNAL ;
    PORT
      LAYER M5 ;
        RECT  12.432 0 12.456 0.192 ;
    END
  END d[83]
  PIN d[84]
    DIRECTION INPUT ;
    USE SIGNAL ;
    PORT
      LAYER M3 ;
        RECT  12.528 0 12.546 0.144 ;
    END
  END d[84]
  PIN d[85]
    DIRECTION INPUT ;
    USE SIGNAL ;
    PORT
      LAYER M5 ;
        RECT  12.576 0 12.6 0.192 ;
    END
  END d[85]
  PIN d[86]
    DIRECTION INPUT ;
    USE SIGNAL ;
    PORT
      LAYER M3 ;
        RECT  12.672 0 12.69 0.144 ;
    END
  END d[86]
  PIN d[87]
    DIRECTION INPUT ;
    USE SIGNAL ;
    PORT
      LAYER M5 ;
        RECT  12.72 0 12.744 0.192 ;
    END
  END d[87]
  PIN d[88]
    DIRECTION INPUT ;
    USE SIGNAL ;
    PORT
      LAYER M3 ;
        RECT  12.816 0 12.834 0.144 ;
    END
  END d[88]
  PIN d[89]
    DIRECTION INPUT ;
    USE SIGNAL ;
    PORT
      LAYER M5 ;
        RECT  12.864 0 12.888 0.192 ;
    END
  END d[89]
  PIN d[8]
    DIRECTION INPUT ;
    USE SIGNAL ;
    PORT
      LAYER M3 ;
        RECT  7.056 0 7.074 0.144 ;
    END
  END d[8]
  PIN d[90]
    DIRECTION INPUT ;
    USE SIGNAL ;
    PORT
      LAYER M3 ;
        RECT  12.96 0 12.978 0.144 ;
    END
  END d[90]
  PIN d[91]
    DIRECTION INPUT ;
    USE SIGNAL ;
    PORT
      LAYER M5 ;
        RECT  13.008 0 13.032 0.192 ;
    END
  END d[91]
  PIN d[92]
    DIRECTION INPUT ;
    USE SIGNAL ;
    PORT
      LAYER M3 ;
        RECT  13.104 0 13.122 0.144 ;
    END
  END d[92]
  PIN d[93]
    DIRECTION INPUT ;
    USE SIGNAL ;
    PORT
      LAYER M5 ;
        RECT  13.152 0 13.176 0.192 ;
    END
  END d[93]
  PIN d[94]
    DIRECTION INPUT ;
    USE SIGNAL ;
    PORT
      LAYER M3 ;
        RECT  13.248 0 13.266 0.144 ;
    END
  END d[94]
  PIN d[95]
    DIRECTION INPUT ;
    USE SIGNAL ;
    PORT
      LAYER M5 ;
        RECT  13.296 0 13.32 0.192 ;
    END
  END d[95]
  PIN d[96]
    DIRECTION INPUT ;
    USE SIGNAL ;
    PORT
      LAYER M3 ;
        RECT  13.392 0 13.41 0.144 ;
    END
  END d[96]
  PIN d[97]
    DIRECTION INPUT ;
    USE SIGNAL ;
    PORT
      LAYER M5 ;
        RECT  13.44 0 13.464 0.192 ;
    END
  END d[97]
  PIN d[98]
    DIRECTION INPUT ;
    USE SIGNAL ;
    PORT
      LAYER M3 ;
        RECT  13.536 0 13.554 0.144 ;
    END
  END d[98]
  PIN d[99]
    DIRECTION INPUT ;
    USE SIGNAL ;
    PORT
      LAYER M5 ;
        RECT  13.584 0 13.608 0.192 ;
    END
  END d[99]
  PIN d[9]
    DIRECTION INPUT ;
    USE SIGNAL ;
    PORT
      LAYER M5 ;
        RECT  7.104 0 7.128 0.192 ;
    END
  END d[9]
  PIN q[0]
    DIRECTION OUTPUT ;
    USE SIGNAL ;
    PORT
      LAYER M3 ;
        RECT  6.48 34.416 6.498 34.56 ;
    END
  END q[0]
  PIN q[100]
    DIRECTION OUTPUT ;
    USE SIGNAL ;
    PORT
      LAYER M3 ;
        RECT  13.68 34.416 13.698 34.56 ;
    END
  END q[100]
  PIN q[101]
    DIRECTION OUTPUT ;
    USE SIGNAL ;
    PORT
      LAYER M5 ;
        RECT  13.728 34.368 13.752 34.56 ;
    END
  END q[101]
  PIN q[102]
    DIRECTION OUTPUT ;
    USE SIGNAL ;
    PORT
      LAYER M3 ;
        RECT  13.824 34.416 13.842 34.56 ;
    END
  END q[102]
  PIN q[103]
    DIRECTION OUTPUT ;
    USE SIGNAL ;
    PORT
      LAYER M5 ;
        RECT  13.872 34.368 13.896 34.56 ;
    END
  END q[103]
  PIN q[104]
    DIRECTION OUTPUT ;
    USE SIGNAL ;
    PORT
      LAYER M3 ;
        RECT  13.968 34.416 13.986 34.56 ;
    END
  END q[104]
  PIN q[105]
    DIRECTION OUTPUT ;
    USE SIGNAL ;
    PORT
      LAYER M5 ;
        RECT  14.016 34.368 14.04 34.56 ;
    END
  END q[105]
  PIN q[106]
    DIRECTION OUTPUT ;
    USE SIGNAL ;
    PORT
      LAYER M3 ;
        RECT  14.112 34.416 14.13 34.56 ;
    END
  END q[106]
  PIN q[107]
    DIRECTION OUTPUT ;
    USE SIGNAL ;
    PORT
      LAYER M5 ;
        RECT  14.16 34.368 14.184 34.56 ;
    END
  END q[107]
  PIN q[108]
    DIRECTION OUTPUT ;
    USE SIGNAL ;
    PORT
      LAYER M3 ;
        RECT  14.256 34.416 14.274 34.56 ;
    END
  END q[108]
  PIN q[109]
    DIRECTION OUTPUT ;
    USE SIGNAL ;
    PORT
      LAYER M5 ;
        RECT  14.304 34.368 14.328 34.56 ;
    END
  END q[109]
  PIN q[10]
    DIRECTION OUTPUT ;
    USE SIGNAL ;
    PORT
      LAYER M3 ;
        RECT  7.2 34.416 7.218 34.56 ;
    END
  END q[10]
  PIN q[110]
    DIRECTION OUTPUT ;
    USE SIGNAL ;
    PORT
      LAYER M3 ;
        RECT  14.4 34.416 14.418 34.56 ;
    END
  END q[110]
  PIN q[111]
    DIRECTION OUTPUT ;
    USE SIGNAL ;
    PORT
      LAYER M5 ;
        RECT  14.448 34.368 14.472 34.56 ;
    END
  END q[111]
  PIN q[112]
    DIRECTION OUTPUT ;
    USE SIGNAL ;
    PORT
      LAYER M3 ;
        RECT  14.544 34.416 14.562 34.56 ;
    END
  END q[112]
  PIN q[113]
    DIRECTION OUTPUT ;
    USE SIGNAL ;
    PORT
      LAYER M5 ;
        RECT  14.592 34.368 14.616 34.56 ;
    END
  END q[113]
  PIN q[114]
    DIRECTION OUTPUT ;
    USE SIGNAL ;
    PORT
      LAYER M3 ;
        RECT  14.688 34.416 14.706 34.56 ;
    END
  END q[114]
  PIN q[115]
    DIRECTION OUTPUT ;
    USE SIGNAL ;
    PORT
      LAYER M5 ;
        RECT  14.736 34.368 14.76 34.56 ;
    END
  END q[115]
  PIN q[116]
    DIRECTION OUTPUT ;
    USE SIGNAL ;
    PORT
      LAYER M3 ;
        RECT  14.832 34.416 14.85 34.56 ;
    END
  END q[116]
  PIN q[117]
    DIRECTION OUTPUT ;
    USE SIGNAL ;
    PORT
      LAYER M5 ;
        RECT  14.88 34.368 14.904 34.56 ;
    END
  END q[117]
  PIN q[118]
    DIRECTION OUTPUT ;
    USE SIGNAL ;
    PORT
      LAYER M3 ;
        RECT  14.976 34.416 14.994 34.56 ;
    END
  END q[118]
  PIN q[119]
    DIRECTION OUTPUT ;
    USE SIGNAL ;
    PORT
      LAYER M5 ;
        RECT  15.024 34.368 15.048 34.56 ;
    END
  END q[119]
  PIN q[11]
    DIRECTION OUTPUT ;
    USE SIGNAL ;
    PORT
      LAYER M5 ;
        RECT  7.248 34.368 7.272 34.56 ;
    END
  END q[11]
  PIN q[120]
    DIRECTION OUTPUT ;
    USE SIGNAL ;
    PORT
      LAYER M3 ;
        RECT  15.12 34.416 15.138 34.56 ;
    END
  END q[120]
  PIN q[121]
    DIRECTION OUTPUT ;
    USE SIGNAL ;
    PORT
      LAYER M5 ;
        RECT  15.168 34.368 15.192 34.56 ;
    END
  END q[121]
  PIN q[122]
    DIRECTION OUTPUT ;
    USE SIGNAL ;
    PORT
      LAYER M3 ;
        RECT  15.264 34.416 15.282 34.56 ;
    END
  END q[122]
  PIN q[123]
    DIRECTION OUTPUT ;
    USE SIGNAL ;
    PORT
      LAYER M5 ;
        RECT  15.312 34.368 15.336 34.56 ;
    END
  END q[123]
  PIN q[124]
    DIRECTION OUTPUT ;
    USE SIGNAL ;
    PORT
      LAYER M3 ;
        RECT  15.408 34.416 15.426 34.56 ;
    END
  END q[124]
  PIN q[125]
    DIRECTION OUTPUT ;
    USE SIGNAL ;
    PORT
      LAYER M5 ;
        RECT  15.456 34.368 15.48 34.56 ;
    END
  END q[125]
  PIN q[126]
    DIRECTION OUTPUT ;
    USE SIGNAL ;
    PORT
      LAYER M3 ;
        RECT  15.552 34.416 15.57 34.56 ;
    END
  END q[126]
  PIN q[127]
    DIRECTION OUTPUT ;
    USE SIGNAL ;
    PORT
      LAYER M5 ;
        RECT  15.6 34.368 15.624 34.56 ;
    END
  END q[127]
  PIN q[128]
    DIRECTION OUTPUT ;
    USE SIGNAL ;
    PORT
      LAYER M3 ;
        RECT  15.696 34.416 15.714 34.56 ;
    END
  END q[128]
  PIN q[129]
    DIRECTION OUTPUT ;
    USE SIGNAL ;
    PORT
      LAYER M5 ;
        RECT  15.744 34.368 15.768 34.56 ;
    END
  END q[129]
  PIN q[12]
    DIRECTION OUTPUT ;
    USE SIGNAL ;
    PORT
      LAYER M3 ;
        RECT  7.344 34.416 7.362 34.56 ;
    END
  END q[12]
  PIN q[130]
    DIRECTION OUTPUT ;
    USE SIGNAL ;
    PORT
      LAYER M3 ;
        RECT  15.84 34.416 15.858 34.56 ;
    END
  END q[130]
  PIN q[131]
    DIRECTION OUTPUT ;
    USE SIGNAL ;
    PORT
      LAYER M5 ;
        RECT  15.888 34.368 15.912 34.56 ;
    END
  END q[131]
  PIN q[132]
    DIRECTION OUTPUT ;
    USE SIGNAL ;
    PORT
      LAYER M3 ;
        RECT  15.984 34.416 16.002 34.56 ;
    END
  END q[132]
  PIN q[133]
    DIRECTION OUTPUT ;
    USE SIGNAL ;
    PORT
      LAYER M5 ;
        RECT  16.032 34.368 16.056 34.56 ;
    END
  END q[133]
  PIN q[134]
    DIRECTION OUTPUT ;
    USE SIGNAL ;
    PORT
      LAYER M3 ;
        RECT  16.128 34.416 16.146 34.56 ;
    END
  END q[134]
  PIN q[135]
    DIRECTION OUTPUT ;
    USE SIGNAL ;
    PORT
      LAYER M5 ;
        RECT  16.176 34.368 16.2 34.56 ;
    END
  END q[135]
  PIN q[136]
    DIRECTION OUTPUT ;
    USE SIGNAL ;
    PORT
      LAYER M3 ;
        RECT  16.272 34.416 16.29 34.56 ;
    END
  END q[136]
  PIN q[137]
    DIRECTION OUTPUT ;
    USE SIGNAL ;
    PORT
      LAYER M5 ;
        RECT  16.32 34.368 16.344 34.56 ;
    END
  END q[137]
  PIN q[138]
    DIRECTION OUTPUT ;
    USE SIGNAL ;
    PORT
      LAYER M3 ;
        RECT  16.416 34.416 16.434 34.56 ;
    END
  END q[138]
  PIN q[139]
    DIRECTION OUTPUT ;
    USE SIGNAL ;
    PORT
      LAYER M5 ;
        RECT  16.464 34.368 16.488 34.56 ;
    END
  END q[139]
  PIN q[13]
    DIRECTION OUTPUT ;
    USE SIGNAL ;
    PORT
      LAYER M5 ;
        RECT  7.392 34.368 7.416 34.56 ;
    END
  END q[13]
  PIN q[140]
    DIRECTION OUTPUT ;
    USE SIGNAL ;
    PORT
      LAYER M3 ;
        RECT  16.56 34.416 16.578 34.56 ;
    END
  END q[140]
  PIN q[141]
    DIRECTION OUTPUT ;
    USE SIGNAL ;
    PORT
      LAYER M5 ;
        RECT  16.608 34.368 16.632 34.56 ;
    END
  END q[141]
  PIN q[142]
    DIRECTION OUTPUT ;
    USE SIGNAL ;
    PORT
      LAYER M3 ;
        RECT  16.704 34.416 16.722 34.56 ;
    END
  END q[142]
  PIN q[143]
    DIRECTION OUTPUT ;
    USE SIGNAL ;
    PORT
      LAYER M5 ;
        RECT  16.752 34.368 16.776 34.56 ;
    END
  END q[143]
  PIN q[144]
    DIRECTION OUTPUT ;
    USE SIGNAL ;
    PORT
      LAYER M3 ;
        RECT  16.848 34.416 16.866 34.56 ;
    END
  END q[144]
  PIN q[145]
    DIRECTION OUTPUT ;
    USE SIGNAL ;
    PORT
      LAYER M5 ;
        RECT  16.896 34.368 16.92 34.56 ;
    END
  END q[145]
  PIN q[146]
    DIRECTION OUTPUT ;
    USE SIGNAL ;
    PORT
      LAYER M3 ;
        RECT  16.992 34.416 17.01 34.56 ;
    END
  END q[146]
  PIN q[147]
    DIRECTION OUTPUT ;
    USE SIGNAL ;
    PORT
      LAYER M5 ;
        RECT  17.04 34.368 17.064 34.56 ;
    END
  END q[147]
  PIN q[148]
    DIRECTION OUTPUT ;
    USE SIGNAL ;
    PORT
      LAYER M3 ;
        RECT  17.136 34.416 17.154 34.56 ;
    END
  END q[148]
  PIN q[149]
    DIRECTION OUTPUT ;
    USE SIGNAL ;
    PORT
      LAYER M5 ;
        RECT  17.184 34.368 17.208 34.56 ;
    END
  END q[149]
  PIN q[14]
    DIRECTION OUTPUT ;
    USE SIGNAL ;
    PORT
      LAYER M3 ;
        RECT  7.488 34.416 7.506 34.56 ;
    END
  END q[14]
  PIN q[150]
    DIRECTION OUTPUT ;
    USE SIGNAL ;
    PORT
      LAYER M3 ;
        RECT  17.28 34.416 17.298 34.56 ;
    END
  END q[150]
  PIN q[151]
    DIRECTION OUTPUT ;
    USE SIGNAL ;
    PORT
      LAYER M5 ;
        RECT  17.328 34.368 17.352 34.56 ;
    END
  END q[151]
  PIN q[152]
    DIRECTION OUTPUT ;
    USE SIGNAL ;
    PORT
      LAYER M3 ;
        RECT  17.424 34.416 17.442 34.56 ;
    END
  END q[152]
  PIN q[153]
    DIRECTION OUTPUT ;
    USE SIGNAL ;
    PORT
      LAYER M5 ;
        RECT  17.472 34.368 17.496 34.56 ;
    END
  END q[153]
  PIN q[154]
    DIRECTION OUTPUT ;
    USE SIGNAL ;
    PORT
      LAYER M3 ;
        RECT  17.568 34.416 17.586 34.56 ;
    END
  END q[154]
  PIN q[155]
    DIRECTION OUTPUT ;
    USE SIGNAL ;
    PORT
      LAYER M5 ;
        RECT  17.616 34.368 17.64 34.56 ;
    END
  END q[155]
  PIN q[156]
    DIRECTION OUTPUT ;
    USE SIGNAL ;
    PORT
      LAYER M3 ;
        RECT  17.712 34.416 17.73 34.56 ;
    END
  END q[156]
  PIN q[157]
    DIRECTION OUTPUT ;
    USE SIGNAL ;
    PORT
      LAYER M5 ;
        RECT  17.76 34.368 17.784 34.56 ;
    END
  END q[157]
  PIN q[158]
    DIRECTION OUTPUT ;
    USE SIGNAL ;
    PORT
      LAYER M3 ;
        RECT  17.856 34.416 17.874 34.56 ;
    END
  END q[158]
  PIN q[159]
    DIRECTION OUTPUT ;
    USE SIGNAL ;
    PORT
      LAYER M5 ;
        RECT  17.904 34.368 17.928 34.56 ;
    END
  END q[159]
  PIN q[15]
    DIRECTION OUTPUT ;
    USE SIGNAL ;
    PORT
      LAYER M5 ;
        RECT  7.536 34.368 7.56 34.56 ;
    END
  END q[15]
  PIN q[160]
    DIRECTION OUTPUT ;
    USE SIGNAL ;
    PORT
      LAYER M3 ;
        RECT  18 34.416 18.018 34.56 ;
    END
  END q[160]
  PIN q[161]
    DIRECTION OUTPUT ;
    USE SIGNAL ;
    PORT
      LAYER M5 ;
        RECT  18.048 34.368 18.072 34.56 ;
    END
  END q[161]
  PIN q[162]
    DIRECTION OUTPUT ;
    USE SIGNAL ;
    PORT
      LAYER M3 ;
        RECT  18.144 34.416 18.162 34.56 ;
    END
  END q[162]
  PIN q[163]
    DIRECTION OUTPUT ;
    USE SIGNAL ;
    PORT
      LAYER M5 ;
        RECT  18.192 34.368 18.216 34.56 ;
    END
  END q[163]
  PIN q[164]
    DIRECTION OUTPUT ;
    USE SIGNAL ;
    PORT
      LAYER M3 ;
        RECT  18.288 34.416 18.306 34.56 ;
    END
  END q[164]
  PIN q[165]
    DIRECTION OUTPUT ;
    USE SIGNAL ;
    PORT
      LAYER M5 ;
        RECT  18.336 34.368 18.36 34.56 ;
    END
  END q[165]
  PIN q[166]
    DIRECTION OUTPUT ;
    USE SIGNAL ;
    PORT
      LAYER M3 ;
        RECT  18.432 34.416 18.45 34.56 ;
    END
  END q[166]
  PIN q[167]
    DIRECTION OUTPUT ;
    USE SIGNAL ;
    PORT
      LAYER M5 ;
        RECT  18.48 34.368 18.504 34.56 ;
    END
  END q[167]
  PIN q[168]
    DIRECTION OUTPUT ;
    USE SIGNAL ;
    PORT
      LAYER M3 ;
        RECT  18.576 34.416 18.594 34.56 ;
    END
  END q[168]
  PIN q[169]
    DIRECTION OUTPUT ;
    USE SIGNAL ;
    PORT
      LAYER M5 ;
        RECT  18.624 34.368 18.648 34.56 ;
    END
  END q[169]
  PIN q[16]
    DIRECTION OUTPUT ;
    USE SIGNAL ;
    PORT
      LAYER M3 ;
        RECT  7.632 34.416 7.65 34.56 ;
    END
  END q[16]
  PIN q[170]
    DIRECTION OUTPUT ;
    USE SIGNAL ;
    PORT
      LAYER M3 ;
        RECT  18.72 34.416 18.738 34.56 ;
    END
  END q[170]
  PIN q[171]
    DIRECTION OUTPUT ;
    USE SIGNAL ;
    PORT
      LAYER M5 ;
        RECT  18.768 34.368 18.792 34.56 ;
    END
  END q[171]
  PIN q[172]
    DIRECTION OUTPUT ;
    USE SIGNAL ;
    PORT
      LAYER M3 ;
        RECT  18.864 34.416 18.882 34.56 ;
    END
  END q[172]
  PIN q[173]
    DIRECTION OUTPUT ;
    USE SIGNAL ;
    PORT
      LAYER M5 ;
        RECT  18.912 34.368 18.936 34.56 ;
    END
  END q[173]
  PIN q[174]
    DIRECTION OUTPUT ;
    USE SIGNAL ;
    PORT
      LAYER M3 ;
        RECT  19.008 34.416 19.026 34.56 ;
    END
  END q[174]
  PIN q[175]
    DIRECTION OUTPUT ;
    USE SIGNAL ;
    PORT
      LAYER M5 ;
        RECT  19.056 34.368 19.08 34.56 ;
    END
  END q[175]
  PIN q[176]
    DIRECTION OUTPUT ;
    USE SIGNAL ;
    PORT
      LAYER M3 ;
        RECT  19.152 34.416 19.17 34.56 ;
    END
  END q[176]
  PIN q[177]
    DIRECTION OUTPUT ;
    USE SIGNAL ;
    PORT
      LAYER M5 ;
        RECT  19.2 34.368 19.224 34.56 ;
    END
  END q[177]
  PIN q[178]
    DIRECTION OUTPUT ;
    USE SIGNAL ;
    PORT
      LAYER M3 ;
        RECT  19.296 34.416 19.314 34.56 ;
    END
  END q[178]
  PIN q[179]
    DIRECTION OUTPUT ;
    USE SIGNAL ;
    PORT
      LAYER M5 ;
        RECT  19.344 34.368 19.368 34.56 ;
    END
  END q[179]
  PIN q[17]
    DIRECTION OUTPUT ;
    USE SIGNAL ;
    PORT
      LAYER M5 ;
        RECT  7.68 34.368 7.704 34.56 ;
    END
  END q[17]
  PIN q[180]
    DIRECTION OUTPUT ;
    USE SIGNAL ;
    PORT
      LAYER M3 ;
        RECT  19.44 34.416 19.458 34.56 ;
    END
  END q[180]
  PIN q[181]
    DIRECTION OUTPUT ;
    USE SIGNAL ;
    PORT
      LAYER M5 ;
        RECT  19.488 34.368 19.512 34.56 ;
    END
  END q[181]
  PIN q[182]
    DIRECTION OUTPUT ;
    USE SIGNAL ;
    PORT
      LAYER M3 ;
        RECT  19.584 34.416 19.602 34.56 ;
    END
  END q[182]
  PIN q[183]
    DIRECTION OUTPUT ;
    USE SIGNAL ;
    PORT
      LAYER M5 ;
        RECT  19.632 34.368 19.656 34.56 ;
    END
  END q[183]
  PIN q[184]
    DIRECTION OUTPUT ;
    USE SIGNAL ;
    PORT
      LAYER M3 ;
        RECT  19.728 34.416 19.746 34.56 ;
    END
  END q[184]
  PIN q[185]
    DIRECTION OUTPUT ;
    USE SIGNAL ;
    PORT
      LAYER M5 ;
        RECT  19.776 34.368 19.8 34.56 ;
    END
  END q[185]
  PIN q[186]
    DIRECTION OUTPUT ;
    USE SIGNAL ;
    PORT
      LAYER M3 ;
        RECT  19.872 34.416 19.89 34.56 ;
    END
  END q[186]
  PIN q[187]
    DIRECTION OUTPUT ;
    USE SIGNAL ;
    PORT
      LAYER M5 ;
        RECT  19.92 34.368 19.944 34.56 ;
    END
  END q[187]
  PIN q[188]
    DIRECTION OUTPUT ;
    USE SIGNAL ;
    PORT
      LAYER M3 ;
        RECT  20.016 34.416 20.034 34.56 ;
    END
  END q[188]
  PIN q[189]
    DIRECTION OUTPUT ;
    USE SIGNAL ;
    PORT
      LAYER M5 ;
        RECT  20.064 34.368 20.088 34.56 ;
    END
  END q[189]
  PIN q[18]
    DIRECTION OUTPUT ;
    USE SIGNAL ;
    PORT
      LAYER M3 ;
        RECT  7.776 34.416 7.794 34.56 ;
    END
  END q[18]
  PIN q[190]
    DIRECTION OUTPUT ;
    USE SIGNAL ;
    PORT
      LAYER M3 ;
        RECT  20.16 34.416 20.178 34.56 ;
    END
  END q[190]
  PIN q[191]
    DIRECTION OUTPUT ;
    USE SIGNAL ;
    PORT
      LAYER M5 ;
        RECT  20.208 34.368 20.232 34.56 ;
    END
  END q[191]
  PIN q[192]
    DIRECTION OUTPUT ;
    USE SIGNAL ;
    PORT
      LAYER M3 ;
        RECT  20.304 34.416 20.322 34.56 ;
    END
  END q[192]
  PIN q[193]
    DIRECTION OUTPUT ;
    USE SIGNAL ;
    PORT
      LAYER M5 ;
        RECT  20.352 34.368 20.376 34.56 ;
    END
  END q[193]
  PIN q[194]
    DIRECTION OUTPUT ;
    USE SIGNAL ;
    PORT
      LAYER M3 ;
        RECT  20.448 34.416 20.466 34.56 ;
    END
  END q[194]
  PIN q[195]
    DIRECTION OUTPUT ;
    USE SIGNAL ;
    PORT
      LAYER M5 ;
        RECT  20.496 34.368 20.52 34.56 ;
    END
  END q[195]
  PIN q[196]
    DIRECTION OUTPUT ;
    USE SIGNAL ;
    PORT
      LAYER M3 ;
        RECT  20.592 34.416 20.61 34.56 ;
    END
  END q[196]
  PIN q[197]
    DIRECTION OUTPUT ;
    USE SIGNAL ;
    PORT
      LAYER M5 ;
        RECT  20.64 34.368 20.664 34.56 ;
    END
  END q[197]
  PIN q[198]
    DIRECTION OUTPUT ;
    USE SIGNAL ;
    PORT
      LAYER M3 ;
        RECT  20.736 34.416 20.754 34.56 ;
    END
  END q[198]
  PIN q[199]
    DIRECTION OUTPUT ;
    USE SIGNAL ;
    PORT
      LAYER M5 ;
        RECT  20.784 34.368 20.808 34.56 ;
    END
  END q[199]
  PIN q[19]
    DIRECTION OUTPUT ;
    USE SIGNAL ;
    PORT
      LAYER M5 ;
        RECT  7.824 34.368 7.848 34.56 ;
    END
  END q[19]
  PIN q[1]
    DIRECTION OUTPUT ;
    USE SIGNAL ;
    PORT
      LAYER M5 ;
        RECT  6.528 34.368 6.552 34.56 ;
    END
  END q[1]
  PIN q[200]
    DIRECTION OUTPUT ;
    USE SIGNAL ;
    PORT
      LAYER M3 ;
        RECT  20.88 34.416 20.898 34.56 ;
    END
  END q[200]
  PIN q[201]
    DIRECTION OUTPUT ;
    USE SIGNAL ;
    PORT
      LAYER M5 ;
        RECT  20.928 34.368 20.952 34.56 ;
    END
  END q[201]
  PIN q[202]
    DIRECTION OUTPUT ;
    USE SIGNAL ;
    PORT
      LAYER M3 ;
        RECT  21.024 34.416 21.042 34.56 ;
    END
  END q[202]
  PIN q[203]
    DIRECTION OUTPUT ;
    USE SIGNAL ;
    PORT
      LAYER M5 ;
        RECT  21.072 34.368 21.096 34.56 ;
    END
  END q[203]
  PIN q[204]
    DIRECTION OUTPUT ;
    USE SIGNAL ;
    PORT
      LAYER M3 ;
        RECT  21.168 34.416 21.186 34.56 ;
    END
  END q[204]
  PIN q[205]
    DIRECTION OUTPUT ;
    USE SIGNAL ;
    PORT
      LAYER M5 ;
        RECT  21.216 34.368 21.24 34.56 ;
    END
  END q[205]
  PIN q[206]
    DIRECTION OUTPUT ;
    USE SIGNAL ;
    PORT
      LAYER M3 ;
        RECT  21.312 34.416 21.33 34.56 ;
    END
  END q[206]
  PIN q[207]
    DIRECTION OUTPUT ;
    USE SIGNAL ;
    PORT
      LAYER M5 ;
        RECT  21.36 34.368 21.384 34.56 ;
    END
  END q[207]
  PIN q[208]
    DIRECTION OUTPUT ;
    USE SIGNAL ;
    PORT
      LAYER M3 ;
        RECT  21.456 34.416 21.474 34.56 ;
    END
  END q[208]
  PIN q[209]
    DIRECTION OUTPUT ;
    USE SIGNAL ;
    PORT
      LAYER M5 ;
        RECT  21.504 34.368 21.528 34.56 ;
    END
  END q[209]
  PIN q[20]
    DIRECTION OUTPUT ;
    USE SIGNAL ;
    PORT
      LAYER M3 ;
        RECT  7.92 34.416 7.938 34.56 ;
    END
  END q[20]
  PIN q[210]
    DIRECTION OUTPUT ;
    USE SIGNAL ;
    PORT
      LAYER M3 ;
        RECT  21.6 34.416 21.618 34.56 ;
    END
  END q[210]
  PIN q[211]
    DIRECTION OUTPUT ;
    USE SIGNAL ;
    PORT
      LAYER M5 ;
        RECT  21.648 34.368 21.672 34.56 ;
    END
  END q[211]
  PIN q[212]
    DIRECTION OUTPUT ;
    USE SIGNAL ;
    PORT
      LAYER M3 ;
        RECT  21.744 34.416 21.762 34.56 ;
    END
  END q[212]
  PIN q[213]
    DIRECTION OUTPUT ;
    USE SIGNAL ;
    PORT
      LAYER M5 ;
        RECT  21.792 34.368 21.816 34.56 ;
    END
  END q[213]
  PIN q[214]
    DIRECTION OUTPUT ;
    USE SIGNAL ;
    PORT
      LAYER M3 ;
        RECT  21.888 34.416 21.906 34.56 ;
    END
  END q[214]
  PIN q[215]
    DIRECTION OUTPUT ;
    USE SIGNAL ;
    PORT
      LAYER M5 ;
        RECT  21.936 34.368 21.96 34.56 ;
    END
  END q[215]
  PIN q[216]
    DIRECTION OUTPUT ;
    USE SIGNAL ;
    PORT
      LAYER M3 ;
        RECT  22.032 34.416 22.05 34.56 ;
    END
  END q[216]
  PIN q[217]
    DIRECTION OUTPUT ;
    USE SIGNAL ;
    PORT
      LAYER M5 ;
        RECT  22.08 34.368 22.104 34.56 ;
    END
  END q[217]
  PIN q[218]
    DIRECTION OUTPUT ;
    USE SIGNAL ;
    PORT
      LAYER M3 ;
        RECT  22.176 34.416 22.194 34.56 ;
    END
  END q[218]
  PIN q[219]
    DIRECTION OUTPUT ;
    USE SIGNAL ;
    PORT
      LAYER M5 ;
        RECT  22.224 34.368 22.248 34.56 ;
    END
  END q[219]
  PIN q[21]
    DIRECTION OUTPUT ;
    USE SIGNAL ;
    PORT
      LAYER M5 ;
        RECT  7.968 34.368 7.992 34.56 ;
    END
  END q[21]
  PIN q[220]
    DIRECTION OUTPUT ;
    USE SIGNAL ;
    PORT
      LAYER M3 ;
        RECT  22.32 34.416 22.338 34.56 ;
    END
  END q[220]
  PIN q[221]
    DIRECTION OUTPUT ;
    USE SIGNAL ;
    PORT
      LAYER M5 ;
        RECT  22.368 34.368 22.392 34.56 ;
    END
  END q[221]
  PIN q[222]
    DIRECTION OUTPUT ;
    USE SIGNAL ;
    PORT
      LAYER M3 ;
        RECT  22.464 34.416 22.482 34.56 ;
    END
  END q[222]
  PIN q[223]
    DIRECTION OUTPUT ;
    USE SIGNAL ;
    PORT
      LAYER M5 ;
        RECT  22.512 34.368 22.536 34.56 ;
    END
  END q[223]
  PIN q[224]
    DIRECTION OUTPUT ;
    USE SIGNAL ;
    PORT
      LAYER M3 ;
        RECT  22.608 34.416 22.626 34.56 ;
    END
  END q[224]
  PIN q[225]
    DIRECTION OUTPUT ;
    USE SIGNAL ;
    PORT
      LAYER M5 ;
        RECT  22.656 34.368 22.68 34.56 ;
    END
  END q[225]
  PIN q[226]
    DIRECTION OUTPUT ;
    USE SIGNAL ;
    PORT
      LAYER M3 ;
        RECT  22.752 34.416 22.77 34.56 ;
    END
  END q[226]
  PIN q[227]
    DIRECTION OUTPUT ;
    USE SIGNAL ;
    PORT
      LAYER M5 ;
        RECT  22.8 34.368 22.824 34.56 ;
    END
  END q[227]
  PIN q[228]
    DIRECTION OUTPUT ;
    USE SIGNAL ;
    PORT
      LAYER M3 ;
        RECT  22.896 34.416 22.914 34.56 ;
    END
  END q[228]
  PIN q[229]
    DIRECTION OUTPUT ;
    USE SIGNAL ;
    PORT
      LAYER M5 ;
        RECT  22.944 34.368 22.968 34.56 ;
    END
  END q[229]
  PIN q[22]
    DIRECTION OUTPUT ;
    USE SIGNAL ;
    PORT
      LAYER M3 ;
        RECT  8.064 34.416 8.082 34.56 ;
    END
  END q[22]
  PIN q[230]
    DIRECTION OUTPUT ;
    USE SIGNAL ;
    PORT
      LAYER M3 ;
        RECT  23.04 34.416 23.058 34.56 ;
    END
  END q[230]
  PIN q[231]
    DIRECTION OUTPUT ;
    USE SIGNAL ;
    PORT
      LAYER M5 ;
        RECT  23.088 34.368 23.112 34.56 ;
    END
  END q[231]
  PIN q[232]
    DIRECTION OUTPUT ;
    USE SIGNAL ;
    PORT
      LAYER M3 ;
        RECT  23.184 34.416 23.202 34.56 ;
    END
  END q[232]
  PIN q[233]
    DIRECTION OUTPUT ;
    USE SIGNAL ;
    PORT
      LAYER M5 ;
        RECT  23.232 34.368 23.256 34.56 ;
    END
  END q[233]
  PIN q[234]
    DIRECTION OUTPUT ;
    USE SIGNAL ;
    PORT
      LAYER M3 ;
        RECT  23.328 34.416 23.346 34.56 ;
    END
  END q[234]
  PIN q[235]
    DIRECTION OUTPUT ;
    USE SIGNAL ;
    PORT
      LAYER M5 ;
        RECT  23.376 34.368 23.4 34.56 ;
    END
  END q[235]
  PIN q[236]
    DIRECTION OUTPUT ;
    USE SIGNAL ;
    PORT
      LAYER M3 ;
        RECT  23.472 34.416 23.49 34.56 ;
    END
  END q[236]
  PIN q[237]
    DIRECTION OUTPUT ;
    USE SIGNAL ;
    PORT
      LAYER M5 ;
        RECT  23.52 34.368 23.544 34.56 ;
    END
  END q[237]
  PIN q[238]
    DIRECTION OUTPUT ;
    USE SIGNAL ;
    PORT
      LAYER M3 ;
        RECT  23.616 34.416 23.634 34.56 ;
    END
  END q[238]
  PIN q[239]
    DIRECTION OUTPUT ;
    USE SIGNAL ;
    PORT
      LAYER M5 ;
        RECT  23.664 34.368 23.688 34.56 ;
    END
  END q[239]
  PIN q[23]
    DIRECTION OUTPUT ;
    USE SIGNAL ;
    PORT
      LAYER M5 ;
        RECT  8.112 34.368 8.136 34.56 ;
    END
  END q[23]
  PIN q[240]
    DIRECTION OUTPUT ;
    USE SIGNAL ;
    PORT
      LAYER M3 ;
        RECT  23.76 34.416 23.778 34.56 ;
    END
  END q[240]
  PIN q[241]
    DIRECTION OUTPUT ;
    USE SIGNAL ;
    PORT
      LAYER M5 ;
        RECT  23.808 34.368 23.832 34.56 ;
    END
  END q[241]
  PIN q[242]
    DIRECTION OUTPUT ;
    USE SIGNAL ;
    PORT
      LAYER M3 ;
        RECT  23.904 34.416 23.922 34.56 ;
    END
  END q[242]
  PIN q[243]
    DIRECTION OUTPUT ;
    USE SIGNAL ;
    PORT
      LAYER M5 ;
        RECT  23.952 34.368 23.976 34.56 ;
    END
  END q[243]
  PIN q[244]
    DIRECTION OUTPUT ;
    USE SIGNAL ;
    PORT
      LAYER M3 ;
        RECT  24.048 34.416 24.066 34.56 ;
    END
  END q[244]
  PIN q[245]
    DIRECTION OUTPUT ;
    USE SIGNAL ;
    PORT
      LAYER M5 ;
        RECT  24.096 34.368 24.12 34.56 ;
    END
  END q[245]
  PIN q[246]
    DIRECTION OUTPUT ;
    USE SIGNAL ;
    PORT
      LAYER M3 ;
        RECT  24.192 34.416 24.21 34.56 ;
    END
  END q[246]
  PIN q[247]
    DIRECTION OUTPUT ;
    USE SIGNAL ;
    PORT
      LAYER M5 ;
        RECT  24.24 34.368 24.264 34.56 ;
    END
  END q[247]
  PIN q[248]
    DIRECTION OUTPUT ;
    USE SIGNAL ;
    PORT
      LAYER M3 ;
        RECT  24.336 34.416 24.354 34.56 ;
    END
  END q[248]
  PIN q[249]
    DIRECTION OUTPUT ;
    USE SIGNAL ;
    PORT
      LAYER M5 ;
        RECT  24.384 34.368 24.408 34.56 ;
    END
  END q[249]
  PIN q[24]
    DIRECTION OUTPUT ;
    USE SIGNAL ;
    PORT
      LAYER M3 ;
        RECT  8.208 34.416 8.226 34.56 ;
    END
  END q[24]
  PIN q[250]
    DIRECTION OUTPUT ;
    USE SIGNAL ;
    PORT
      LAYER M3 ;
        RECT  24.48 34.416 24.498 34.56 ;
    END
  END q[250]
  PIN q[251]
    DIRECTION OUTPUT ;
    USE SIGNAL ;
    PORT
      LAYER M5 ;
        RECT  24.528 34.368 24.552 34.56 ;
    END
  END q[251]
  PIN q[252]
    DIRECTION OUTPUT ;
    USE SIGNAL ;
    PORT
      LAYER M3 ;
        RECT  24.624 34.416 24.642 34.56 ;
    END
  END q[252]
  PIN q[253]
    DIRECTION OUTPUT ;
    USE SIGNAL ;
    PORT
      LAYER M5 ;
        RECT  24.672 34.368 24.696 34.56 ;
    END
  END q[253]
  PIN q[254]
    DIRECTION OUTPUT ;
    USE SIGNAL ;
    PORT
      LAYER M3 ;
        RECT  24.768 34.416 24.786 34.56 ;
    END
  END q[254]
  PIN q[255]
    DIRECTION OUTPUT ;
    USE SIGNAL ;
    PORT
      LAYER M5 ;
        RECT  24.816 34.368 24.84 34.56 ;
    END
  END q[255]
  PIN q[256]
    DIRECTION OUTPUT ;
    USE SIGNAL ;
    PORT
      LAYER M3 ;
        RECT  24.912 34.416 24.93 34.56 ;
    END
  END q[256]
  PIN q[257]
    DIRECTION OUTPUT ;
    USE SIGNAL ;
    PORT
      LAYER M5 ;
        RECT  24.96 34.368 24.984 34.56 ;
    END
  END q[257]
  PIN q[258]
    DIRECTION OUTPUT ;
    USE SIGNAL ;
    PORT
      LAYER M3 ;
        RECT  25.056 34.416 25.074 34.56 ;
    END
  END q[258]
  PIN q[259]
    DIRECTION OUTPUT ;
    USE SIGNAL ;
    PORT
      LAYER M5 ;
        RECT  25.104 34.368 25.128 34.56 ;
    END
  END q[259]
  PIN q[25]
    DIRECTION OUTPUT ;
    USE SIGNAL ;
    PORT
      LAYER M5 ;
        RECT  8.256 34.368 8.28 34.56 ;
    END
  END q[25]
  PIN q[260]
    DIRECTION OUTPUT ;
    USE SIGNAL ;
    PORT
      LAYER M3 ;
        RECT  25.2 34.416 25.218 34.56 ;
    END
  END q[260]
  PIN q[261]
    DIRECTION OUTPUT ;
    USE SIGNAL ;
    PORT
      LAYER M5 ;
        RECT  25.248 34.368 25.272 34.56 ;
    END
  END q[261]
  PIN q[262]
    DIRECTION OUTPUT ;
    USE SIGNAL ;
    PORT
      LAYER M3 ;
        RECT  25.344 34.416 25.362 34.56 ;
    END
  END q[262]
  PIN q[263]
    DIRECTION OUTPUT ;
    USE SIGNAL ;
    PORT
      LAYER M5 ;
        RECT  25.392 34.368 25.416 34.56 ;
    END
  END q[263]
  PIN q[264]
    DIRECTION OUTPUT ;
    USE SIGNAL ;
    PORT
      LAYER M3 ;
        RECT  25.488 34.416 25.506 34.56 ;
    END
  END q[264]
  PIN q[265]
    DIRECTION OUTPUT ;
    USE SIGNAL ;
    PORT
      LAYER M5 ;
        RECT  25.536 34.368 25.56 34.56 ;
    END
  END q[265]
  PIN q[266]
    DIRECTION OUTPUT ;
    USE SIGNAL ;
    PORT
      LAYER M3 ;
        RECT  25.632 34.416 25.65 34.56 ;
    END
  END q[266]
  PIN q[267]
    DIRECTION OUTPUT ;
    USE SIGNAL ;
    PORT
      LAYER M5 ;
        RECT  25.68 34.368 25.704 34.56 ;
    END
  END q[267]
  PIN q[268]
    DIRECTION OUTPUT ;
    USE SIGNAL ;
    PORT
      LAYER M3 ;
        RECT  25.776 34.416 25.794 34.56 ;
    END
  END q[268]
  PIN q[269]
    DIRECTION OUTPUT ;
    USE SIGNAL ;
    PORT
      LAYER M5 ;
        RECT  25.824 34.368 25.848 34.56 ;
    END
  END q[269]
  PIN q[26]
    DIRECTION OUTPUT ;
    USE SIGNAL ;
    PORT
      LAYER M3 ;
        RECT  8.352 34.416 8.37 34.56 ;
    END
  END q[26]
  PIN q[270]
    DIRECTION OUTPUT ;
    USE SIGNAL ;
    PORT
      LAYER M3 ;
        RECT  25.92 34.416 25.938 34.56 ;
    END
  END q[270]
  PIN q[271]
    DIRECTION OUTPUT ;
    USE SIGNAL ;
    PORT
      LAYER M5 ;
        RECT  25.968 34.368 25.992 34.56 ;
    END
  END q[271]
  PIN q[272]
    DIRECTION OUTPUT ;
    USE SIGNAL ;
    PORT
      LAYER M3 ;
        RECT  26.064 34.416 26.082 34.56 ;
    END
  END q[272]
  PIN q[273]
    DIRECTION OUTPUT ;
    USE SIGNAL ;
    PORT
      LAYER M5 ;
        RECT  26.112 34.368 26.136 34.56 ;
    END
  END q[273]
  PIN q[274]
    DIRECTION OUTPUT ;
    USE SIGNAL ;
    PORT
      LAYER M3 ;
        RECT  26.208 34.416 26.226 34.56 ;
    END
  END q[274]
  PIN q[275]
    DIRECTION OUTPUT ;
    USE SIGNAL ;
    PORT
      LAYER M5 ;
        RECT  26.256 34.368 26.28 34.56 ;
    END
  END q[275]
  PIN q[276]
    DIRECTION OUTPUT ;
    USE SIGNAL ;
    PORT
      LAYER M3 ;
        RECT  26.352 34.416 26.37 34.56 ;
    END
  END q[276]
  PIN q[277]
    DIRECTION OUTPUT ;
    USE SIGNAL ;
    PORT
      LAYER M5 ;
        RECT  26.4 34.368 26.424 34.56 ;
    END
  END q[277]
  PIN q[278]
    DIRECTION OUTPUT ;
    USE SIGNAL ;
    PORT
      LAYER M3 ;
        RECT  26.496 34.416 26.514 34.56 ;
    END
  END q[278]
  PIN q[279]
    DIRECTION OUTPUT ;
    USE SIGNAL ;
    PORT
      LAYER M5 ;
        RECT  26.544 34.368 26.568 34.56 ;
    END
  END q[279]
  PIN q[27]
    DIRECTION OUTPUT ;
    USE SIGNAL ;
    PORT
      LAYER M5 ;
        RECT  8.4 34.368 8.424 34.56 ;
    END
  END q[27]
  PIN q[280]
    DIRECTION OUTPUT ;
    USE SIGNAL ;
    PORT
      LAYER M3 ;
        RECT  26.64 34.416 26.658 34.56 ;
    END
  END q[280]
  PIN q[281]
    DIRECTION OUTPUT ;
    USE SIGNAL ;
    PORT
      LAYER M5 ;
        RECT  26.688 34.368 26.712 34.56 ;
    END
  END q[281]
  PIN q[282]
    DIRECTION OUTPUT ;
    USE SIGNAL ;
    PORT
      LAYER M3 ;
        RECT  26.784 34.416 26.802 34.56 ;
    END
  END q[282]
  PIN q[283]
    DIRECTION OUTPUT ;
    USE SIGNAL ;
    PORT
      LAYER M5 ;
        RECT  26.832 34.368 26.856 34.56 ;
    END
  END q[283]
  PIN q[284]
    DIRECTION OUTPUT ;
    USE SIGNAL ;
    PORT
      LAYER M3 ;
        RECT  26.928 34.416 26.946 34.56 ;
    END
  END q[284]
  PIN q[285]
    DIRECTION OUTPUT ;
    USE SIGNAL ;
    PORT
      LAYER M5 ;
        RECT  26.976 34.368 27 34.56 ;
    END
  END q[285]
  PIN q[286]
    DIRECTION OUTPUT ;
    USE SIGNAL ;
    PORT
      LAYER M3 ;
        RECT  27.072 34.416 27.09 34.56 ;
    END
  END q[286]
  PIN q[287]
    DIRECTION OUTPUT ;
    USE SIGNAL ;
    PORT
      LAYER M5 ;
        RECT  27.12 34.368 27.144 34.56 ;
    END
  END q[287]
  PIN q[288]
    DIRECTION OUTPUT ;
    USE SIGNAL ;
    PORT
      LAYER M3 ;
        RECT  27.216 34.416 27.234 34.56 ;
    END
  END q[288]
  PIN q[289]
    DIRECTION OUTPUT ;
    USE SIGNAL ;
    PORT
      LAYER M5 ;
        RECT  27.264 34.368 27.288 34.56 ;
    END
  END q[289]
  PIN q[28]
    DIRECTION OUTPUT ;
    USE SIGNAL ;
    PORT
      LAYER M3 ;
        RECT  8.496 34.416 8.514 34.56 ;
    END
  END q[28]
  PIN q[290]
    DIRECTION OUTPUT ;
    USE SIGNAL ;
    PORT
      LAYER M3 ;
        RECT  27.36 34.416 27.378 34.56 ;
    END
  END q[290]
  PIN q[291]
    DIRECTION OUTPUT ;
    USE SIGNAL ;
    PORT
      LAYER M5 ;
        RECT  27.408 34.368 27.432 34.56 ;
    END
  END q[291]
  PIN q[292]
    DIRECTION OUTPUT ;
    USE SIGNAL ;
    PORT
      LAYER M3 ;
        RECT  27.504 34.416 27.522 34.56 ;
    END
  END q[292]
  PIN q[293]
    DIRECTION OUTPUT ;
    USE SIGNAL ;
    PORT
      LAYER M5 ;
        RECT  27.552 34.368 27.576 34.56 ;
    END
  END q[293]
  PIN q[294]
    DIRECTION OUTPUT ;
    USE SIGNAL ;
    PORT
      LAYER M3 ;
        RECT  27.648 34.416 27.666 34.56 ;
    END
  END q[294]
  PIN q[295]
    DIRECTION OUTPUT ;
    USE SIGNAL ;
    PORT
      LAYER M5 ;
        RECT  27.696 34.368 27.72 34.56 ;
    END
  END q[295]
  PIN q[296]
    DIRECTION OUTPUT ;
    USE SIGNAL ;
    PORT
      LAYER M3 ;
        RECT  27.792 34.416 27.81 34.56 ;
    END
  END q[296]
  PIN q[297]
    DIRECTION OUTPUT ;
    USE SIGNAL ;
    PORT
      LAYER M5 ;
        RECT  27.84 34.368 27.864 34.56 ;
    END
  END q[297]
  PIN q[298]
    DIRECTION OUTPUT ;
    USE SIGNAL ;
    PORT
      LAYER M3 ;
        RECT  27.936 34.416 27.954 34.56 ;
    END
  END q[298]
  PIN q[299]
    DIRECTION OUTPUT ;
    USE SIGNAL ;
    PORT
      LAYER M5 ;
        RECT  27.984 34.368 28.008 34.56 ;
    END
  END q[299]
  PIN q[29]
    DIRECTION OUTPUT ;
    USE SIGNAL ;
    PORT
      LAYER M5 ;
        RECT  8.544 34.368 8.568 34.56 ;
    END
  END q[29]
  PIN q[2]
    DIRECTION OUTPUT ;
    USE SIGNAL ;
    PORT
      LAYER M3 ;
        RECT  6.624 34.416 6.642 34.56 ;
    END
  END q[2]
  PIN q[300]
    DIRECTION OUTPUT ;
    USE SIGNAL ;
    PORT
      LAYER M3 ;
        RECT  28.08 34.416 28.098 34.56 ;
    END
  END q[300]
  PIN q[301]
    DIRECTION OUTPUT ;
    USE SIGNAL ;
    PORT
      LAYER M5 ;
        RECT  28.128 34.368 28.152 34.56 ;
    END
  END q[301]
  PIN q[302]
    DIRECTION OUTPUT ;
    USE SIGNAL ;
    PORT
      LAYER M3 ;
        RECT  28.224 34.416 28.242 34.56 ;
    END
  END q[302]
  PIN q[303]
    DIRECTION OUTPUT ;
    USE SIGNAL ;
    PORT
      LAYER M5 ;
        RECT  28.272 34.368 28.296 34.56 ;
    END
  END q[303]
  PIN q[304]
    DIRECTION OUTPUT ;
    USE SIGNAL ;
    PORT
      LAYER M3 ;
        RECT  28.368 34.416 28.386 34.56 ;
    END
  END q[304]
  PIN q[305]
    DIRECTION OUTPUT ;
    USE SIGNAL ;
    PORT
      LAYER M5 ;
        RECT  28.416 34.368 28.44 34.56 ;
    END
  END q[305]
  PIN q[306]
    DIRECTION OUTPUT ;
    USE SIGNAL ;
    PORT
      LAYER M3 ;
        RECT  28.512 34.416 28.53 34.56 ;
    END
  END q[306]
  PIN q[307]
    DIRECTION OUTPUT ;
    USE SIGNAL ;
    PORT
      LAYER M5 ;
        RECT  28.56 34.368 28.584 34.56 ;
    END
  END q[307]
  PIN q[308]
    DIRECTION OUTPUT ;
    USE SIGNAL ;
    PORT
      LAYER M3 ;
        RECT  28.656 34.416 28.674 34.56 ;
    END
  END q[308]
  PIN q[309]
    DIRECTION OUTPUT ;
    USE SIGNAL ;
    PORT
      LAYER M5 ;
        RECT  28.704 34.368 28.728 34.56 ;
    END
  END q[309]
  PIN q[30]
    DIRECTION OUTPUT ;
    USE SIGNAL ;
    PORT
      LAYER M3 ;
        RECT  8.64 34.416 8.658 34.56 ;
    END
  END q[30]
  PIN q[310]
    DIRECTION OUTPUT ;
    USE SIGNAL ;
    PORT
      LAYER M3 ;
        RECT  28.8 34.416 28.818 34.56 ;
    END
  END q[310]
  PIN q[311]
    DIRECTION OUTPUT ;
    USE SIGNAL ;
    PORT
      LAYER M5 ;
        RECT  28.848 34.368 28.872 34.56 ;
    END
  END q[311]
  PIN q[312]
    DIRECTION OUTPUT ;
    USE SIGNAL ;
    PORT
      LAYER M3 ;
        RECT  28.944 34.416 28.962 34.56 ;
    END
  END q[312]
  PIN q[313]
    DIRECTION OUTPUT ;
    USE SIGNAL ;
    PORT
      LAYER M5 ;
        RECT  28.992 34.368 29.016 34.56 ;
    END
  END q[313]
  PIN q[314]
    DIRECTION OUTPUT ;
    USE SIGNAL ;
    PORT
      LAYER M3 ;
        RECT  29.088 34.416 29.106 34.56 ;
    END
  END q[314]
  PIN q[315]
    DIRECTION OUTPUT ;
    USE SIGNAL ;
    PORT
      LAYER M5 ;
        RECT  29.136 34.368 29.16 34.56 ;
    END
  END q[315]
  PIN q[316]
    DIRECTION OUTPUT ;
    USE SIGNAL ;
    PORT
      LAYER M3 ;
        RECT  29.232 34.416 29.25 34.56 ;
    END
  END q[316]
  PIN q[317]
    DIRECTION OUTPUT ;
    USE SIGNAL ;
    PORT
      LAYER M5 ;
        RECT  29.28 34.368 29.304 34.56 ;
    END
  END q[317]
  PIN q[318]
    DIRECTION OUTPUT ;
    USE SIGNAL ;
    PORT
      LAYER M3 ;
        RECT  29.376 34.416 29.394 34.56 ;
    END
  END q[318]
  PIN q[319]
    DIRECTION OUTPUT ;
    USE SIGNAL ;
    PORT
      LAYER M5 ;
        RECT  29.424 34.368 29.448 34.56 ;
    END
  END q[319]
  PIN q[31]
    DIRECTION OUTPUT ;
    USE SIGNAL ;
    PORT
      LAYER M5 ;
        RECT  8.688 34.368 8.712 34.56 ;
    END
  END q[31]
  PIN q[320]
    DIRECTION OUTPUT ;
    USE SIGNAL ;
    PORT
      LAYER M3 ;
        RECT  29.52 34.416 29.538 34.56 ;
    END
  END q[320]
  PIN q[321]
    DIRECTION OUTPUT ;
    USE SIGNAL ;
    PORT
      LAYER M5 ;
        RECT  29.568 34.368 29.592 34.56 ;
    END
  END q[321]
  PIN q[322]
    DIRECTION OUTPUT ;
    USE SIGNAL ;
    PORT
      LAYER M3 ;
        RECT  29.664 34.416 29.682 34.56 ;
    END
  END q[322]
  PIN q[323]
    DIRECTION OUTPUT ;
    USE SIGNAL ;
    PORT
      LAYER M5 ;
        RECT  29.712 34.368 29.736 34.56 ;
    END
  END q[323]
  PIN q[324]
    DIRECTION OUTPUT ;
    USE SIGNAL ;
    PORT
      LAYER M3 ;
        RECT  29.808 34.416 29.826 34.56 ;
    END
  END q[324]
  PIN q[325]
    DIRECTION OUTPUT ;
    USE SIGNAL ;
    PORT
      LAYER M5 ;
        RECT  29.856 34.368 29.88 34.56 ;
    END
  END q[325]
  PIN q[326]
    DIRECTION OUTPUT ;
    USE SIGNAL ;
    PORT
      LAYER M3 ;
        RECT  29.952 34.416 29.97 34.56 ;
    END
  END q[326]
  PIN q[327]
    DIRECTION OUTPUT ;
    USE SIGNAL ;
    PORT
      LAYER M5 ;
        RECT  30 34.368 30.024 34.56 ;
    END
  END q[327]
  PIN q[328]
    DIRECTION OUTPUT ;
    USE SIGNAL ;
    PORT
      LAYER M3 ;
        RECT  30.096 34.416 30.114 34.56 ;
    END
  END q[328]
  PIN q[329]
    DIRECTION OUTPUT ;
    USE SIGNAL ;
    PORT
      LAYER M5 ;
        RECT  30.144 34.368 30.168 34.56 ;
    END
  END q[329]
  PIN q[32]
    DIRECTION OUTPUT ;
    USE SIGNAL ;
    PORT
      LAYER M3 ;
        RECT  8.784 34.416 8.802 34.56 ;
    END
  END q[32]
  PIN q[330]
    DIRECTION OUTPUT ;
    USE SIGNAL ;
    PORT
      LAYER M3 ;
        RECT  30.24 34.416 30.258 34.56 ;
    END
  END q[330]
  PIN q[331]
    DIRECTION OUTPUT ;
    USE SIGNAL ;
    PORT
      LAYER M5 ;
        RECT  30.288 34.368 30.312 34.56 ;
    END
  END q[331]
  PIN q[332]
    DIRECTION OUTPUT ;
    USE SIGNAL ;
    PORT
      LAYER M3 ;
        RECT  30.384 34.416 30.402 34.56 ;
    END
  END q[332]
  PIN q[333]
    DIRECTION OUTPUT ;
    USE SIGNAL ;
    PORT
      LAYER M5 ;
        RECT  30.432 34.368 30.456 34.56 ;
    END
  END q[333]
  PIN q[334]
    DIRECTION OUTPUT ;
    USE SIGNAL ;
    PORT
      LAYER M3 ;
        RECT  30.528 34.416 30.546 34.56 ;
    END
  END q[334]
  PIN q[335]
    DIRECTION OUTPUT ;
    USE SIGNAL ;
    PORT
      LAYER M5 ;
        RECT  30.576 34.368 30.6 34.56 ;
    END
  END q[335]
  PIN q[336]
    DIRECTION OUTPUT ;
    USE SIGNAL ;
    PORT
      LAYER M3 ;
        RECT  30.672 34.416 30.69 34.56 ;
    END
  END q[336]
  PIN q[337]
    DIRECTION OUTPUT ;
    USE SIGNAL ;
    PORT
      LAYER M5 ;
        RECT  30.72 34.368 30.744 34.56 ;
    END
  END q[337]
  PIN q[338]
    DIRECTION OUTPUT ;
    USE SIGNAL ;
    PORT
      LAYER M3 ;
        RECT  30.816 34.416 30.834 34.56 ;
    END
  END q[338]
  PIN q[339]
    DIRECTION OUTPUT ;
    USE SIGNAL ;
    PORT
      LAYER M5 ;
        RECT  30.864 34.368 30.888 34.56 ;
    END
  END q[339]
  PIN q[33]
    DIRECTION OUTPUT ;
    USE SIGNAL ;
    PORT
      LAYER M5 ;
        RECT  8.832 34.368 8.856 34.56 ;
    END
  END q[33]
  PIN q[340]
    DIRECTION OUTPUT ;
    USE SIGNAL ;
    PORT
      LAYER M3 ;
        RECT  30.96 34.416 30.978 34.56 ;
    END
  END q[340]
  PIN q[341]
    DIRECTION OUTPUT ;
    USE SIGNAL ;
    PORT
      LAYER M5 ;
        RECT  31.008 34.368 31.032 34.56 ;
    END
  END q[341]
  PIN q[342]
    DIRECTION OUTPUT ;
    USE SIGNAL ;
    PORT
      LAYER M3 ;
        RECT  31.104 34.416 31.122 34.56 ;
    END
  END q[342]
  PIN q[343]
    DIRECTION OUTPUT ;
    USE SIGNAL ;
    PORT
      LAYER M5 ;
        RECT  31.152 34.368 31.176 34.56 ;
    END
  END q[343]
  PIN q[344]
    DIRECTION OUTPUT ;
    USE SIGNAL ;
    PORT
      LAYER M3 ;
        RECT  31.248 34.416 31.266 34.56 ;
    END
  END q[344]
  PIN q[345]
    DIRECTION OUTPUT ;
    USE SIGNAL ;
    PORT
      LAYER M5 ;
        RECT  31.296 34.368 31.32 34.56 ;
    END
  END q[345]
  PIN q[346]
    DIRECTION OUTPUT ;
    USE SIGNAL ;
    PORT
      LAYER M3 ;
        RECT  31.392 34.416 31.41 34.56 ;
    END
  END q[346]
  PIN q[347]
    DIRECTION OUTPUT ;
    USE SIGNAL ;
    PORT
      LAYER M5 ;
        RECT  31.44 34.368 31.464 34.56 ;
    END
  END q[347]
  PIN q[348]
    DIRECTION OUTPUT ;
    USE SIGNAL ;
    PORT
      LAYER M3 ;
        RECT  31.536 34.416 31.554 34.56 ;
    END
  END q[348]
  PIN q[349]
    DIRECTION OUTPUT ;
    USE SIGNAL ;
    PORT
      LAYER M5 ;
        RECT  31.584 34.368 31.608 34.56 ;
    END
  END q[349]
  PIN q[34]
    DIRECTION OUTPUT ;
    USE SIGNAL ;
    PORT
      LAYER M3 ;
        RECT  8.928 34.416 8.946 34.56 ;
    END
  END q[34]
  PIN q[350]
    DIRECTION OUTPUT ;
    USE SIGNAL ;
    PORT
      LAYER M3 ;
        RECT  31.68 34.416 31.698 34.56 ;
    END
  END q[350]
  PIN q[351]
    DIRECTION OUTPUT ;
    USE SIGNAL ;
    PORT
      LAYER M5 ;
        RECT  31.728 34.368 31.752 34.56 ;
    END
  END q[351]
  PIN q[352]
    DIRECTION OUTPUT ;
    USE SIGNAL ;
    PORT
      LAYER M3 ;
        RECT  31.824 34.416 31.842 34.56 ;
    END
  END q[352]
  PIN q[353]
    DIRECTION OUTPUT ;
    USE SIGNAL ;
    PORT
      LAYER M5 ;
        RECT  31.872 34.368 31.896 34.56 ;
    END
  END q[353]
  PIN q[354]
    DIRECTION OUTPUT ;
    USE SIGNAL ;
    PORT
      LAYER M3 ;
        RECT  31.968 34.416 31.986 34.56 ;
    END
  END q[354]
  PIN q[355]
    DIRECTION OUTPUT ;
    USE SIGNAL ;
    PORT
      LAYER M5 ;
        RECT  32.016 34.368 32.04 34.56 ;
    END
  END q[355]
  PIN q[356]
    DIRECTION OUTPUT ;
    USE SIGNAL ;
    PORT
      LAYER M3 ;
        RECT  32.112 34.416 32.13 34.56 ;
    END
  END q[356]
  PIN q[357]
    DIRECTION OUTPUT ;
    USE SIGNAL ;
    PORT
      LAYER M5 ;
        RECT  32.16 34.368 32.184 34.56 ;
    END
  END q[357]
  PIN q[358]
    DIRECTION OUTPUT ;
    USE SIGNAL ;
    PORT
      LAYER M3 ;
        RECT  32.256 34.416 32.274 34.56 ;
    END
  END q[358]
  PIN q[359]
    DIRECTION OUTPUT ;
    USE SIGNAL ;
    PORT
      LAYER M5 ;
        RECT  32.304 34.368 32.328 34.56 ;
    END
  END q[359]
  PIN q[35]
    DIRECTION OUTPUT ;
    USE SIGNAL ;
    PORT
      LAYER M5 ;
        RECT  8.976 34.368 9 34.56 ;
    END
  END q[35]
  PIN q[360]
    DIRECTION OUTPUT ;
    USE SIGNAL ;
    PORT
      LAYER M3 ;
        RECT  32.4 34.416 32.418 34.56 ;
    END
  END q[360]
  PIN q[361]
    DIRECTION OUTPUT ;
    USE SIGNAL ;
    PORT
      LAYER M5 ;
        RECT  32.448 34.368 32.472 34.56 ;
    END
  END q[361]
  PIN q[362]
    DIRECTION OUTPUT ;
    USE SIGNAL ;
    PORT
      LAYER M3 ;
        RECT  32.544 34.416 32.562 34.56 ;
    END
  END q[362]
  PIN q[363]
    DIRECTION OUTPUT ;
    USE SIGNAL ;
    PORT
      LAYER M5 ;
        RECT  32.592 34.368 32.616 34.56 ;
    END
  END q[363]
  PIN q[364]
    DIRECTION OUTPUT ;
    USE SIGNAL ;
    PORT
      LAYER M3 ;
        RECT  32.688 34.416 32.706 34.56 ;
    END
  END q[364]
  PIN q[365]
    DIRECTION OUTPUT ;
    USE SIGNAL ;
    PORT
      LAYER M5 ;
        RECT  32.736 34.368 32.76 34.56 ;
    END
  END q[365]
  PIN q[366]
    DIRECTION OUTPUT ;
    USE SIGNAL ;
    PORT
      LAYER M3 ;
        RECT  32.832 34.416 32.85 34.56 ;
    END
  END q[366]
  PIN q[367]
    DIRECTION OUTPUT ;
    USE SIGNAL ;
    PORT
      LAYER M5 ;
        RECT  32.88 34.368 32.904 34.56 ;
    END
  END q[367]
  PIN q[368]
    DIRECTION OUTPUT ;
    USE SIGNAL ;
    PORT
      LAYER M3 ;
        RECT  32.976 34.416 32.994 34.56 ;
    END
  END q[368]
  PIN q[369]
    DIRECTION OUTPUT ;
    USE SIGNAL ;
    PORT
      LAYER M5 ;
        RECT  33.024 34.368 33.048 34.56 ;
    END
  END q[369]
  PIN q[36]
    DIRECTION OUTPUT ;
    USE SIGNAL ;
    PORT
      LAYER M3 ;
        RECT  9.072 34.416 9.09 34.56 ;
    END
  END q[36]
  PIN q[370]
    DIRECTION OUTPUT ;
    USE SIGNAL ;
    PORT
      LAYER M3 ;
        RECT  33.12 34.416 33.138 34.56 ;
    END
  END q[370]
  PIN q[371]
    DIRECTION OUTPUT ;
    USE SIGNAL ;
    PORT
      LAYER M5 ;
        RECT  33.168 34.368 33.192 34.56 ;
    END
  END q[371]
  PIN q[372]
    DIRECTION OUTPUT ;
    USE SIGNAL ;
    PORT
      LAYER M3 ;
        RECT  33.264 34.416 33.282 34.56 ;
    END
  END q[372]
  PIN q[373]
    DIRECTION OUTPUT ;
    USE SIGNAL ;
    PORT
      LAYER M5 ;
        RECT  33.312 34.368 33.336 34.56 ;
    END
  END q[373]
  PIN q[374]
    DIRECTION OUTPUT ;
    USE SIGNAL ;
    PORT
      LAYER M3 ;
        RECT  33.408 34.416 33.426 34.56 ;
    END
  END q[374]
  PIN q[375]
    DIRECTION OUTPUT ;
    USE SIGNAL ;
    PORT
      LAYER M5 ;
        RECT  33.456 34.368 33.48 34.56 ;
    END
  END q[375]
  PIN q[376]
    DIRECTION OUTPUT ;
    USE SIGNAL ;
    PORT
      LAYER M3 ;
        RECT  33.552 34.416 33.57 34.56 ;
    END
  END q[376]
  PIN q[377]
    DIRECTION OUTPUT ;
    USE SIGNAL ;
    PORT
      LAYER M5 ;
        RECT  33.6 34.368 33.624 34.56 ;
    END
  END q[377]
  PIN q[378]
    DIRECTION OUTPUT ;
    USE SIGNAL ;
    PORT
      LAYER M3 ;
        RECT  33.696 34.416 33.714 34.56 ;
    END
  END q[378]
  PIN q[379]
    DIRECTION OUTPUT ;
    USE SIGNAL ;
    PORT
      LAYER M5 ;
        RECT  33.744 34.368 33.768 34.56 ;
    END
  END q[379]
  PIN q[37]
    DIRECTION OUTPUT ;
    USE SIGNAL ;
    PORT
      LAYER M5 ;
        RECT  9.12 34.368 9.144 34.56 ;
    END
  END q[37]
  PIN q[380]
    DIRECTION OUTPUT ;
    USE SIGNAL ;
    PORT
      LAYER M3 ;
        RECT  33.84 34.416 33.858 34.56 ;
    END
  END q[380]
  PIN q[381]
    DIRECTION OUTPUT ;
    USE SIGNAL ;
    PORT
      LAYER M5 ;
        RECT  33.888 34.368 33.912 34.56 ;
    END
  END q[381]
  PIN q[382]
    DIRECTION OUTPUT ;
    USE SIGNAL ;
    PORT
      LAYER M3 ;
        RECT  33.984 34.416 34.002 34.56 ;
    END
  END q[382]
  PIN q[383]
    DIRECTION OUTPUT ;
    USE SIGNAL ;
    PORT
      LAYER M5 ;
        RECT  34.032 34.368 34.056 34.56 ;
    END
  END q[383]
  PIN q[384]
    DIRECTION OUTPUT ;
    USE SIGNAL ;
    PORT
      LAYER M3 ;
        RECT  34.128 34.416 34.146 34.56 ;
    END
  END q[384]
  PIN q[385]
    DIRECTION OUTPUT ;
    USE SIGNAL ;
    PORT
      LAYER M5 ;
        RECT  34.176 34.368 34.2 34.56 ;
    END
  END q[385]
  PIN q[386]
    DIRECTION OUTPUT ;
    USE SIGNAL ;
    PORT
      LAYER M3 ;
        RECT  34.272 34.416 34.29 34.56 ;
    END
  END q[386]
  PIN q[387]
    DIRECTION OUTPUT ;
    USE SIGNAL ;
    PORT
      LAYER M5 ;
        RECT  34.32 34.368 34.344 34.56 ;
    END
  END q[387]
  PIN q[388]
    DIRECTION OUTPUT ;
    USE SIGNAL ;
    PORT
      LAYER M3 ;
        RECT  34.416 34.416 34.434 34.56 ;
    END
  END q[388]
  PIN q[389]
    DIRECTION OUTPUT ;
    USE SIGNAL ;
    PORT
      LAYER M5 ;
        RECT  34.464 34.368 34.488 34.56 ;
    END
  END q[389]
  PIN q[38]
    DIRECTION OUTPUT ;
    USE SIGNAL ;
    PORT
      LAYER M3 ;
        RECT  9.216 34.416 9.234 34.56 ;
    END
  END q[38]
  PIN q[390]
    DIRECTION OUTPUT ;
    USE SIGNAL ;
    PORT
      LAYER M3 ;
        RECT  34.56 34.416 34.578 34.56 ;
    END
  END q[390]
  PIN q[391]
    DIRECTION OUTPUT ;
    USE SIGNAL ;
    PORT
      LAYER M5 ;
        RECT  34.608 34.368 34.632 34.56 ;
    END
  END q[391]
  PIN q[392]
    DIRECTION OUTPUT ;
    USE SIGNAL ;
    PORT
      LAYER M3 ;
        RECT  34.704 34.416 34.722 34.56 ;
    END
  END q[392]
  PIN q[393]
    DIRECTION OUTPUT ;
    USE SIGNAL ;
    PORT
      LAYER M5 ;
        RECT  34.752 34.368 34.776 34.56 ;
    END
  END q[393]
  PIN q[394]
    DIRECTION OUTPUT ;
    USE SIGNAL ;
    PORT
      LAYER M3 ;
        RECT  34.848 34.416 34.866 34.56 ;
    END
  END q[394]
  PIN q[395]
    DIRECTION OUTPUT ;
    USE SIGNAL ;
    PORT
      LAYER M5 ;
        RECT  34.896 34.368 34.92 34.56 ;
    END
  END q[395]
  PIN q[396]
    DIRECTION OUTPUT ;
    USE SIGNAL ;
    PORT
      LAYER M3 ;
        RECT  34.992 34.416 35.01 34.56 ;
    END
  END q[396]
  PIN q[397]
    DIRECTION OUTPUT ;
    USE SIGNAL ;
    PORT
      LAYER M5 ;
        RECT  35.04 34.368 35.064 34.56 ;
    END
  END q[397]
  PIN q[398]
    DIRECTION OUTPUT ;
    USE SIGNAL ;
    PORT
      LAYER M3 ;
        RECT  35.136 34.416 35.154 34.56 ;
    END
  END q[398]
  PIN q[399]
    DIRECTION OUTPUT ;
    USE SIGNAL ;
    PORT
      LAYER M5 ;
        RECT  35.184 34.368 35.208 34.56 ;
    END
  END q[399]
  PIN q[39]
    DIRECTION OUTPUT ;
    USE SIGNAL ;
    PORT
      LAYER M5 ;
        RECT  9.264 34.368 9.288 34.56 ;
    END
  END q[39]
  PIN q[3]
    DIRECTION OUTPUT ;
    USE SIGNAL ;
    PORT
      LAYER M5 ;
        RECT  6.672 34.368 6.696 34.56 ;
    END
  END q[3]
  PIN q[400]
    DIRECTION OUTPUT ;
    USE SIGNAL ;
    PORT
      LAYER M3 ;
        RECT  35.28 34.416 35.298 34.56 ;
    END
  END q[400]
  PIN q[401]
    DIRECTION OUTPUT ;
    USE SIGNAL ;
    PORT
      LAYER M5 ;
        RECT  35.328 34.368 35.352 34.56 ;
    END
  END q[401]
  PIN q[402]
    DIRECTION OUTPUT ;
    USE SIGNAL ;
    PORT
      LAYER M3 ;
        RECT  35.424 34.416 35.442 34.56 ;
    END
  END q[402]
  PIN q[403]
    DIRECTION OUTPUT ;
    USE SIGNAL ;
    PORT
      LAYER M5 ;
        RECT  35.472 34.368 35.496 34.56 ;
    END
  END q[403]
  PIN q[404]
    DIRECTION OUTPUT ;
    USE SIGNAL ;
    PORT
      LAYER M3 ;
        RECT  35.568 34.416 35.586 34.56 ;
    END
  END q[404]
  PIN q[405]
    DIRECTION OUTPUT ;
    USE SIGNAL ;
    PORT
      LAYER M5 ;
        RECT  35.616 34.368 35.64 34.56 ;
    END
  END q[405]
  PIN q[406]
    DIRECTION OUTPUT ;
    USE SIGNAL ;
    PORT
      LAYER M3 ;
        RECT  35.712 34.416 35.73 34.56 ;
    END
  END q[406]
  PIN q[407]
    DIRECTION OUTPUT ;
    USE SIGNAL ;
    PORT
      LAYER M5 ;
        RECT  35.76 34.368 35.784 34.56 ;
    END
  END q[407]
  PIN q[40]
    DIRECTION OUTPUT ;
    USE SIGNAL ;
    PORT
      LAYER M3 ;
        RECT  9.36 34.416 9.378 34.56 ;
    END
  END q[40]
  PIN q[41]
    DIRECTION OUTPUT ;
    USE SIGNAL ;
    PORT
      LAYER M5 ;
        RECT  9.408 34.368 9.432 34.56 ;
    END
  END q[41]
  PIN q[42]
    DIRECTION OUTPUT ;
    USE SIGNAL ;
    PORT
      LAYER M3 ;
        RECT  9.504 34.416 9.522 34.56 ;
    END
  END q[42]
  PIN q[43]
    DIRECTION OUTPUT ;
    USE SIGNAL ;
    PORT
      LAYER M5 ;
        RECT  9.552 34.368 9.576 34.56 ;
    END
  END q[43]
  PIN q[44]
    DIRECTION OUTPUT ;
    USE SIGNAL ;
    PORT
      LAYER M3 ;
        RECT  9.648 34.416 9.666 34.56 ;
    END
  END q[44]
  PIN q[45]
    DIRECTION OUTPUT ;
    USE SIGNAL ;
    PORT
      LAYER M5 ;
        RECT  9.696 34.368 9.72 34.56 ;
    END
  END q[45]
  PIN q[46]
    DIRECTION OUTPUT ;
    USE SIGNAL ;
    PORT
      LAYER M3 ;
        RECT  9.792 34.416 9.81 34.56 ;
    END
  END q[46]
  PIN q[47]
    DIRECTION OUTPUT ;
    USE SIGNAL ;
    PORT
      LAYER M5 ;
        RECT  9.84 34.368 9.864 34.56 ;
    END
  END q[47]
  PIN q[48]
    DIRECTION OUTPUT ;
    USE SIGNAL ;
    PORT
      LAYER M3 ;
        RECT  9.936 34.416 9.954 34.56 ;
    END
  END q[48]
  PIN q[49]
    DIRECTION OUTPUT ;
    USE SIGNAL ;
    PORT
      LAYER M5 ;
        RECT  9.984 34.368 10.008 34.56 ;
    END
  END q[49]
  PIN q[4]
    DIRECTION OUTPUT ;
    USE SIGNAL ;
    PORT
      LAYER M3 ;
        RECT  6.768 34.416 6.786 34.56 ;
    END
  END q[4]
  PIN q[50]
    DIRECTION OUTPUT ;
    USE SIGNAL ;
    PORT
      LAYER M3 ;
        RECT  10.08 34.416 10.098 34.56 ;
    END
  END q[50]
  PIN q[51]
    DIRECTION OUTPUT ;
    USE SIGNAL ;
    PORT
      LAYER M5 ;
        RECT  10.128 34.368 10.152 34.56 ;
    END
  END q[51]
  PIN q[52]
    DIRECTION OUTPUT ;
    USE SIGNAL ;
    PORT
      LAYER M3 ;
        RECT  10.224 34.416 10.242 34.56 ;
    END
  END q[52]
  PIN q[53]
    DIRECTION OUTPUT ;
    USE SIGNAL ;
    PORT
      LAYER M5 ;
        RECT  10.272 34.368 10.296 34.56 ;
    END
  END q[53]
  PIN q[54]
    DIRECTION OUTPUT ;
    USE SIGNAL ;
    PORT
      LAYER M3 ;
        RECT  10.368 34.416 10.386 34.56 ;
    END
  END q[54]
  PIN q[55]
    DIRECTION OUTPUT ;
    USE SIGNAL ;
    PORT
      LAYER M5 ;
        RECT  10.416 34.368 10.44 34.56 ;
    END
  END q[55]
  PIN q[56]
    DIRECTION OUTPUT ;
    USE SIGNAL ;
    PORT
      LAYER M3 ;
        RECT  10.512 34.416 10.53 34.56 ;
    END
  END q[56]
  PIN q[57]
    DIRECTION OUTPUT ;
    USE SIGNAL ;
    PORT
      LAYER M5 ;
        RECT  10.56 34.368 10.584 34.56 ;
    END
  END q[57]
  PIN q[58]
    DIRECTION OUTPUT ;
    USE SIGNAL ;
    PORT
      LAYER M3 ;
        RECT  10.656 34.416 10.674 34.56 ;
    END
  END q[58]
  PIN q[59]
    DIRECTION OUTPUT ;
    USE SIGNAL ;
    PORT
      LAYER M5 ;
        RECT  10.704 34.368 10.728 34.56 ;
    END
  END q[59]
  PIN q[5]
    DIRECTION OUTPUT ;
    USE SIGNAL ;
    PORT
      LAYER M5 ;
        RECT  6.816 34.368 6.84 34.56 ;
    END
  END q[5]
  PIN q[60]
    DIRECTION OUTPUT ;
    USE SIGNAL ;
    PORT
      LAYER M3 ;
        RECT  10.8 34.416 10.818 34.56 ;
    END
  END q[60]
  PIN q[61]
    DIRECTION OUTPUT ;
    USE SIGNAL ;
    PORT
      LAYER M5 ;
        RECT  10.848 34.368 10.872 34.56 ;
    END
  END q[61]
  PIN q[62]
    DIRECTION OUTPUT ;
    USE SIGNAL ;
    PORT
      LAYER M3 ;
        RECT  10.944 34.416 10.962 34.56 ;
    END
  END q[62]
  PIN q[63]
    DIRECTION OUTPUT ;
    USE SIGNAL ;
    PORT
      LAYER M5 ;
        RECT  10.992 34.368 11.016 34.56 ;
    END
  END q[63]
  PIN q[64]
    DIRECTION OUTPUT ;
    USE SIGNAL ;
    PORT
      LAYER M3 ;
        RECT  11.088 34.416 11.106 34.56 ;
    END
  END q[64]
  PIN q[65]
    DIRECTION OUTPUT ;
    USE SIGNAL ;
    PORT
      LAYER M5 ;
        RECT  11.136 34.368 11.16 34.56 ;
    END
  END q[65]
  PIN q[66]
    DIRECTION OUTPUT ;
    USE SIGNAL ;
    PORT
      LAYER M3 ;
        RECT  11.232 34.416 11.25 34.56 ;
    END
  END q[66]
  PIN q[67]
    DIRECTION OUTPUT ;
    USE SIGNAL ;
    PORT
      LAYER M5 ;
        RECT  11.28 34.368 11.304 34.56 ;
    END
  END q[67]
  PIN q[68]
    DIRECTION OUTPUT ;
    USE SIGNAL ;
    PORT
      LAYER M3 ;
        RECT  11.376 34.416 11.394 34.56 ;
    END
  END q[68]
  PIN q[69]
    DIRECTION OUTPUT ;
    USE SIGNAL ;
    PORT
      LAYER M5 ;
        RECT  11.424 34.368 11.448 34.56 ;
    END
  END q[69]
  PIN q[6]
    DIRECTION OUTPUT ;
    USE SIGNAL ;
    PORT
      LAYER M3 ;
        RECT  6.912 34.416 6.93 34.56 ;
    END
  END q[6]
  PIN q[70]
    DIRECTION OUTPUT ;
    USE SIGNAL ;
    PORT
      LAYER M3 ;
        RECT  11.52 34.416 11.538 34.56 ;
    END
  END q[70]
  PIN q[71]
    DIRECTION OUTPUT ;
    USE SIGNAL ;
    PORT
      LAYER M5 ;
        RECT  11.568 34.368 11.592 34.56 ;
    END
  END q[71]
  PIN q[72]
    DIRECTION OUTPUT ;
    USE SIGNAL ;
    PORT
      LAYER M3 ;
        RECT  11.664 34.416 11.682 34.56 ;
    END
  END q[72]
  PIN q[73]
    DIRECTION OUTPUT ;
    USE SIGNAL ;
    PORT
      LAYER M5 ;
        RECT  11.712 34.368 11.736 34.56 ;
    END
  END q[73]
  PIN q[74]
    DIRECTION OUTPUT ;
    USE SIGNAL ;
    PORT
      LAYER M3 ;
        RECT  11.808 34.416 11.826 34.56 ;
    END
  END q[74]
  PIN q[75]
    DIRECTION OUTPUT ;
    USE SIGNAL ;
    PORT
      LAYER M5 ;
        RECT  11.856 34.368 11.88 34.56 ;
    END
  END q[75]
  PIN q[76]
    DIRECTION OUTPUT ;
    USE SIGNAL ;
    PORT
      LAYER M3 ;
        RECT  11.952 34.416 11.97 34.56 ;
    END
  END q[76]
  PIN q[77]
    DIRECTION OUTPUT ;
    USE SIGNAL ;
    PORT
      LAYER M5 ;
        RECT  12 34.368 12.024 34.56 ;
    END
  END q[77]
  PIN q[78]
    DIRECTION OUTPUT ;
    USE SIGNAL ;
    PORT
      LAYER M3 ;
        RECT  12.096 34.416 12.114 34.56 ;
    END
  END q[78]
  PIN q[79]
    DIRECTION OUTPUT ;
    USE SIGNAL ;
    PORT
      LAYER M5 ;
        RECT  12.144 34.368 12.168 34.56 ;
    END
  END q[79]
  PIN q[7]
    DIRECTION OUTPUT ;
    USE SIGNAL ;
    PORT
      LAYER M5 ;
        RECT  6.96 34.368 6.984 34.56 ;
    END
  END q[7]
  PIN q[80]
    DIRECTION OUTPUT ;
    USE SIGNAL ;
    PORT
      LAYER M3 ;
        RECT  12.24 34.416 12.258 34.56 ;
    END
  END q[80]
  PIN q[81]
    DIRECTION OUTPUT ;
    USE SIGNAL ;
    PORT
      LAYER M5 ;
        RECT  12.288 34.368 12.312 34.56 ;
    END
  END q[81]
  PIN q[82]
    DIRECTION OUTPUT ;
    USE SIGNAL ;
    PORT
      LAYER M3 ;
        RECT  12.384 34.416 12.402 34.56 ;
    END
  END q[82]
  PIN q[83]
    DIRECTION OUTPUT ;
    USE SIGNAL ;
    PORT
      LAYER M5 ;
        RECT  12.432 34.368 12.456 34.56 ;
    END
  END q[83]
  PIN q[84]
    DIRECTION OUTPUT ;
    USE SIGNAL ;
    PORT
      LAYER M3 ;
        RECT  12.528 34.416 12.546 34.56 ;
    END
  END q[84]
  PIN q[85]
    DIRECTION OUTPUT ;
    USE SIGNAL ;
    PORT
      LAYER M5 ;
        RECT  12.576 34.368 12.6 34.56 ;
    END
  END q[85]
  PIN q[86]
    DIRECTION OUTPUT ;
    USE SIGNAL ;
    PORT
      LAYER M3 ;
        RECT  12.672 34.416 12.69 34.56 ;
    END
  END q[86]
  PIN q[87]
    DIRECTION OUTPUT ;
    USE SIGNAL ;
    PORT
      LAYER M5 ;
        RECT  12.72 34.368 12.744 34.56 ;
    END
  END q[87]
  PIN q[88]
    DIRECTION OUTPUT ;
    USE SIGNAL ;
    PORT
      LAYER M3 ;
        RECT  12.816 34.416 12.834 34.56 ;
    END
  END q[88]
  PIN q[89]
    DIRECTION OUTPUT ;
    USE SIGNAL ;
    PORT
      LAYER M5 ;
        RECT  12.864 34.368 12.888 34.56 ;
    END
  END q[89]
  PIN q[8]
    DIRECTION OUTPUT ;
    USE SIGNAL ;
    PORT
      LAYER M3 ;
        RECT  7.056 34.416 7.074 34.56 ;
    END
  END q[8]
  PIN q[90]
    DIRECTION OUTPUT ;
    USE SIGNAL ;
    PORT
      LAYER M3 ;
        RECT  12.96 34.416 12.978 34.56 ;
    END
  END q[90]
  PIN q[91]
    DIRECTION OUTPUT ;
    USE SIGNAL ;
    PORT
      LAYER M5 ;
        RECT  13.008 34.368 13.032 34.56 ;
    END
  END q[91]
  PIN q[92]
    DIRECTION OUTPUT ;
    USE SIGNAL ;
    PORT
      LAYER M3 ;
        RECT  13.104 34.416 13.122 34.56 ;
    END
  END q[92]
  PIN q[93]
    DIRECTION OUTPUT ;
    USE SIGNAL ;
    PORT
      LAYER M5 ;
        RECT  13.152 34.368 13.176 34.56 ;
    END
  END q[93]
  PIN q[94]
    DIRECTION OUTPUT ;
    USE SIGNAL ;
    PORT
      LAYER M3 ;
        RECT  13.248 34.416 13.266 34.56 ;
    END
  END q[94]
  PIN q[95]
    DIRECTION OUTPUT ;
    USE SIGNAL ;
    PORT
      LAYER M5 ;
        RECT  13.296 34.368 13.32 34.56 ;
    END
  END q[95]
  PIN q[96]
    DIRECTION OUTPUT ;
    USE SIGNAL ;
    PORT
      LAYER M3 ;
        RECT  13.392 34.416 13.41 34.56 ;
    END
  END q[96]
  PIN q[97]
    DIRECTION OUTPUT ;
    USE SIGNAL ;
    PORT
      LAYER M5 ;
        RECT  13.44 34.368 13.464 34.56 ;
    END
  END q[97]
  PIN q[98]
    DIRECTION OUTPUT ;
    USE SIGNAL ;
    PORT
      LAYER M3 ;
        RECT  13.536 34.416 13.554 34.56 ;
    END
  END q[98]
  PIN q[99]
    DIRECTION OUTPUT ;
    USE SIGNAL ;
    PORT
      LAYER M5 ;
        RECT  13.584 34.368 13.608 34.56 ;
    END
  END q[99]
  PIN q[9]
    DIRECTION OUTPUT ;
    USE SIGNAL ;
    PORT
      LAYER M5 ;
        RECT  7.104 34.368 7.128 34.56 ;
    END
  END q[9]
  PIN rst_n
    DIRECTION INPUT ;
    USE SIGNAL ;
    PORT
      LAYER M4 ;
        RECT  0 14.88 0.192 14.904 ;
    END
    PORT
      LAYER M4 ;
        RECT  0.156 14.88 2.408 14.904 ;
    END
  END rst_n
  PIN VDD
    DIRECTION INOUT ;
    USE POWER ;
    PORT
      LAYER M5 ;
        RECT  40.392 2.151 40.512 32.409 ;
        RECT  34.992 2.151 35.112 32.409 ;
        RECT  29.592 2.151 29.712 32.409 ;
        RECT  24.192 2.151 24.312 32.409 ;
        RECT  18.792 2.151 18.912 32.409 ;
        RECT  13.392 2.151 13.512 32.409 ;
        RECT  7.992 2.151 8.112 32.409 ;
        RECT  2.592 2.151 2.712 32.409 ;
    END
  END VDD
  PIN VSS
    DIRECTION INOUT ;
    USE GROUND ;
    PORT
      LAYER M5 ;
        RECT  40.2 2.137 40.32 32.423 ;
        RECT  34.8 2.137 34.92 32.423 ;
        RECT  29.4 2.137 29.52 32.423 ;
        RECT  24 2.137 24.12 32.423 ;
        RECT  18.6 2.137 18.72 32.423 ;
        RECT  13.2 2.137 13.32 32.423 ;
        RECT  7.8 2.137 7.92 32.423 ;
        RECT  2.4 2.137 2.52 32.423 ;
    END
  END VSS
  # OT_OBS_CLOSED layer=M5 d_um=1.536 added=13
  OBS
    LAYER RVTN ;
     RECT  2.16 2.16 41.04 2.295 ;
     RECT  2.16 2.565 41.04 2.835 ;
     RECT  2.16 3.105 41.04 3.375 ;
     RECT  2.16 3.645 41.04 3.915 ;
     RECT  2.16 4.185 41.04 4.455 ;
     RECT  2.16 4.725 41.04 4.995 ;
     RECT  2.16 5.265 41.04 5.535 ;
     RECT  2.16 5.805 41.04 6.075 ;
     RECT  2.16 6.345 41.04 6.615 ;
     RECT  2.16 6.885 41.04 7.155 ;
     RECT  2.16 7.425 41.04 7.695 ;
     RECT  2.16 7.965 41.04 8.235 ;
     RECT  2.16 8.505 41.04 8.775 ;
     RECT  2.16 9.045 41.04 9.315 ;
     RECT  2.16 9.585 41.04 9.855 ;
     RECT  2.16 10.125 41.04 10.395 ;
     RECT  2.16 10.665 41.04 10.935 ;
     RECT  2.16 11.205 41.04 11.475 ;
     RECT  2.16 11.745 41.04 12.015 ;
     RECT  2.16 12.285 41.04 12.555 ;
     RECT  2.16 12.825 41.04 13.095 ;
     RECT  2.16 13.365 41.04 13.635 ;
     RECT  2.16 13.905 41.04 14.175 ;
     RECT  2.16 14.445 41.04 14.715 ;
     RECT  2.16 14.985 41.04 15.255 ;
     RECT  2.16 15.525 41.04 15.795 ;
     RECT  2.16 16.065 41.04 16.335 ;
     RECT  2.16 16.605 41.04 16.875 ;
     RECT  2.16 17.145 41.04 17.415 ;
     RECT  2.16 17.685 41.04 17.955 ;
     RECT  2.16 18.225 41.04 18.495 ;
     RECT  2.16 18.765 41.04 19.035 ;
     RECT  2.16 19.305 41.04 19.575 ;
     RECT  2.16 19.845 41.04 20.115 ;
     RECT  2.16 20.385 41.04 20.655 ;
     RECT  2.16 20.925 41.04 21.195 ;
     RECT  2.16 21.465 41.04 21.735 ;
     RECT  2.16 22.005 41.04 22.275 ;
     RECT  2.16 22.545 41.04 22.815 ;
     RECT  2.16 23.085 41.04 23.355 ;
     RECT  2.16 23.625 41.04 23.895 ;
     RECT  2.16 24.165 41.04 24.435 ;
     RECT  2.16 24.705 41.04 24.975 ;
     RECT  2.16 25.245 41.04 25.515 ;
     RECT  2.16 25.785 41.04 26.055 ;
     RECT  2.16 26.325 41.04 26.595 ;
     RECT  2.16 26.865 41.04 27.135 ;
     RECT  2.16 27.405 41.04 27.675 ;
     RECT  2.16 27.945 41.04 28.215 ;
     RECT  2.16 28.485 41.04 28.755 ;
     RECT  2.16 29.025 41.04 29.295 ;
     RECT  2.16 29.565 41.04 29.835 ;
     RECT  2.16 30.105 41.04 30.375 ;
     RECT  2.16 30.645 41.04 30.915 ;
     RECT  2.16 31.185 41.04 31.455 ;
     RECT  2.16 31.725 41.04 31.995 ;
     RECT  2.16 32.265 41.04 32.4 ;
    LAYER RVTP ;
     RECT  2.16 2.295 41.04 2.565 ;
     RECT  2.16 2.835 41.04 3.105 ;
     RECT  2.16 3.375 41.04 3.645 ;
     RECT  2.16 3.915 41.04 4.185 ;
     RECT  2.16 4.455 41.04 4.725 ;
     RECT  2.16 4.995 41.04 5.265 ;
     RECT  2.16 5.535 41.04 5.805 ;
     RECT  2.16 6.075 41.04 6.345 ;
     RECT  2.16 6.615 41.04 6.885 ;
     RECT  2.16 7.155 41.04 7.425 ;
     RECT  2.16 7.695 41.04 7.965 ;
     RECT  2.16 8.235 41.04 8.505 ;
     RECT  2.16 8.775 41.04 9.045 ;
     RECT  2.16 9.315 41.04 9.585 ;
     RECT  2.16 9.855 41.04 10.125 ;
     RECT  2.16 10.395 41.04 10.665 ;
     RECT  2.16 10.935 41.04 11.205 ;
     RECT  2.16 11.475 41.04 11.745 ;
     RECT  2.16 12.015 41.04 12.285 ;
     RECT  2.16 12.555 41.04 12.825 ;
     RECT  2.16 13.095 41.04 13.365 ;
     RECT  2.16 13.635 41.04 13.905 ;
     RECT  2.16 14.175 41.04 14.445 ;
     RECT  2.16 14.715 41.04 14.985 ;
     RECT  2.16 15.255 41.04 15.525 ;
     RECT  2.16 15.795 41.04 16.065 ;
     RECT  2.16 16.335 41.04 16.605 ;
     RECT  2.16 16.875 41.04 17.145 ;
     RECT  2.16 17.415 41.04 17.685 ;
     RECT  2.16 17.955 41.04 18.225 ;
     RECT  2.16 18.495 41.04 18.765 ;
     RECT  2.16 19.035 41.04 19.305 ;
     RECT  2.16 19.575 41.04 19.845 ;
     RECT  2.16 20.115 41.04 20.385 ;
     RECT  2.16 20.655 41.04 20.925 ;
     RECT  2.16 21.195 41.04 21.465 ;
     RECT  2.16 21.735 41.04 22.005 ;
     RECT  2.16 22.275 41.04 22.545 ;
     RECT  2.16 22.815 41.04 23.085 ;
     RECT  2.16 23.355 41.04 23.625 ;
     RECT  2.16 23.895 41.04 24.165 ;
     RECT  2.16 24.435 41.04 24.705 ;
     RECT  2.16 24.975 41.04 25.245 ;
     RECT  2.16 25.515 41.04 25.785 ;
     RECT  2.16 26.055 41.04 26.325 ;
     RECT  2.16 26.595 41.04 26.865 ;
     RECT  2.16 27.135 41.04 27.405 ;
     RECT  2.16 27.675 41.04 27.945 ;
     RECT  2.16 28.215 41.04 28.485 ;
     RECT  2.16 28.755 41.04 29.025 ;
     RECT  2.16 29.295 41.04 29.565 ;
     RECT  2.16 29.835 41.04 30.105 ;
     RECT  2.16 30.375 41.04 30.645 ;
     RECT  2.16 30.915 41.04 31.185 ;
     RECT  2.16 31.455 41.04 31.725 ;
     RECT  2.16 31.995 41.04 32.265 ;
    LAYER M1 ;
     RECT  2.16 2.151 41.04 32.409 ;
    LAYER M2 ;
     RECT  2.16 2.151 5.287 32.409 ;
     RECT  5.287 2.151 6.367 32.454 ;
     RECT  6.367 2.106 6.511 32.454 ;
     RECT  6.511 2.106 7.339 33.066 ;
     RECT  7.267 0.576 7.555 0.594 ;
     RECT  7.339 1.728 7.727 33.066 ;
     RECT  7.727 2.106 7.763 33.066 ;
     RECT  7.555 0.144 7.943 0.594 ;
     RECT  7.943 0.576 8.087 0.594 ;
     RECT  7.763 2.151 8.447 33.066 ;
     RECT  8.447 2.151 8.483 32.598 ;
     RECT  8.483 2.151 9.499 32.526 ;
     RECT  9.499 2.151 10.031 33.066 ;
     RECT  10.031 2.151 10.219 32.454 ;
     RECT  10.219 1.728 10.427 32.454 ;
     RECT  9.247 0.144 10.579 0.162 ;
     RECT  10.579 0.144 10.679 0.234 ;
     RECT  10.679 0.216 10.823 0.234 ;
     RECT  11.011 0.531 11.147 0.549 ;
     RECT  10.427 2.151 11.767 32.454 ;
     RECT  11.767 2.151 13.135 33.066 ;
     RECT  12.847 0.144 13.991 0.162 ;
     RECT  13.999 0.216 14.135 0.234 ;
     RECT  14.179 1.152 14.423 1.17 ;
     RECT  13.135 2.106 14.423 33.066 ;
     RECT  14.827 0.144 14.935 0.162 ;
     RECT  14.935 0.144 15.071 0.234 ;
     RECT  15.071 0.144 16.123 0.162 ;
     RECT  16.123 0.144 16.187 0.198 ;
     RECT  16.187 0.144 18.095 0.162 ;
     RECT  18.391 0.414 18.527 0.432 ;
     RECT  18.535 1.152 18.743 1.17 ;
     RECT  14.423 2.151 20.111 33.066 ;
     RECT  19.795 0.144 20.731 0.162 ;
     RECT  20.731 0.144 20.875 0.198 ;
     RECT  20.875 0.144 20.939 0.279 ;
     RECT  20.939 0.261 20.975 0.279 ;
     RECT  20.111 2.151 21.019 32.409 ;
     RECT  21.019 1.728 21.227 32.409 ;
     RECT  21.227 2.151 21.559 32.409 ;
     RECT  21.559 2.151 21.991 33.066 ;
     RECT  21.991 2.106 22.027 33.066 ;
     RECT  22.027 1.728 22.307 33.066 ;
     RECT  22.099 0.144 22.451 0.162 ;
     RECT  22.307 2.106 22.531 33.066 ;
     RECT  22.531 2.106 22.631 33.759 ;
     RECT  22.631 2.106 22.775 33.066 ;
     RECT  22.711 0.531 22.847 0.549 ;
     RECT  22.775 2.151 22.991 33.066 ;
     RECT  22.991 2.151 23.791 32.49 ;
     RECT  23.539 0.144 24.179 0.162 ;
     RECT  23.791 2.151 24.475 33.066 ;
     RECT  24.475 1.728 24.575 33.066 ;
     RECT  24.575 2.151 24.719 33.066 ;
     RECT  24.763 1.152 24.863 1.17 ;
     RECT  24.719 2.151 25.771 32.409 ;
     RECT  25.771 2.151 26.923 33.066 ;
     RECT  26.923 2.151 27.067 33.174 ;
     RECT  27.067 2.151 27.167 33.759 ;
     RECT  27.167 2.151 27.851 33.066 ;
     RECT  27.031 0.144 28.255 0.162 ;
     RECT  28.255 0.144 28.391 0.234 ;
     RECT  27.851 2.151 28.651 32.409 ;
     RECT  28.651 2.151 28.751 33.066 ;
     RECT  28.751 2.151 29.659 32.562 ;
     RECT  28.391 0.144 29.803 0.162 ;
     RECT  29.659 2.151 30.091 33.066 ;
     RECT  30.091 1.728 30.299 33.066 ;
     RECT  29.803 0.144 30.515 0.234 ;
     RECT  30.515 0.216 30.623 0.234 ;
     RECT  30.299 2.151 31.055 33.066 ;
     RECT  31.055 2.151 31.127 32.994 ;
     RECT  31.127 2.151 31.963 32.454 ;
     RECT  31.963 2.151 32.063 33.066 ;
     RECT  32.827 33.156 33.035 33.174 ;
     RECT  33.259 0.144 33.511 0.162 ;
     RECT  33.511 0.144 33.647 0.234 ;
     RECT  32.063 2.151 34.771 32.409 ;
     RECT  34.771 1.728 34.843 32.409 ;
     RECT  33.647 0.144 35.195 0.162 ;
     RECT  34.843 1.728 35.275 32.49 ;
     RECT  35.275 1.728 36.023 32.526 ;
     RECT  36.023 2.151 36.599 32.526 ;
     RECT  36.599 2.151 37.319 32.49 ;
     RECT  37.319 2.151 41.04 32.409 ;
    LAYER M3 ;
     RECT  6.48 0.108 35.73 0.571 ;
     RECT  6.084 0.571 35.73 1.723 ;
     RECT  6.084 1.723 36.018 2.263 ;
     RECT  2.415 2.143 2.505 2.413 ;
     RECT  40.215 2.143 40.305 2.413 ;
     RECT  6.084 2.263 36.666 2.641 ;
     RECT  5.364 2.641 36.666 3.839 ;
     RECT  5.544 3.839 36.666 4.145 ;
     RECT  5.544 4.145 5.562 5.737 ;
     RECT  5.328 5.737 5.562 5.789 ;
     RECT  6.3 4.145 36.666 5.881 ;
     RECT  6.012 5.881 36.666 6.691 ;
     RECT  5.616 6.691 36.666 6.797 ;
     RECT  5.436 7.123 5.454 8.005 ;
     RECT  6.228 6.797 36.666 8.005 ;
     RECT  5.436 8.005 36.666 13.531 ;
     RECT  5.436 13.531 36.918 13.981 ;
     RECT  5.436 13.981 37.026 14.791 ;
     RECT  2.415 2.413 2.697 14.875 ;
     RECT  2.304 14.875 2.697 15.215 ;
     RECT  5.436 14.791 37.242 16.169 ;
     RECT  5.436 16.169 37.17 26.825 ;
     RECT  5.508 26.825 37.17 29.191 ;
     RECT  5.148 29.191 37.17 30.181 ;
     RECT  5.148 30.181 37.35 31.867 ;
     RECT  5.148 31.867 37.746 31.919 ;
     RECT  5.148 31.919 37.638 32.063 ;
     RECT  2.415 15.215 2.697 32.147 ;
     RECT  40.215 2.413 40.497 32.147 ;
     RECT  5.148 32.063 37.35 32.261 ;
     RECT  5.148 32.261 5.742 32.333 ;
     RECT  6.48 32.261 37.35 32.333 ;
     RECT  2.415 32.147 2.505 32.417 ;
     RECT  40.215 32.147 40.305 32.417 ;
     RECT  5.292 32.333 5.31 32.459 ;
     RECT  6.48 32.333 37.314 32.477 ;
     RECT  36.576 32.477 37.314 32.495 ;
     RECT  36.576 32.495 36.594 32.531 ;
     RECT  6.48 32.477 35.73 34.428 ;
    LAYER M4 ;
     RECT  0.229 10.656 2.408 10.68 ;
     RECT  2.408 2.148 2.512 32.412 ;
     RECT  2.512 2.418 2.704 32.142 ;
     RECT  5.605 6.768 6.293 6.792 ;
     RECT  6.397 1.776 6.497 1.8 ;
     RECT  6.469 31.872 6.563 31.896 ;
     RECT  6.145 8.208 6.577 8.232 ;
     RECT  6.577 7.776 6.661 8.232 ;
     RECT  6.397 9.36 6.661 9.384 ;
     RECT  6.505 34.368 6.661 34.392 ;
     RECT  6.497 1.728 6.685 1.8 ;
     RECT  6.685 1.68 6.764 1.8 ;
     RECT  2.704 10.656 6.829 10.68 ;
     RECT  6.661 33.648 6.869 34.392 ;
     RECT  6.865 3.984 6.901 4.008 ;
     RECT  6.793 32.448 6.949 32.472 ;
     RECT  6.869 33.648 6.949 34.296 ;
     RECT  6.764 1.68 7.139 2.28 ;
     RECT  6.661 7.776 7.141 9.384 ;
     RECT  6.829 10.656 7.141 11.4 ;
     RECT  7.153 29.088 7.237 29.112 ;
     RECT  7.237 29.088 7.261 29.832 ;
     RECT  6.613 31.344 7.261 31.464 ;
     RECT  6.949 32.448 7.571 34.296 ;
     RECT  6.073 0.576 7.573 0.6 ;
     RECT  6.901 3.552 7.573 4.008 ;
     RECT  7.261 29.088 7.573 31.464 ;
     RECT  7.571 32.448 7.573 33.048 ;
     RECT  7.573 0.288 7.585 0.6 ;
     RECT  7.573 3.552 7.585 4.248 ;
     RECT  7.573 29.088 7.585 33.048 ;
     RECT  7.141 7.776 7.657 11.4 ;
     RECT  7.261 12.576 7.657 12.6 ;
     RECT  7.621 14.688 7.765 14.712 ;
     RECT  7.139 2.148 7.808 2.28 ;
     RECT  7.585 3.552 7.808 4.584 ;
     RECT  5.317 5.76 7.808 5.784 ;
     RECT  7.657 7.776 7.808 12.6 ;
     RECT  7.765 14.496 7.808 14.712 ;
     RECT  7.189 26.112 7.808 26.136 ;
     RECT  7.585 28.752 7.808 33.048 ;
     RECT  7.585 0.288 8.003 1.128 ;
     RECT  7.808 2.148 8.104 33.048 ;
     RECT  7.571 34.272 8.147 34.296 ;
     RECT  8.104 27.36 8.237 33.048 ;
     RECT  8.104 12.528 8.597 15.96 ;
     RECT  8.597 12.528 8.633 13.704 ;
     RECT  8.237 27.36 8.675 31.8 ;
     RECT  8.633 12.576 8.741 13.704 ;
     RECT  8.675 27.36 8.771 29.736 ;
     RECT  8.597 15.168 8.785 15.96 ;
     RECT  8.104 2.832 8.813 4.584 ;
     RECT  8.741 13.056 8.849 13.704 ;
     RECT  8.104 9.648 8.915 10.68 ;
     RECT  8.675 30.72 9.029 31.8 ;
     RECT  8.849 13.392 9.107 13.704 ;
     RECT  8.813 2.88 9.133 4.584 ;
     RECT  8.771 27.36 9.155 29.688 ;
     RECT  9.029 30.768 9.196 31.8 ;
     RECT  8.104 5.76 9.241 8.664 ;
     RECT  9.196 30.912 9.241 31.8 ;
     RECT  8.104 26.112 9.277 26.136 ;
     RECT  9.155 27.36 9.277 27.864 ;
     RECT  8.003 0.288 9.347 0.312 ;
     RECT  8.629 33.072 9.349 33.096 ;
     RECT  9.107 13.392 9.395 13.656 ;
     RECT  9.241 30.912 9.461 31.896 ;
     RECT  9.241 5.664 9.565 8.664 ;
     RECT  9.565 5.664 9.577 9.096 ;
     RECT  9.133 2.88 9.613 4.68 ;
     RECT  9.155 29.088 9.641 29.688 ;
     RECT  9.577 5.664 9.731 6.408 ;
     RECT  9.461 31.344 9.745 31.896 ;
     RECT  9.277 26.112 9.749 27.864 ;
     RECT  9.349 33.072 9.817 33.672 ;
     RECT  9.641 29.088 9.857 29.64 ;
     RECT  9.857 29.328 9.893 29.64 ;
     RECT  9.817 32.976 9.901 33.672 ;
     RECT  8.915 10.32 9.925 10.68 ;
     RECT  9.577 7.632 9.953 9.096 ;
     RECT  9.613 2.88 9.971 4.584 ;
     RECT  9.901 33.024 10.019 33.672 ;
     RECT  9.953 7.632 10.177 9.144 ;
     RECT  9.925 10.224 10.177 10.68 ;
     RECT  9.749 26.448 10.213 27.864 ;
     RECT  9.745 31.344 10.213 31.944 ;
     RECT  9.971 2.928 10.253 4.584 ;
     RECT  10.177 7.632 10.259 10.68 ;
     RECT  9.731 6.384 10.433 6.408 ;
     RECT  9.395 13.392 10.537 13.56 ;
     RECT  10.213 31.344 10.565 31.992 ;
     RECT  10.259 8.64 10.573 10.68 ;
     RECT  10.573 8.64 10.609 11.064 ;
     RECT  8.785 15.168 10.681 15.192 ;
     RECT  10.609 8.64 10.693 11.208 ;
     RECT  10.213 26.448 10.897 28.344 ;
     RECT  9.893 29.328 10.897 29.352 ;
     RECT  10.253 3.216 10.933 4.584 ;
     RECT  10.537 13.104 10.933 13.56 ;
     RECT  10.897 26.448 10.937 29.352 ;
     RECT  10.501 18.768 10.973 18.792 ;
     RECT  10.837 0.576 11.005 0.6 ;
     RECT  10.681 14.784 11.029 15.192 ;
     RECT  10.937 26.688 11.029 29.352 ;
     RECT  10.565 30.768 11.029 31.992 ;
     RECT  10.933 13.104 11.036 13.656 ;
     RECT  11.005 0.528 11.117 0.6 ;
     RECT  11.036 13.056 11.123 13.656 ;
     RECT  11.123 13.632 11.149 13.656 ;
     RECT  11.029 14.784 11.149 15.96 ;
     RECT  11.029 26.688 11.153 31.992 ;
     RECT  11.117 0.576 11.189 0.6 ;
     RECT  11.149 13.632 11.221 15.96 ;
     RECT  11.153 26.736 11.269 31.992 ;
     RECT  10.019 33.024 11.269 33.048 ;
     RECT  10.259 7.632 11.365 7.656 ;
     RECT  10.933 3.216 11.369 5.112 ;
     RECT  11.269 26.736 11.369 33.048 ;
     RECT  11.365 7.392 11.557 7.656 ;
     RECT  11.369 33.024 11.557 33.048 ;
     RECT  11.557 6.768 11.573 7.656 ;
     RECT  11.221 13.632 11.585 16.536 ;
     RECT  11.585 13.632 11.795 16.152 ;
     RECT  11.573 6.24 11.797 7.656 ;
     RECT  10.693 8.64 11.797 11.064 ;
     RECT  11.557 33.024 11.905 33.096 ;
     RECT  11.369 26.736 11.909 31.8 ;
     RECT  8.161 1.728 11.948 1.752 ;
     RECT  11.795 15.168 11.981 16.152 ;
     RECT  11.905 33.024 11.987 33.672 ;
     RECT  11.948 1.104 12.035 1.752 ;
     RECT  11.369 3.312 12.049 5.112 ;
     RECT  11.797 6.24 12.049 11.064 ;
     RECT  11.981 15.168 12.053 15.96 ;
     RECT  11.987 33.648 12.169 33.672 ;
     RECT  12.049 3.312 12.179 11.064 ;
     RECT  11.795 13.632 12.181 13.848 ;
     RECT  12.179 3.312 12.22 7.464 ;
     RECT  12.22 3.312 12.227 5.736 ;
     RECT  12.227 3.312 12.476 4.824 ;
     RECT  11.909 29.664 12.553 31.8 ;
     RECT  11.909 26.736 12.581 28.248 ;
     RECT  12.476 2.88 12.613 4.824 ;
     RECT  12.553 29.664 12.853 31.944 ;
     RECT  12.581 26.208 12.985 28.248 ;
     RECT  12.853 29.664 12.985 32.376 ;
     RECT  12.181 13.584 13.045 13.848 ;
     RECT  12.053 15.168 13.045 15.192 ;
     RECT  12.179 8.496 13.093 11.064 ;
     RECT  12.985 26.208 13.129 32.376 ;
     RECT  12.035 1.728 13.208 1.752 ;
     RECT  12.613 2.736 13.208 4.824 ;
     RECT  12.22 6.768 13.208 7.464 ;
     RECT  13.093 8.496 13.208 11.976 ;
     RECT  13.045 13.584 13.208 15.192 ;
     RECT  13.129 26.208 13.208 32.568 ;
     RECT  13.208 1.728 13.285 32.568 ;
     RECT  12.62 0.288 13.331 0.312 ;
     RECT  13.285 1.728 13.429 32.76 ;
     RECT  13.429 1.728 13.504 32.856 ;
     RECT  13.504 32.496 13.525 32.856 ;
     RECT  13.504 26.64 13.565 31.464 ;
     RECT  13.504 10.656 13.645 15.96 ;
     RECT  13.504 2.832 13.66 5.16 ;
     RECT  13.565 26.784 13.667 31.464 ;
     RECT  13.645 10.656 13.673 12.648 ;
     RECT  13.525 32.496 13.811 33.672 ;
     RECT  13.811 32.496 13.859 32.952 ;
     RECT  13.645 13.632 13.925 15.96 ;
     RECT  13.66 2.832 14.003 5.112 ;
     RECT  13.859 32.496 14.051 32.568 ;
     RECT  14.003 2.832 14.099 5.064 ;
     RECT  13.504 6.768 14.185 9.096 ;
     RECT  14.099 2.832 14.249 4.584 ;
     RECT  13.504 17.616 14.285 17.64 ;
     RECT  14.051 32.496 14.609 32.52 ;
     RECT  14.185 6.768 14.641 6.84 ;
     RECT  13.673 10.656 14.681 11.976 ;
     RECT  13.925 14.64 14.681 15.96 ;
     RECT  14.641 6.24 14.725 6.84 ;
     RECT  14.185 8.112 14.749 9.096 ;
     RECT  14.681 10.656 14.749 10.872 ;
     RECT  13.667 26.784 14.773 28.104 ;
     RECT  13.667 29.088 14.773 31.464 ;
     RECT  14.773 26.784 14.825 31.464 ;
     RECT  13.925 13.632 14.857 13.656 ;
     RECT  14.681 11.904 14.917 11.976 ;
     RECT  14.857 13.056 14.917 13.656 ;
     RECT  14.681 15.936 14.929 15.96 ;
     RECT  14.825 26.784 15.037 29.784 ;
     RECT  14.485 25.632 15.077 25.656 ;
     RECT  15.037 26.736 15.121 29.784 ;
     RECT  14.917 11.904 15.253 13.656 ;
     RECT  14.681 14.64 15.253 14.856 ;
     RECT  14.825 30.768 15.301 31.464 ;
     RECT  13.504 1.728 15.361 1.752 ;
     RECT  14.749 8.112 15.401 10.872 ;
     RECT  14.249 3.888 15.493 4.584 ;
     RECT  14.725 6.72 15.509 6.84 ;
     RECT  15.493 3.408 15.541 4.584 ;
     RECT  15.121 26.784 15.587 29.784 ;
     RECT  15.509 6.816 15.685 6.84 ;
     RECT  15.401 8.112 15.685 10.68 ;
     RECT  14.929 15.936 15.685 16.008 ;
     RECT  15.587 26.832 15.788 29.784 ;
     RECT  15.301 30.768 15.788 31.944 ;
     RECT  15.541 3.312 15.941 4.584 ;
     RECT  15.685 6.816 15.971 10.68 ;
     RECT  15.361 1.728 16.021 1.848 ;
     RECT  15.941 3.312 16.021 4.152 ;
     RECT  15.973 33.024 16.021 33.672 ;
     RECT  16.021 1.728 16.163 4.152 ;
     RECT  16.163 1.728 16.211 1.752 ;
     RECT  16.021 32.928 16.259 33.672 ;
     RECT  15.253 11.904 16.261 14.856 ;
     RECT  15.685 15.936 16.261 16.2 ;
     RECT  16.261 11.904 16.265 16.2 ;
     RECT  15.788 26.832 16.309 31.944 ;
     RECT  16.259 32.928 16.309 33.048 ;
     RECT  16.265 13.68 16.517 13.704 ;
     RECT  15.781 18.048 16.553 18.072 ;
     RECT  15.971 6.816 16.585 8.376 ;
     RECT  16.585 6.24 16.625 8.376 ;
     RECT  16.556 1.104 16.643 1.128 ;
     RECT  16.265 14.784 16.733 16.2 ;
     RECT  16.733 15.984 16.741 16.2 ;
     RECT  16.309 26.832 16.787 33.048 ;
     RECT  16.787 30.24 16.835 31.944 ;
     RECT  16.741 15.984 16.841 16.44 ;
     RECT  15.971 9.648 16.909 10.68 ;
     RECT  16.549 5.136 16.981 5.16 ;
     RECT  16.625 6.24 16.981 7.992 ;
     RECT  16.163 3.408 17.017 4.152 ;
     RECT  16.981 5.136 17.017 7.992 ;
     RECT  16.787 26.832 17.029 29.16 ;
     RECT  16.265 11.904 17.093 12.504 ;
     RECT  17.017 3.408 17.219 7.992 ;
     RECT  16.981 18.768 17.237 18.792 ;
     RECT  17.219 3.408 17.365 5.256 ;
     RECT  16.909 9.648 17.413 10.824 ;
     RECT  17.029 26.784 17.509 29.16 ;
     RECT  17.093 12.48 17.557 12.504 ;
     RECT  17.413 13.632 17.557 13.656 ;
     RECT  17.413 9.12 17.701 10.824 ;
     RECT  16.787 33.024 17.708 33.048 ;
     RECT  17.509 26.688 17.749 29.16 ;
     RECT  16.835 30.24 17.749 30.792 ;
     RECT  16.733 14.784 17.797 14.856 ;
     RECT  16.841 15.984 17.797 16.008 ;
     RECT  16.835 31.92 17.948 31.944 ;
     RECT  17.708 33.024 17.948 33.096 ;
     RECT  17.749 26.688 18.053 30.792 ;
     RECT  17.948 31.92 18.085 33.096 ;
     RECT  17.701 9.12 18.133 11.16 ;
     RECT  18.085 31.92 18.227 33.192 ;
     RECT  17.989 0.288 18.229 0.312 ;
     RECT  18.053 26.64 18.229 30.792 ;
     RECT  18.133 9.12 18.241 11.448 ;
     RECT  17.557 12.48 18.241 13.656 ;
     RECT  17.365 2.736 18.313 5.256 ;
     RECT  17.219 6.24 18.313 7.992 ;
     RECT  18.229 26.016 18.313 30.792 ;
     RECT  18.227 31.92 18.313 33.096 ;
     RECT  17.797 14.784 18.373 16.008 ;
     RECT  18.241 9.12 18.413 13.656 ;
     RECT  18.373 14.784 18.529 16.296 ;
     RECT  18.229 0.288 18.533 0.408 ;
     RECT  17.729 1.728 18.608 1.752 ;
     RECT  18.313 2.736 18.608 7.992 ;
     RECT  18.413 9.072 18.608 13.656 ;
     RECT  18.529 14.736 18.608 16.296 ;
     RECT  18.313 26.016 18.608 33.096 ;
     RECT  18.608 1.728 18.904 33.096 ;
     RECT  18.533 0.288 19.043 0.36 ;
     RECT  19.043 0.288 19.283 0.312 ;
     RECT  18.904 32.928 19.285 33.096 ;
     RECT  18.904 15.936 19.289 15.96 ;
     RECT  18.904 7.632 19.369 12.552 ;
     RECT  18.904 1.728 19.685 1.848 ;
     RECT  19.369 7.632 19.721 9.048 ;
     RECT  19.721 7.632 19.865 8.76 ;
     RECT  18.904 26.784 19.955 31.944 ;
     RECT  19.955 26.784 19.996 31.464 ;
     RECT  18.904 14.736 20.005 14.76 ;
     RECT  18.904 2.832 20.101 6.552 ;
     RECT  20.005 14.496 20.113 14.76 ;
     RECT  20.101 2.448 20.149 6.552 ;
     RECT  19.865 7.632 20.149 8.568 ;
     RECT  20.113 14.208 20.149 14.76 ;
     RECT  19.285 32.928 20.197 33.672 ;
     RECT  20.197 32.496 20.332 33.672 ;
     RECT  19.369 10.08 20.369 12.552 ;
     RECT  20.332 32.496 20.369 33.72 ;
     RECT  20.149 2.448 20.387 8.568 ;
     RECT  20.149 13.68 20.387 14.76 ;
     RECT  20.389 0.288 20.473 0.312 ;
     RECT  20.387 2.832 20.483 8.568 ;
     RECT  20.369 10.08 20.513 10.872 ;
     RECT  20.473 0.288 20.531 1.176 ;
     RECT  19.996 29.664 20.579 31.464 ;
     RECT  20.531 1.152 20.675 1.176 ;
     RECT  19.996 26.784 20.677 28.584 ;
     RECT  20.677 26.208 20.765 28.584 ;
     RECT  20.483 7.632 20.801 8.568 ;
     RECT  20.387 14.256 20.905 14.76 ;
     RECT  20.629 15.792 20.905 15.816 ;
     RECT  20.369 32.592 20.917 33.72 ;
     RECT  20.905 14.256 20.933 15.816 ;
     RECT  20.579 29.664 20.977 31.416 ;
     RECT  20.483 2.832 20.989 5.928 ;
     RECT  20.905 22.8 21.053 22.824 ;
     RECT  20.765 26.736 21.121 28.584 ;
     RECT  20.977 29.568 21.121 31.416 ;
     RECT  20.917 32.592 21.203 33.816 ;
     RECT  20.933 14.256 21.277 15.96 ;
     RECT  20.989 5.616 21.299 5.928 ;
     RECT  20.989 2.832 21.313 4.584 ;
     RECT  20.801 8.496 21.349 8.568 ;
     RECT  21.277 14.784 21.377 15.96 ;
     RECT  19.933 17.088 21.377 17.112 ;
     RECT  21.121 26.736 21.377 31.416 ;
     RECT  21.299 5.712 21.385 5.928 ;
     RECT  21.377 15.792 21.437 15.96 ;
     RECT  21.313 2.88 21.443 4.584 ;
     RECT  21.437 15.792 21.521 16.536 ;
     RECT  20.513 10.08 21.541 10.68 ;
     RECT  20.369 12.528 21.553 12.552 ;
     RECT  20.753 1.728 21.565 1.8 ;
     RECT  21.565 1.776 21.683 1.8 ;
     RECT  21.541 10.08 21.769 10.824 ;
     RECT  21.377 29.088 21.781 31.416 ;
     RECT  21.203 32.592 21.781 33.672 ;
     RECT  21.521 15.792 21.845 15.816 ;
     RECT  21.385 5.904 21.877 5.928 ;
     RECT  21.493 7.2 21.877 7.224 ;
     RECT  21.877 5.904 21.949 7.224 ;
     RECT  21.349 8.496 21.949 9.096 ;
     RECT  21.949 5.904 22.033 9.096 ;
     RECT  21.377 26.736 22.069 28.008 ;
     RECT  21.781 29.088 22.097 33.672 ;
     RECT  22.069 26.208 22.117 28.008 ;
     RECT  22.097 30.096 22.163 33.672 ;
     RECT  22.117 25.632 22.277 28.008 ;
     RECT  22.033 5.904 22.307 7.464 ;
     RECT  22.033 8.544 22.309 9.096 ;
     RECT  21.769 10.08 22.309 10.872 ;
     RECT  21.925 17.616 22.385 17.64 ;
     RECT  22.307 5.904 22.417 6.888 ;
     RECT  22.309 8.544 22.417 10.872 ;
     RECT  22.163 30.24 22.457 33.672 ;
     RECT  22.457 30.48 22.489 33.672 ;
     RECT  22.417 8.544 22.565 10.968 ;
     RECT  22.561 13.872 22.597 13.896 ;
     RECT  21.443 3.312 22.673 4.584 ;
     RECT  22.277 25.632 22.673 25.656 ;
     RECT  22.565 10.272 22.681 10.968 ;
     RECT  22.193 0.576 22.708 0.6 ;
     RECT  21.553 12.048 22.733 12.552 ;
     RECT  22.597 13.872 22.733 14.232 ;
     RECT  22.489 30.48 22.745 33.768 ;
     RECT  22.745 33.072 22.835 33.768 ;
     RECT  22.708 0.528 22.853 0.6 ;
     RECT  22.097 29.088 22.877 29.112 ;
     RECT  22.633 1.728 23.029 1.752 ;
     RECT  22.835 33.072 23.113 33.672 ;
     RECT  22.877 29.04 23.125 29.112 ;
     RECT  22.277 26.784 23.221 28.008 ;
     RECT  23.125 29.04 23.221 29.208 ;
     RECT  22.565 8.544 23.245 9.096 ;
     RECT  22.681 10.608 23.317 10.968 ;
     RECT  22.733 12.048 23.317 14.232 ;
     RECT  23.113 33.072 23.363 33.096 ;
     RECT  22.673 3.888 23.365 4.584 ;
     RECT  22.417 5.664 23.365 6.888 ;
     RECT  23.029 1.728 23.461 2.328 ;
     RECT  22.981 17.088 23.461 17.112 ;
     RECT  23.221 26.784 23.461 29.208 ;
     RECT  23.245 8.448 23.605 9.096 ;
     RECT  23.461 1.728 23.641 2.856 ;
     RECT  23.641 1.104 23.713 2.856 ;
     RECT  23.365 3.888 23.713 6.888 ;
     RECT  23.317 10.608 23.713 14.232 ;
     RECT  23.461 26.592 23.713 29.256 ;
     RECT  22.745 30.48 23.713 31.944 ;
     RECT  23.713 26.592 23.797 31.944 ;
     RECT  23.713 1.104 23.861 6.888 ;
     RECT  23.861 2.148 24.008 6.888 ;
     RECT  23.605 8.256 24.008 9.096 ;
     RECT  23.713 10.608 24.008 14.856 ;
     RECT  23.173 16.08 24.008 16.104 ;
     RECT  23.461 17.088 24.008 17.64 ;
     RECT  23.797 26.592 24.008 33.048 ;
     RECT  23.861 1.104 24.085 1.176 ;
     RECT  24.008 2.148 24.112 33.048 ;
     RECT  24.112 2.418 24.304 33.048 ;
     RECT  24.085 0.288 24.353 1.176 ;
     RECT  24.304 2.736 24.419 11.4 ;
     RECT  24.353 0.192 24.437 1.176 ;
     RECT  24.419 8.496 24.46 11.4 ;
     RECT  24.304 26.208 24.469 33.048 ;
     RECT  24.469 26.208 24.517 33.672 ;
     RECT  24.437 0.288 24.563 1.176 ;
     RECT  24.304 15.936 24.661 16.2 ;
     RECT  24.46 8.496 24.725 9.096 ;
     RECT  24.46 10.224 24.905 11.4 ;
     RECT  24.725 8.544 24.947 9.096 ;
     RECT  24.304 25.104 24.995 25.224 ;
     RECT  24.947 8.544 25.043 8.712 ;
     RECT  24.995 25.2 25.043 25.224 ;
     RECT  24.304 22.8 25.049 22.824 ;
     RECT  24.419 2.736 25.187 7.464 ;
     RECT  24.517 26.208 25.189 33.72 ;
     RECT  25.189 26.208 25.201 33.816 ;
     RECT  24.563 0.288 25.235 0.312 ;
     RECT  25.201 26.688 25.235 33.816 ;
     RECT  25.187 2.736 25.265 7.416 ;
     RECT  25.117 1.728 25.283 1.752 ;
     RECT  25.265 5.808 25.373 7.416 ;
     RECT  25.265 2.736 25.445 4.632 ;
     RECT  25.235 32.448 25.523 33.816 ;
     RECT  24.304 12.528 25.525 12.552 ;
     RECT  25.525 12.528 25.765 13.08 ;
     RECT  25.765 12.528 25.849 13.128 ;
     RECT  25.849 12.528 25.913 12.552 ;
     RECT  24.905 10.224 25.985 11.304 ;
     RECT  25.235 26.688 25.985 31.368 ;
     RECT  25.373 6.24 25.993 7.416 ;
     RECT  24.304 14.208 26.053 14.232 ;
     RECT  24.661 16.176 26.053 16.2 ;
     RECT  25.043 8.688 26.089 8.712 ;
     RECT  26.053 13.68 26.089 14.232 ;
     RECT  26.053 15.36 26.089 16.2 ;
     RECT  25.985 29.04 26.093 31.368 ;
     RECT  26.089 13.68 26.129 16.2 ;
     RECT  26.129 13.68 26.147 15.96 ;
     RECT  26.147 13.68 26.195 14.856 ;
     RECT  25.445 3.408 26.237 4.632 ;
     RECT  25.993 6.288 26.341 7.416 ;
     RECT  26.089 8.448 26.341 8.712 ;
     RECT  25.693 2.256 26.369 2.28 ;
     RECT  26.005 18.192 26.381 18.216 ;
     RECT  25.985 26.688 26.381 27.96 ;
     RECT  26.237 3.408 26.387 3.96 ;
     RECT  26.093 29.088 26.389 31.368 ;
     RECT  25.523 32.448 26.389 33.096 ;
     RECT  25.657 0.576 26.417 0.6 ;
     RECT  26.341 6.288 26.425 8.712 ;
     RECT  26.369 5.136 26.453 5.16 ;
     RECT  26.369 1.728 26.513 2.28 ;
     RECT  26.513 1.728 26.579 2.856 ;
     RECT  26.579 1.728 26.593 1.848 ;
     RECT  26.579 2.832 26.597 2.856 ;
     RECT  26.425 8.448 26.665 8.712 ;
     RECT  26.389 29.088 26.669 33.096 ;
     RECT  26.665 8.448 26.701 9.096 ;
     RECT  25.985 10.848 26.725 11.304 ;
     RECT  26.425 6.288 26.741 7.272 ;
     RECT  26.387 3.936 26.867 3.96 ;
     RECT  26.147 15.936 26.915 15.96 ;
     RECT  26.669 32.976 26.965 33.096 ;
     RECT  26.593 1.104 27.011 1.848 ;
     RECT  26.725 10.848 27.061 11.4 ;
     RECT  26.629 12.384 27.061 12.408 ;
     RECT  26.669 29.088 27.109 31.992 ;
     RECT  27.061 10.848 27.145 12.408 ;
     RECT  26.195 14.544 27.157 14.856 ;
     RECT  27.157 13.68 27.209 14.856 ;
     RECT  27.145 10.848 27.245 11.4 ;
     RECT  27.209 13.68 27.281 13.704 ;
     RECT  26.701 8.448 27.301 9.72 ;
     RECT  27.245 10.848 27.301 11.304 ;
     RECT  27.301 8.448 27.317 11.304 ;
     RECT  27.011 1.68 27.325 1.848 ;
     RECT  26.381 26.688 27.356 27.384 ;
     RECT  27.209 14.784 27.413 14.856 ;
     RECT  27.356 26.16 27.445 27.384 ;
     RECT  27.109 28.416 27.445 31.992 ;
     RECT  27.397 3.984 27.493 4.008 ;
     RECT  26.741 6.816 27.493 7.272 ;
     RECT  27.317 9.072 27.497 11.304 ;
     RECT  27.413 14.784 27.497 15.432 ;
     RECT  27.445 26.16 27.569 31.992 ;
     RECT  27.493 3.984 27.587 4.584 ;
     RECT  27.493 6.816 27.889 7.416 ;
     RECT  27.877 2.832 27.925 2.856 ;
     RECT  27.587 3.984 27.925 4.104 ;
     RECT  27.569 26.16 27.929 31.416 ;
     RECT  26.965 32.976 27.965 33.672 ;
     RECT  27.325 1.68 28.019 1.752 ;
     RECT  27.889 6.576 28.021 7.416 ;
     RECT  28.021 6.576 28.067 7.992 ;
     RECT  28.067 6.576 28.105 6.84 ;
     RECT  27.965 32.976 28.165 33.048 ;
     RECT  27.497 9.072 28.211 11.016 ;
     RECT  27.781 12.528 28.213 12.552 ;
     RECT  27.925 2.832 28.297 4.104 ;
     RECT  28.213 12 28.297 13.08 ;
     RECT  27.497 14.784 28.333 15.384 ;
     RECT  28.019 1.728 28.357 1.752 ;
     RECT  27.781 16.512 28.361 16.536 ;
     RECT  28.297 12.528 28.403 13.08 ;
     RECT  28.297 3.312 28.441 4.104 ;
     RECT  28.333 14.784 28.537 14.808 ;
     RECT  28.165 32.496 28.549 33.048 ;
     RECT  28.067 7.968 28.645 7.992 ;
     RECT  28.211 9.072 28.645 9.096 ;
     RECT  28.441 3.408 28.693 4.104 ;
     RECT  27.929 26.736 28.693 31.416 ;
     RECT  28.549 32.448 28.693 33.048 ;
     RECT  28.693 3.408 28.753 4.584 ;
     RECT  28.105 5.664 28.753 6.84 ;
     RECT  28.693 26.736 28.925 33.048 ;
     RECT  28.925 26.544 28.933 33.048 ;
     RECT  28.211 10.224 29.173 11.016 ;
     RECT  28.357 1.728 29.197 1.848 ;
     RECT  28.645 7.968 29.221 9.096 ;
     RECT  29.173 10.224 29.221 11.352 ;
     RECT  29.197 1.824 29.408 1.848 ;
     RECT  28.753 3.408 29.408 6.84 ;
     RECT  29.221 7.968 29.408 11.352 ;
     RECT  28.403 12.528 29.408 12.552 ;
     RECT  28.537 14.208 29.408 14.808 ;
     RECT  28.933 26.544 29.408 33.672 ;
     RECT  29.408 1.824 29.413 33.672 ;
     RECT  29.413 1.824 29.704 33.72 ;
     RECT  29.704 6.288 29.945 9.144 ;
     RECT  29.704 26.256 29.945 31.944 ;
     RECT  29.704 32.928 29.948 33.72 ;
     RECT  29.221 0.288 29.987 0.312 ;
     RECT  29.945 26.544 30.035 31.944 ;
     RECT  29.948 32.928 30.035 33.768 ;
     RECT  29.704 10.128 30.053 11.832 ;
     RECT  30.035 26.784 30.061 31.944 ;
     RECT  29.945 6.288 30.169 7.368 ;
     RECT  30.061 29.664 30.179 31.944 ;
     RECT  29.704 13.008 30.197 15.96 ;
     RECT  29.945 8.448 30.275 9.144 ;
     RECT  30.035 32.928 30.601 33.672 ;
     RECT  30.053 11.808 30.697 11.832 ;
     RECT  30.197 13.008 30.697 13.032 ;
     RECT  30.275 8.496 30.805 9.144 ;
     RECT  30.053 10.128 30.805 10.632 ;
     RECT  30.197 14.208 30.809 15.96 ;
     RECT  29.704 2.88 30.844 4.584 ;
     RECT  30.805 8.496 30.889 10.632 ;
     RECT  30.841 17.088 30.925 17.112 ;
     RECT  30.809 14.544 30.995 15.96 ;
     RECT  30.179 29.712 30.997 31.944 ;
     RECT  30.601 32.928 30.997 33.144 ;
     RECT  30.995 14.64 31.093 15.96 ;
     RECT  30.997 29.712 31.097 33.144 ;
     RECT  30.061 26.784 31.129 28.392 ;
     RECT  31.093 14.64 31.133 16.536 ;
     RECT  31.045 18.192 31.133 18.216 ;
     RECT  31.133 14.832 31.177 16.536 ;
     RECT  31.129 26.736 31.201 28.392 ;
     RECT  30.169 6.816 31.237 7.368 ;
     RECT  30.889 8.496 31.237 9.096 ;
     RECT  31.097 29.712 31.285 32.52 ;
     RECT  31.201 26.736 31.34 28.536 ;
     RECT  31.237 6.816 31.385 9.096 ;
     RECT  31.34 26.64 31.427 28.536 ;
     RECT  31.427 26.736 31.429 28.536 ;
     RECT  31.285 29.616 31.475 32.52 ;
     RECT  30.697 11.808 31.523 13.032 ;
     RECT  31.445 2.832 31.529 2.856 ;
     RECT  31.385 6.816 31.628 7.224 ;
     RECT  31.177 14.832 31.667 15.672 ;
     RECT  31.573 33.648 31.669 33.672 ;
     RECT  31.385 8.496 31.709 9.096 ;
     RECT  31.628 6.24 31.715 7.224 ;
     RECT  31.669 33.648 31.753 33.72 ;
     RECT  31.429 26.736 31.853 28.584 ;
     RECT  31.853 26.736 31.859 27.912 ;
     RECT  30.844 3.888 31.861 4.584 ;
     RECT  31.709 8.592 31.885 9.096 ;
     RECT  31.753 33.648 31.889 33.672 ;
     RECT  31.861 3.888 31.961 4.632 ;
     RECT  31.885 8.592 32.029 9.144 ;
     RECT  31.961 3.888 32.053 4.584 ;
     RECT  30.889 10.224 32.101 10.632 ;
     RECT  30.257 1.728 32.129 1.752 ;
     RECT  31.523 13.008 32.309 13.032 ;
     RECT  31.523 11.808 32.321 11.976 ;
     RECT  32.029 8.592 32.353 9.24 ;
     RECT  32.101 10.224 32.353 10.728 ;
     RECT  32.309 13.008 32.393 13.656 ;
     RECT  32.353 8.592 32.437 10.728 ;
     RECT  32.437 9.936 32.533 10.728 ;
     RECT  31.475 29.616 32.533 32.472 ;
     RECT  31.715 6.672 32.561 7.224 ;
     RECT  32.533 29.088 32.581 32.472 ;
     RECT  32.561 6.672 32.645 7.416 ;
     RECT  32.129 1.728 32.677 1.848 ;
     RECT  32.393 13.008 32.681 13.128 ;
     RECT  32.645 6.672 32.717 7.224 ;
     RECT  32.677 1.728 32.764 2.328 ;
     RECT  32.581 29.088 32.771 33.096 ;
     RECT  32.437 8.592 32.813 8.76 ;
     RECT  32.771 29.184 32.861 33.096 ;
     RECT  32.717 6.672 32.929 6.696 ;
     RECT  32.053 3.408 32.972 4.584 ;
     RECT  31.859 26.784 33.011 27.912 ;
     RECT  32.861 29.184 33.011 32.424 ;
     RECT  33.011 29.184 33.059 32.136 ;
     RECT  32.533 9.936 33.085 11.4 ;
     RECT  31.667 14.832 33.109 14.856 ;
     RECT  33.109 14.784 33.325 14.856 ;
     RECT  32.929 6.288 33.356 6.696 ;
     RECT  33.325 14.784 33.397 15.384 ;
     RECT  33.397 14.256 33.409 15.384 ;
     RECT  33.085 9.936 33.473 11.304 ;
     RECT  33.409 14.256 33.539 14.856 ;
     RECT  32.813 8.544 33.613 8.76 ;
     RECT  33.539 14.832 33.625 14.856 ;
     RECT  33.473 10.848 33.761 11.304 ;
     RECT  33.011 27.36 33.761 27.912 ;
     RECT  33.356 6.24 33.829 6.696 ;
     RECT  33.613 7.968 33.829 8.76 ;
     RECT  33.577 16.512 33.829 16.536 ;
     RECT  33.829 6.24 33.901 6.888 ;
     RECT  33.059 29.664 34.021 32.136 ;
     RECT  32.681 13.104 34.045 13.128 ;
     RECT  34.021 29.616 34.309 32.136 ;
     RECT  33.901 5.568 34.357 6.888 ;
     RECT  33.829 7.968 34.357 9.672 ;
     RECT  32.764 1.728 34.549 1.752 ;
     RECT  32.972 2.784 34.549 4.584 ;
     RECT  34.357 5.568 34.549 9.672 ;
     RECT  34.441 10.8 34.549 10.824 ;
     RECT  34.045 13.056 34.652 13.128 ;
     RECT  34.309 29.616 34.697 33.096 ;
     RECT  34.549 1.728 34.808 10.824 ;
     RECT  34.652 12.528 34.808 13.128 ;
     RECT  33.829 15.936 34.808 16.536 ;
     RECT  33.761 27.36 34.808 27.384 ;
     RECT  34.045 28.464 34.808 28.488 ;
     RECT  34.697 29.616 34.808 32.76 ;
     RECT  34.808 1.728 35.104 32.76 ;
     RECT  35.104 5.568 35.219 5.592 ;
     RECT  35.104 7.92 35.219 9.096 ;
     RECT  35.029 0.288 35.267 0.312 ;
     RECT  35.104 3.408 35.267 4.248 ;
     RECT  35.104 13.056 35.273 13.656 ;
     RECT  35.104 6.72 35.315 6.84 ;
     RECT  35.104 30.24 35.315 32.76 ;
     RECT  35.219 9.072 35.345 9.096 ;
     RECT  35.267 3.408 35.353 4.104 ;
     RECT  35.315 6.72 35.363 6.744 ;
     RECT  35.219 7.968 35.411 7.992 ;
     RECT  35.353 3.984 35.597 4.104 ;
     RECT  35.597 4.08 35.633 4.104 ;
     RECT  35.104 1.728 35.651 2.28 ;
     RECT  35.104 10.224 35.705 10.248 ;
     RECT  35.315 30.24 35.741 32.472 ;
     RECT  35.651 1.728 35.813 1.752 ;
     RECT  35.104 17.088 36.073 17.112 ;
     RECT  35.741 30.912 36.131 32.472 ;
     RECT  35.104 15.36 36.137 15.384 ;
     RECT  36.131 31.872 36.137 32.472 ;
     RECT  35.273 13.632 36.169 13.656 ;
     RECT  36.169 13.632 36.205 14.232 ;
     RECT  36.205 13.632 36.277 14.76 ;
     RECT  36.277 13.536 36.569 14.76 ;
     RECT  36.569 14.208 36.641 14.76 ;
     RECT  36.137 31.872 36.677 32.376 ;
     RECT  36.641 14.208 36.713 14.232 ;
     RECT  36.677 31.872 36.857 31.992 ;
     RECT  36.857 31.872 37.757 31.896 ;
     RECT  40.208 2.148 40.312 32.412 ;
     RECT  40.312 2.418 40.504 32.142 ;
    LAYER M5 ;
     RECT  6.528 0.144 35.784 1.763 ;
     RECT  6.672 1.763 35.64 1.811 ;
     RECT  2.4 2.137 2.52 2.151 ;
     RECT  40.2 2.137 40.32 2.151 ;
     RECT  6.816 1.811 35.64 2.291 ;
     RECT  6.96 2.291 35.496 4.019 ;
     RECT  27.552 4.019 35.496 4.115 ;
     RECT  27.552 4.115 35.304 4.595 ;
     RECT  27.888 4.595 35.304 6.709 ;
     RECT  7.536 4.019 26.568 7.237 ;
     RECT  7.536 7.237 26.616 7.765 ;
     RECT  27.888 6.709 35.352 7.957 ;
     RECT  6.864 7.765 26.616 9.061 ;
     RECT  6.672 9.061 26.712 9.155 ;
     RECT  22.512 9.155 26.712 9.731 ;
     RECT  6.672 9.155 9.624 10.213 ;
     RECT  10.656 9.155 16.824 10.213 ;
     RECT  17.856 9.155 21.432 10.213 ;
     RECT  22.608 9.731 26.712 10.213 ;
     RECT  27.888 7.957 35.4 10.213 ;
     RECT  22.608 10.213 35.688 10.259 ;
     RECT  6.672 10.213 21.432 10.741 ;
     RECT  22.608 10.259 29.928 10.741 ;
     RECT  6.672 10.741 29.928 10.835 ;
     RECT  6.672 10.835 29.712 11.219 ;
     RECT  11.088 11.219 29.712 13.091 ;
     RECT  11.28 13.091 29.712 13.621 ;
     RECT  30.912 10.259 35.688 13.621 ;
     RECT  11.28 13.621 35.688 13.715 ;
     RECT  6.672 11.219 9.96 14.773 ;
     RECT  11.28 13.715 20.184 14.773 ;
     RECT  21.216 13.715 35.688 15.349 ;
     RECT  6.672 14.773 20.184 15.781 ;
     RECT  21.216 15.349 36.12 15.781 ;
     RECT  0.24 10.645 0.264 15.923 ;
     RECT  6.672 15.781 36.12 30.947 ;
     RECT  6.672 30.947 36.024 31.859 ;
     RECT  6.672 31.859 35.784 31.861 ;
     RECT  2.4 2.151 2.712 32.409 ;
     RECT  40.2 2.151 40.512 32.409 ;
     RECT  2.4 32.409 2.52 32.423 ;
     RECT  40.2 32.409 40.32 32.423 ;
     RECT  6.528 31.861 35.784 34.384 ;
     RECT  26.568 4.019 27.552 4.595 ;
     RECT  26.568 4.595 27.888 7.237 ;
     RECT  26.616 7.237 27.888 9.061 ;
     RECT  26.712 9.061 27.888 10.213 ;
     RECT  9.624 9.155 10.656 10.213 ;
     RECT  16.824 9.155 17.856 10.213 ;
     RECT  21.432 9.155 22.512 9.731 ;
     RECT  21.432 9.731 22.608 10.741 ;
     RECT  29.928 10.259 30.912 10.835 ;
     RECT  29.712 10.835 30.912 13.621 ;
     RECT  9.96 11.219 11.088 13.091 ;
     RECT  9.96 13.091 11.28 14.773 ;
     RECT  20.184 13.715 21.216 15.781 ;
  END
END ot_s81_pq_bc_slice3
END LIBRARY
